VERSION 5.8 ;
BUSBITCHARS "[]" ;
DIVIDERCHAR "/" ;
UNITS
    DATABASE MICRONS 1000 ;
END UNITS

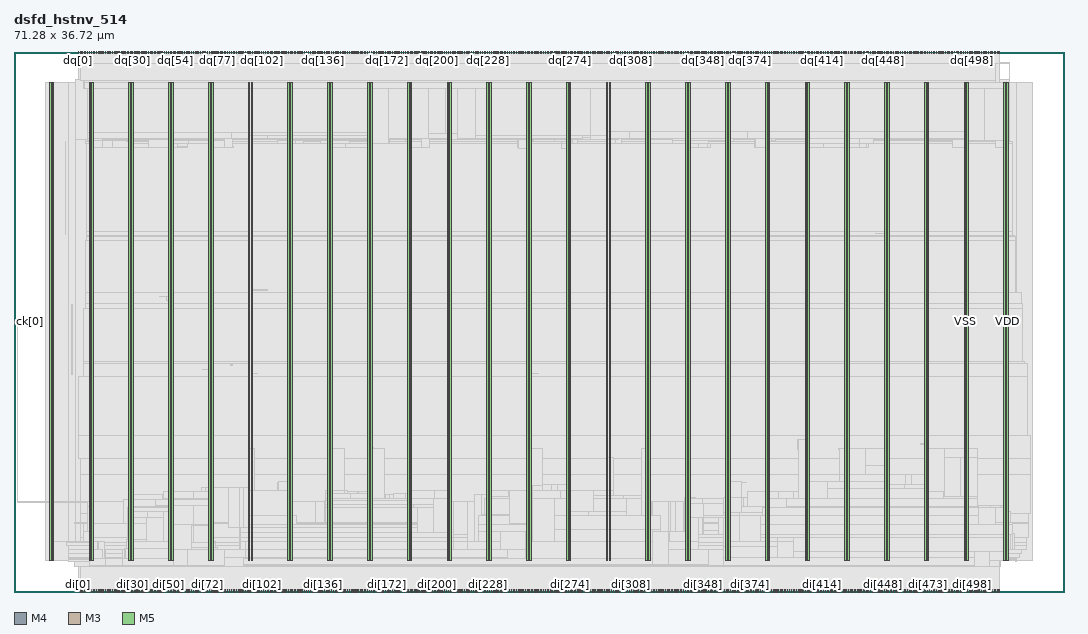
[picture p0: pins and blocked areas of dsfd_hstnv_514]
MACRO dsfd_hstnv_514
  FOREIGN dsfd_hstnv_514 0 0 ;
  CLASS BLOCK ;
  SIZE 71.28 BY 36.72 ;
  PIN ck[0]
    DIRECTION INPUT ;
    USE SIGNAL ;
    PORT
      LAYER M4 ;
        RECT  0 18.384 0.192 18.408 ;
    END
    PORT
      LAYER M4 ;
        RECT  0.156 18.384 0.275 18.408 ;
    END
  END ck[0]
  PIN di[0]
    DIRECTION INPUT ;
    USE SIGNAL ;
    PORT
      LAYER M3 ;
        RECT  4.356 0 4.374 0.144 ;
    END
  END di[0]
  PIN di[100]
    DIRECTION INPUT ;
    USE SIGNAL ;
    PORT
      LAYER M3 ;
        RECT  16.56 0 16.578 0.144 ;
    END
  END di[100]
  PIN di[101]
    DIRECTION INPUT ;
    USE SIGNAL ;
    PORT
      LAYER M5 ;
        RECT  16.656 0 16.68 0.192 ;
    END
  END di[101]
  PIN di[102]
    DIRECTION INPUT ;
    USE SIGNAL ;
    PORT
      LAYER M3 ;
        RECT  16.812 0 16.83 0.144 ;
    END
  END di[102]
  PIN di[103]
    DIRECTION INPUT ;
    USE SIGNAL ;
    PORT
      LAYER M5 ;
        RECT  16.944 0 16.968 0.192 ;
    END
  END di[103]
  PIN di[104]
    DIRECTION INPUT ;
    USE SIGNAL ;
    PORT
      LAYER M3 ;
        RECT  17.064 0 17.082 0.144 ;
    END
  END di[104]
  PIN di[105]
    DIRECTION INPUT ;
    USE SIGNAL ;
    PORT
      LAYER M5 ;
        RECT  17.184 0 17.208 0.192 ;
    END
  END di[105]
  PIN di[106]
    DIRECTION INPUT ;
    USE SIGNAL ;
    PORT
      LAYER M3 ;
        RECT  17.28 0 17.298 0.144 ;
    END
  END di[106]
  PIN di[107]
    DIRECTION INPUT ;
    USE SIGNAL ;
    PORT
      LAYER M5 ;
        RECT  17.424 0 17.448 0.192 ;
    END
  END di[107]
  PIN di[108]
    DIRECTION INPUT ;
    USE SIGNAL ;
    PORT
      LAYER M3 ;
        RECT  17.532 0 17.55 0.144 ;
    END
  END di[108]
  PIN di[109]
    DIRECTION INPUT ;
    USE SIGNAL ;
    PORT
      LAYER M5 ;
        RECT  17.664 0 17.688 0.192 ;
    END
  END di[109]
  PIN di[10]
    DIRECTION INPUT ;
    USE SIGNAL ;
    PORT
      LAYER M3 ;
        RECT  5.58 0 5.598 0.144 ;
    END
  END di[10]
  PIN di[110]
    DIRECTION INPUT ;
    USE SIGNAL ;
    PORT
      LAYER M3 ;
        RECT  17.784 0 17.802 0.144 ;
    END
  END di[110]
  PIN di[111]
    DIRECTION INPUT ;
    USE SIGNAL ;
    PORT
      LAYER M5 ;
        RECT  17.904 0 17.928 0.192 ;
    END
  END di[111]
  PIN di[112]
    DIRECTION INPUT ;
    USE SIGNAL ;
    PORT
      LAYER M3 ;
        RECT  18.036 0 18.054 0.144 ;
    END
  END di[112]
  PIN di[113]
    DIRECTION INPUT ;
    USE SIGNAL ;
    PORT
      LAYER M5 ;
        RECT  18.144 0 18.168 0.192 ;
    END
  END di[113]
  PIN di[114]
    DIRECTION INPUT ;
    USE SIGNAL ;
    PORT
      LAYER M3 ;
        RECT  18.252 0 18.27 0.144 ;
    END
  END di[114]
  PIN di[115]
    DIRECTION INPUT ;
    USE SIGNAL ;
    PORT
      LAYER M5 ;
        RECT  18.384 0 18.408 0.192 ;
    END
  END di[115]
  PIN di[116]
    DIRECTION INPUT ;
    USE SIGNAL ;
    PORT
      LAYER M3 ;
        RECT  18.504 0 18.522 0.144 ;
    END
  END di[116]
  PIN di[117]
    DIRECTION INPUT ;
    USE SIGNAL ;
    PORT
      LAYER M5 ;
        RECT  18.624 0 18.648 0.192 ;
    END
  END di[117]
  PIN di[118]
    DIRECTION INPUT ;
    USE SIGNAL ;
    PORT
      LAYER M3 ;
        RECT  18.756 0 18.774 0.144 ;
    END
  END di[118]
  PIN di[119]
    DIRECTION INPUT ;
    USE SIGNAL ;
    PORT
      LAYER M5 ;
        RECT  18.864 0 18.888 0.192 ;
    END
  END di[119]
  PIN di[11]
    DIRECTION INPUT ;
    USE SIGNAL ;
    PORT
      LAYER M5 ;
        RECT  5.712 0 5.736 0.192 ;
    END
  END di[11]
  PIN di[120]
    DIRECTION INPUT ;
    USE SIGNAL ;
    PORT
      LAYER M3 ;
        RECT  19.008 0 19.026 0.144 ;
    END
  END di[120]
  PIN di[121]
    DIRECTION INPUT ;
    USE SIGNAL ;
    PORT
      LAYER M5 ;
        RECT  19.104 0 19.128 0.192 ;
    END
  END di[121]
  PIN di[122]
    DIRECTION INPUT ;
    USE SIGNAL ;
    PORT
      LAYER M3 ;
        RECT  19.224 0 19.242 0.144 ;
    END
  END di[122]
  PIN di[123]
    DIRECTION INPUT ;
    USE SIGNAL ;
    PORT
      LAYER M5 ;
        RECT  19.344 0 19.368 0.192 ;
    END
  END di[123]
  PIN di[124]
    DIRECTION INPUT ;
    USE SIGNAL ;
    PORT
      LAYER M3 ;
        RECT  19.476 0 19.494 0.144 ;
    END
  END di[124]
  PIN di[125]
    DIRECTION INPUT ;
    USE SIGNAL ;
    PORT
      LAYER M5 ;
        RECT  19.584 0 19.608 0.192 ;
    END
  END di[125]
  PIN di[126]
    DIRECTION INPUT ;
    USE SIGNAL ;
    PORT
      LAYER M3 ;
        RECT  19.728 0 19.746 0.144 ;
    END
  END di[126]
  PIN di[127]
    DIRECTION INPUT ;
    USE SIGNAL ;
    PORT
      LAYER M5 ;
        RECT  19.824 0 19.848 0.192 ;
    END
  END di[127]
  PIN di[128]
    DIRECTION INPUT ;
    USE SIGNAL ;
    PORT
      LAYER M3 ;
        RECT  19.98 0 19.998 0.144 ;
    END
  END di[128]
  PIN di[129]
    DIRECTION INPUT ;
    USE SIGNAL ;
    PORT
      LAYER M5 ;
        RECT  20.112 0 20.136 0.192 ;
    END
  END di[129]
  PIN di[12]
    DIRECTION INPUT ;
    USE SIGNAL ;
    PORT
      LAYER M3 ;
        RECT  5.832 0 5.85 0.144 ;
    END
  END di[12]
  PIN di[130]
    DIRECTION INPUT ;
    USE SIGNAL ;
    PORT
      LAYER M3 ;
        RECT  20.232 0 20.25 0.144 ;
    END
  END di[130]
  PIN di[131]
    DIRECTION INPUT ;
    USE SIGNAL ;
    PORT
      LAYER M5 ;
        RECT  20.352 0 20.376 0.192 ;
    END
    PORT
      LAYER M5 ;
        RECT  20.256 0.133 20.472 0.144 ;
    END
  END di[131]
  PIN di[132]
    DIRECTION INPUT ;
    USE SIGNAL ;
    PORT
      LAYER M3 ;
        RECT  20.448 0 20.466 0.144 ;
    END
  END di[132]
  PIN di[133]
    DIRECTION INPUT ;
    USE SIGNAL ;
    PORT
      LAYER M5 ;
        RECT  20.592 0 20.616 0.192 ;
    END
  END di[133]
  PIN di[134]
    DIRECTION INPUT ;
    USE SIGNAL ;
    PORT
      LAYER M3 ;
        RECT  20.7 0 20.718 0.144 ;
    END
  END di[134]
  PIN di[135]
    DIRECTION INPUT ;
    USE SIGNAL ;
    PORT
      LAYER M5 ;
        RECT  20.832 0 20.856 0.192 ;
    END
  END di[135]
  PIN di[136]
    DIRECTION INPUT ;
    USE SIGNAL ;
    PORT
      LAYER M3 ;
        RECT  20.952 0 20.97 0.144 ;
    END
  END di[136]
  PIN di[137]
    DIRECTION INPUT ;
    USE SIGNAL ;
    PORT
      LAYER M5 ;
        RECT  21.072 0 21.096 0.192 ;
    END
  END di[137]
  PIN di[138]
    DIRECTION INPUT ;
    USE SIGNAL ;
    PORT
      LAYER M3 ;
        RECT  21.204 0 21.222 0.144 ;
    END
  END di[138]
  PIN di[139]
    DIRECTION INPUT ;
    USE SIGNAL ;
    PORT
      LAYER M5 ;
        RECT  21.312 0 21.336 0.192 ;
    END
  END di[139]
  PIN di[13]
    DIRECTION INPUT ;
    USE SIGNAL ;
    PORT
      LAYER M5 ;
        RECT  5.952 0 5.976 0.192 ;
    END
  END di[13]
  PIN di[140]
    DIRECTION INPUT ;
    USE SIGNAL ;
    PORT
      LAYER M3 ;
        RECT  21.42 0 21.438 0.144 ;
    END
  END di[140]
  PIN di[141]
    DIRECTION INPUT ;
    USE SIGNAL ;
    PORT
      LAYER M5 ;
        RECT  21.552 0 21.576 0.192 ;
    END
  END di[141]
  PIN di[142]
    DIRECTION INPUT ;
    USE SIGNAL ;
    PORT
      LAYER M3 ;
        RECT  21.672 0 21.69 0.144 ;
    END
  END di[142]
  PIN di[143]
    DIRECTION INPUT ;
    USE SIGNAL ;
    PORT
      LAYER M5 ;
        RECT  21.792 0 21.816 0.192 ;
    END
  END di[143]
  PIN di[144]
    DIRECTION INPUT ;
    USE SIGNAL ;
    PORT
      LAYER M3 ;
        RECT  21.924 0 21.942 0.144 ;
    END
  END di[144]
  PIN di[145]
    DIRECTION INPUT ;
    USE SIGNAL ;
    PORT
      LAYER M5 ;
        RECT  22.032 0 22.056 0.192 ;
    END
  END di[145]
  PIN di[146]
    DIRECTION INPUT ;
    USE SIGNAL ;
    PORT
      LAYER M3 ;
        RECT  22.176 0 22.194 0.144 ;
    END
  END di[146]
  PIN di[147]
    DIRECTION INPUT ;
    USE SIGNAL ;
    PORT
      LAYER M5 ;
        RECT  22.272 0 22.296 0.192 ;
    END
  END di[147]
  PIN di[148]
    DIRECTION INPUT ;
    USE SIGNAL ;
    PORT
      LAYER M3 ;
        RECT  22.392 0 22.41 0.144 ;
    END
  END di[148]
  PIN di[149]
    DIRECTION INPUT ;
    USE SIGNAL ;
    PORT
      LAYER M5 ;
        RECT  22.512 0 22.536 0.192 ;
    END
  END di[149]
  PIN di[14]
    DIRECTION INPUT ;
    USE SIGNAL ;
    PORT
      LAYER M3 ;
        RECT  6.084 0 6.102 0.144 ;
    END
  END di[14]
  PIN di[150]
    DIRECTION INPUT ;
    USE SIGNAL ;
    PORT
      LAYER M3 ;
        RECT  22.644 0 22.662 0.144 ;
    END
  END di[150]
  PIN di[151]
    DIRECTION INPUT ;
    USE SIGNAL ;
    PORT
      LAYER M5 ;
        RECT  22.752 0 22.776 0.192 ;
    END
  END di[151]
  PIN di[152]
    DIRECTION INPUT ;
    USE SIGNAL ;
    PORT
      LAYER M3 ;
        RECT  22.896 0 22.914 0.144 ;
    END
  END di[152]
  PIN di[153]
    DIRECTION INPUT ;
    USE SIGNAL ;
    PORT
      LAYER M5 ;
        RECT  22.992 0 23.016 0.192 ;
    END
  END di[153]
  PIN di[154]
    DIRECTION INPUT ;
    USE SIGNAL ;
    PORT
      LAYER M3 ;
        RECT  23.148 0 23.166 0.144 ;
    END
  END di[154]
  PIN di[155]
    DIRECTION INPUT ;
    USE SIGNAL ;
    PORT
      LAYER M5 ;
        RECT  23.28 0 23.304 0.192 ;
    END
  END di[155]
  PIN di[156]
    DIRECTION INPUT ;
    USE SIGNAL ;
    PORT
      LAYER M3 ;
        RECT  23.4 0 23.418 0.144 ;
    END
  END di[156]
  PIN di[157]
    DIRECTION INPUT ;
    USE SIGNAL ;
    PORT
      LAYER M5 ;
        RECT  23.52 0 23.544 0.192 ;
    END
  END di[157]
  PIN di[158]
    DIRECTION INPUT ;
    USE SIGNAL ;
    PORT
      LAYER M3 ;
        RECT  23.616 0 23.634 0.144 ;
    END
  END di[158]
  PIN di[159]
    DIRECTION INPUT ;
    USE SIGNAL ;
    PORT
      LAYER M5 ;
        RECT  23.76 0 23.784 0.192 ;
    END
  END di[159]
  PIN di[15]
    DIRECTION INPUT ;
    USE SIGNAL ;
    PORT
      LAYER M5 ;
        RECT  6.192 0 6.216 0.192 ;
    END
  END di[15]
  PIN di[160]
    DIRECTION INPUT ;
    USE SIGNAL ;
    PORT
      LAYER M3 ;
        RECT  23.868 0 23.886 0.144 ;
    END
  END di[160]
  PIN di[161]
    DIRECTION INPUT ;
    USE SIGNAL ;
    PORT
      LAYER M5 ;
        RECT  24 0 24.024 0.192 ;
    END
  END di[161]
  PIN di[162]
    DIRECTION INPUT ;
    USE SIGNAL ;
    PORT
      LAYER M3 ;
        RECT  24.12 0 24.138 0.144 ;
    END
  END di[162]
  PIN di[163]
    DIRECTION INPUT ;
    USE SIGNAL ;
    PORT
      LAYER M5 ;
        RECT  24.24 0 24.264 0.192 ;
    END
  END di[163]
  PIN di[164]
    DIRECTION INPUT ;
    USE SIGNAL ;
    PORT
      LAYER M3 ;
        RECT  24.372 0 24.39 0.144 ;
    END
  END di[164]
  PIN di[165]
    DIRECTION INPUT ;
    USE SIGNAL ;
    PORT
      LAYER M5 ;
        RECT  24.48 0 24.504 0.192 ;
    END
  END di[165]
  PIN di[166]
    DIRECTION INPUT ;
    USE SIGNAL ;
    PORT
      LAYER M3 ;
        RECT  24.588 0 24.606 0.144 ;
    END
  END di[166]
  PIN di[167]
    DIRECTION INPUT ;
    USE SIGNAL ;
    PORT
      LAYER M5 ;
        RECT  24.72 0 24.744 0.192 ;
    END
  END di[167]
  PIN di[168]
    DIRECTION INPUT ;
    USE SIGNAL ;
    PORT
      LAYER M3 ;
        RECT  24.84 0 24.858 0.144 ;
    END
  END di[168]
  PIN di[169]
    DIRECTION INPUT ;
    USE SIGNAL ;
    PORT
      LAYER M5 ;
        RECT  24.96 0 24.984 0.192 ;
    END
  END di[169]
  PIN di[16]
    DIRECTION INPUT ;
    USE SIGNAL ;
    PORT
      LAYER M3 ;
        RECT  6.336 0 6.354 0.144 ;
    END
  END di[16]
  PIN di[170]
    DIRECTION INPUT ;
    USE SIGNAL ;
    PORT
      LAYER M3 ;
        RECT  25.092 0 25.11 0.144 ;
    END
  END di[170]
  PIN di[171]
    DIRECTION INPUT ;
    USE SIGNAL ;
    PORT
      LAYER M5 ;
        RECT  25.2 0 25.224 0.192 ;
    END
  END di[171]
  PIN di[172]
    DIRECTION INPUT ;
    USE SIGNAL ;
    PORT
      LAYER M3 ;
        RECT  25.344 0 25.362 0.144 ;
    END
  END di[172]
  PIN di[173]
    DIRECTION INPUT ;
    USE SIGNAL ;
    PORT
      LAYER M5 ;
        RECT  25.44 0 25.464 0.192 ;
    END
  END di[173]
  PIN di[174]
    DIRECTION INPUT ;
    USE SIGNAL ;
    PORT
      LAYER M3 ;
        RECT  25.56 0 25.578 0.144 ;
    END
  END di[174]
  PIN di[175]
    DIRECTION INPUT ;
    USE SIGNAL ;
    PORT
      LAYER M5 ;
        RECT  25.68 0 25.704 0.192 ;
    END
  END di[175]
  PIN di[176]
    DIRECTION INPUT ;
    USE SIGNAL ;
    PORT
      LAYER M3 ;
        RECT  25.812 0 25.83 0.144 ;
    END
  END di[176]
  PIN di[177]
    DIRECTION INPUT ;
    USE SIGNAL ;
    PORT
      LAYER M5 ;
        RECT  25.92 0 25.944 0.192 ;
    END
  END di[177]
  PIN di[178]
    DIRECTION INPUT ;
    USE SIGNAL ;
    PORT
      LAYER M3 ;
        RECT  26.064 0 26.082 0.144 ;
    END
  END di[178]
  PIN di[179]
    DIRECTION INPUT ;
    USE SIGNAL ;
    PORT
      LAYER M5 ;
        RECT  26.16 0 26.184 0.192 ;
    END
  END di[179]
  PIN di[17]
    DIRECTION INPUT ;
    USE SIGNAL ;
    PORT
      LAYER M5 ;
        RECT  6.432 0 6.456 0.192 ;
    END
  END di[17]
  PIN di[180]
    DIRECTION INPUT ;
    USE SIGNAL ;
    PORT
      LAYER M3 ;
        RECT  26.316 0 26.334 0.144 ;
    END
  END di[180]
  PIN di[181]
    DIRECTION INPUT ;
    USE SIGNAL ;
    PORT
      LAYER M5 ;
        RECT  26.448 0 26.472 0.192 ;
    END
  END di[181]
  PIN di[182]
    DIRECTION INPUT ;
    USE SIGNAL ;
    PORT
      LAYER M3 ;
        RECT  26.568 0 26.586 0.144 ;
    END
  END di[182]
  PIN di[183]
    DIRECTION INPUT ;
    USE SIGNAL ;
    PORT
      LAYER M5 ;
        RECT  26.688 0 26.712 0.192 ;
    END
  END di[183]
  PIN di[184]
    DIRECTION INPUT ;
    USE SIGNAL ;
    PORT
      LAYER M3 ;
        RECT  26.784 0 26.802 0.144 ;
    END
  END di[184]
  PIN di[185]
    DIRECTION INPUT ;
    USE SIGNAL ;
    PORT
      LAYER M5 ;
        RECT  26.928 0 26.952 0.192 ;
    END
  END di[185]
  PIN di[186]
    DIRECTION INPUT ;
    USE SIGNAL ;
    PORT
      LAYER M3 ;
        RECT  27.036 0 27.054 0.144 ;
    END
  END di[186]
  PIN di[187]
    DIRECTION INPUT ;
    USE SIGNAL ;
    PORT
      LAYER M5 ;
        RECT  27.168 0 27.192 0.192 ;
    END
  END di[187]
  PIN di[188]
    DIRECTION INPUT ;
    USE SIGNAL ;
    PORT
      LAYER M3 ;
        RECT  27.288 0 27.306 0.144 ;
    END
  END di[188]
  PIN di[189]
    DIRECTION INPUT ;
    USE SIGNAL ;
    PORT
      LAYER M5 ;
        RECT  27.408 0 27.432 0.192 ;
    END
  END di[189]
  PIN di[18]
    DIRECTION INPUT ;
    USE SIGNAL ;
    PORT
      LAYER M3 ;
        RECT  6.552 0 6.57 0.144 ;
    END
  END di[18]
  PIN di[190]
    DIRECTION INPUT ;
    USE SIGNAL ;
    PORT
      LAYER M3 ;
        RECT  27.54 0 27.558 0.144 ;
    END
  END di[190]
  PIN di[191]
    DIRECTION INPUT ;
    USE SIGNAL ;
    PORT
      LAYER M5 ;
        RECT  27.648 0 27.672 0.192 ;
    END
  END di[191]
  PIN di[192]
    DIRECTION INPUT ;
    USE SIGNAL ;
    PORT
      LAYER M3 ;
        RECT  27.756 0 27.774 0.144 ;
    END
  END di[192]
  PIN di[193]
    DIRECTION INPUT ;
    USE SIGNAL ;
    PORT
      LAYER M5 ;
        RECT  27.888 0 27.912 0.192 ;
    END
  END di[193]
  PIN di[194]
    DIRECTION INPUT ;
    USE SIGNAL ;
    PORT
      LAYER M3 ;
        RECT  28.008 0 28.026 0.144 ;
    END
  END di[194]
  PIN di[195]
    DIRECTION INPUT ;
    USE SIGNAL ;
    PORT
      LAYER M5 ;
        RECT  28.128 0 28.152 0.192 ;
    END
  END di[195]
  PIN di[196]
    DIRECTION INPUT ;
    USE SIGNAL ;
    PORT
      LAYER M3 ;
        RECT  28.26 0 28.278 0.144 ;
    END
  END di[196]
  PIN di[197]
    DIRECTION INPUT ;
    USE SIGNAL ;
    PORT
      LAYER M5 ;
        RECT  28.368 0 28.392 0.192 ;
    END
  END di[197]
  PIN di[198]
    DIRECTION INPUT ;
    USE SIGNAL ;
    PORT
      LAYER M3 ;
        RECT  28.512 0 28.53 0.144 ;
    END
  END di[198]
  PIN di[199]
    DIRECTION INPUT ;
    USE SIGNAL ;
    PORT
      LAYER M5 ;
        RECT  28.608 0 28.632 0.192 ;
    END
  END di[199]
  PIN di[19]
    DIRECTION INPUT ;
    USE SIGNAL ;
    PORT
      LAYER M5 ;
        RECT  6.672 0 6.696 0.192 ;
    END
  END di[19]
  PIN di[1]
    DIRECTION INPUT ;
    USE SIGNAL ;
    PORT
      LAYER M5 ;
        RECT  4.512 0 4.536 0.192 ;
    END
  END di[1]
  PIN di[200]
    DIRECTION INPUT ;
    USE SIGNAL ;
    PORT
      LAYER M3 ;
        RECT  28.728 0 28.746 0.144 ;
    END
  END di[200]
  PIN di[201]
    DIRECTION INPUT ;
    USE SIGNAL ;
    PORT
      LAYER M5 ;
        RECT  28.848 0 28.872 0.192 ;
    END
  END di[201]
  PIN di[202]
    DIRECTION INPUT ;
    USE SIGNAL ;
    PORT
      LAYER M3 ;
        RECT  28.98 0 28.998 0.144 ;
    END
  END di[202]
  PIN di[203]
    DIRECTION INPUT ;
    USE SIGNAL ;
    PORT
      LAYER M5 ;
        RECT  29.088 0 29.112 0.192 ;
    END
  END di[203]
  PIN di[204]
    DIRECTION INPUT ;
    USE SIGNAL ;
    PORT
      LAYER M3 ;
        RECT  29.232 0 29.25 0.144 ;
    END
  END di[204]
  PIN di[205]
    DIRECTION INPUT ;
    USE SIGNAL ;
    PORT
      LAYER M5 ;
        RECT  29.328 0 29.352 0.192 ;
    END
  END di[205]
  PIN di[206]
    DIRECTION INPUT ;
    USE SIGNAL ;
    PORT
      LAYER M3 ;
        RECT  29.484 0 29.502 0.144 ;
    END
  END di[206]
  PIN di[207]
    DIRECTION INPUT ;
    USE SIGNAL ;
    PORT
      LAYER M5 ;
        RECT  29.616 0 29.64 0.192 ;
    END
  END di[207]
  PIN di[208]
    DIRECTION INPUT ;
    USE SIGNAL ;
    PORT
      LAYER M3 ;
        RECT  29.736 0 29.754 0.144 ;
    END
  END di[208]
  PIN di[209]
    DIRECTION INPUT ;
    USE SIGNAL ;
    PORT
      LAYER M5 ;
        RECT  29.856 0 29.88 0.192 ;
    END
  END di[209]
  PIN di[20]
    DIRECTION INPUT ;
    USE SIGNAL ;
    PORT
      LAYER M3 ;
        RECT  6.804 0 6.822 0.144 ;
    END
  END di[20]
  PIN di[210]
    DIRECTION INPUT ;
    USE SIGNAL ;
    PORT
      LAYER M3 ;
        RECT  29.952 0 29.97 0.144 ;
    END
  END di[210]
  PIN di[211]
    DIRECTION INPUT ;
    USE SIGNAL ;
    PORT
      LAYER M5 ;
        RECT  30.096 0 30.12 0.192 ;
    END
  END di[211]
  PIN di[212]
    DIRECTION INPUT ;
    USE SIGNAL ;
    PORT
      LAYER M3 ;
        RECT  30.204 0 30.222 0.144 ;
    END
  END di[212]
  PIN di[213]
    DIRECTION INPUT ;
    USE SIGNAL ;
    PORT
      LAYER M5 ;
        RECT  30.336 0 30.36 0.192 ;
    END
  END di[213]
  PIN di[214]
    DIRECTION INPUT ;
    USE SIGNAL ;
    PORT
      LAYER M3 ;
        RECT  30.456 0 30.474 0.144 ;
    END
  END di[214]
  PIN di[215]
    DIRECTION INPUT ;
    USE SIGNAL ;
    PORT
      LAYER M5 ;
        RECT  30.576 0 30.6 0.192 ;
    END
  END di[215]
  PIN di[216]
    DIRECTION INPUT ;
    USE SIGNAL ;
    PORT
      LAYER M3 ;
        RECT  30.708 0 30.726 0.144 ;
    END
  END di[216]
  PIN di[217]
    DIRECTION INPUT ;
    USE SIGNAL ;
    PORT
      LAYER M5 ;
        RECT  30.816 0 30.84 0.192 ;
    END
  END di[217]
  PIN di[218]
    DIRECTION INPUT ;
    USE SIGNAL ;
    PORT
      LAYER M3 ;
        RECT  30.924 0 30.942 0.144 ;
    END
  END di[218]
  PIN di[219]
    DIRECTION INPUT ;
    USE SIGNAL ;
    PORT
      LAYER M5 ;
        RECT  31.056 0 31.08 0.192 ;
    END
  END di[219]
  PIN di[21]
    DIRECTION INPUT ;
    USE SIGNAL ;
    PORT
      LAYER M5 ;
        RECT  6.912 0 6.936 0.192 ;
    END
  END di[21]
  PIN di[220]
    DIRECTION INPUT ;
    USE SIGNAL ;
    PORT
      LAYER M3 ;
        RECT  31.176 0 31.194 0.144 ;
    END
  END di[220]
  PIN di[221]
    DIRECTION INPUT ;
    USE SIGNAL ;
    PORT
      LAYER M5 ;
        RECT  31.296 0 31.32 0.192 ;
    END
  END di[221]
  PIN di[222]
    DIRECTION INPUT ;
    USE SIGNAL ;
    PORT
      LAYER M3 ;
        RECT  31.428 0 31.446 0.144 ;
    END
  END di[222]
  PIN di[223]
    DIRECTION INPUT ;
    USE SIGNAL ;
    PORT
      LAYER M5 ;
        RECT  31.536 0 31.56 0.192 ;
    END
  END di[223]
  PIN di[224]
    DIRECTION INPUT ;
    USE SIGNAL ;
    PORT
      LAYER M3 ;
        RECT  31.68 0 31.698 0.144 ;
    END
  END di[224]
  PIN di[225]
    DIRECTION INPUT ;
    USE SIGNAL ;
    PORT
      LAYER M5 ;
        RECT  31.776 0 31.8 0.192 ;
    END
  END di[225]
  PIN di[226]
    DIRECTION INPUT ;
    USE SIGNAL ;
    PORT
      LAYER M3 ;
        RECT  31.932 0 31.95 0.144 ;
    END
  END di[226]
  PIN di[227]
    DIRECTION INPUT ;
    USE SIGNAL ;
    PORT
      LAYER M5 ;
        RECT  32.016 0 32.04 0.192 ;
    END
  END di[227]
  PIN di[228]
    DIRECTION INPUT ;
    USE SIGNAL ;
    PORT
      LAYER M3 ;
        RECT  32.148 0 32.166 0.144 ;
    END
  END di[228]
  PIN di[229]
    DIRECTION INPUT ;
    USE SIGNAL ;
    PORT
      LAYER M5 ;
        RECT  32.256 0 32.28 0.192 ;
    END
  END di[229]
  PIN di[22]
    DIRECTION INPUT ;
    USE SIGNAL ;
    PORT
      LAYER M3 ;
        RECT  7.056 0 7.074 0.144 ;
    END
  END di[22]
  PIN di[230]
    DIRECTION INPUT ;
    USE SIGNAL ;
    PORT
      LAYER M3 ;
        RECT  32.4 0 32.418 0.144 ;
    END
  END di[230]
  PIN di[231]
    DIRECTION INPUT ;
    USE SIGNAL ;
    PORT
      LAYER M5 ;
        RECT  32.544 0 32.568 0.192 ;
    END
  END di[231]
  PIN di[232]
    DIRECTION INPUT ;
    USE SIGNAL ;
    PORT
      LAYER M3 ;
        RECT  32.652 0 32.67 0.144 ;
    END
  END di[232]
  PIN di[233]
    DIRECTION INPUT ;
    USE SIGNAL ;
    PORT
      LAYER M5 ;
        RECT  32.784 0 32.808 0.192 ;
    END
  END di[233]
  PIN di[234]
    DIRECTION INPUT ;
    USE SIGNAL ;
    PORT
      LAYER M3 ;
        RECT  32.904 0 32.922 0.144 ;
    END
  END di[234]
  PIN di[235]
    DIRECTION INPUT ;
    USE SIGNAL ;
    PORT
      LAYER M5 ;
        RECT  33.024 0 33.048 0.192 ;
    END
  END di[235]
  PIN di[236]
    DIRECTION INPUT ;
    USE SIGNAL ;
    PORT
      LAYER M3 ;
        RECT  33.12 0 33.138 0.144 ;
    END
  END di[236]
  PIN di[237]
    DIRECTION INPUT ;
    USE SIGNAL ;
    PORT
      LAYER M5 ;
        RECT  33.264 0 33.288 0.192 ;
    END
  END di[237]
  PIN di[238]
    DIRECTION INPUT ;
    USE SIGNAL ;
    PORT
      LAYER M3 ;
        RECT  33.372 0 33.39 0.144 ;
    END
  END di[238]
  PIN di[239]
    DIRECTION INPUT ;
    USE SIGNAL ;
    PORT
      LAYER M5 ;
        RECT  33.504 0 33.528 0.192 ;
    END
  END di[239]
  PIN di[23]
    DIRECTION INPUT ;
    USE SIGNAL ;
    PORT
      LAYER M5 ;
        RECT  7.152 0 7.176 0.192 ;
    END
  END di[23]
  PIN di[240]
    DIRECTION INPUT ;
    USE SIGNAL ;
    PORT
      LAYER M3 ;
        RECT  33.624 0 33.642 0.144 ;
    END
  END di[240]
  PIN di[241]
    DIRECTION INPUT ;
    USE SIGNAL ;
    PORT
      LAYER M5 ;
        RECT  33.744 0 33.768 0.192 ;
    END
  END di[241]
  PIN di[242]
    DIRECTION INPUT ;
    USE SIGNAL ;
    PORT
      LAYER M3 ;
        RECT  33.876 0 33.894 0.144 ;
    END
  END di[242]
  PIN di[243]
    DIRECTION INPUT ;
    USE SIGNAL ;
    PORT
      LAYER M5 ;
        RECT  33.984 0 34.008 0.192 ;
    END
  END di[243]
  PIN di[244]
    DIRECTION INPUT ;
    USE SIGNAL ;
    PORT
      LAYER M3 ;
        RECT  34.092 0 34.11 0.144 ;
    END
  END di[244]
  PIN di[245]
    DIRECTION INPUT ;
    USE SIGNAL ;
    PORT
      LAYER M5 ;
        RECT  34.224 0 34.248 0.192 ;
    END
  END di[245]
  PIN di[246]
    DIRECTION INPUT ;
    USE SIGNAL ;
    PORT
      LAYER M3 ;
        RECT  34.344 0 34.362 0.144 ;
    END
  END di[246]
  PIN di[247]
    DIRECTION INPUT ;
    USE SIGNAL ;
    PORT
      LAYER M5 ;
        RECT  34.464 0 34.488 0.192 ;
    END
  END di[247]
  PIN di[248]
    DIRECTION INPUT ;
    USE SIGNAL ;
    PORT
      LAYER M3 ;
        RECT  34.596 0 34.614 0.144 ;
    END
  END di[248]
  PIN di[249]
    DIRECTION INPUT ;
    USE SIGNAL ;
    PORT
      LAYER M5 ;
        RECT  34.704 0 34.728 0.192 ;
    END
  END di[249]
  PIN di[24]
    DIRECTION INPUT ;
    USE SIGNAL ;
    PORT
      LAYER M3 ;
        RECT  7.308 0 7.326 0.144 ;
    END
  END di[24]
  PIN di[250]
    DIRECTION INPUT ;
    USE SIGNAL ;
    PORT
      LAYER M3 ;
        RECT  34.848 0 34.866 0.144 ;
    END
  END di[250]
  PIN di[251]
    DIRECTION INPUT ;
    USE SIGNAL ;
    PORT
      LAYER M5 ;
        RECT  34.944 0 34.968 0.192 ;
    END
  END di[251]
  PIN di[252]
    DIRECTION INPUT ;
    USE SIGNAL ;
    PORT
      LAYER M3 ;
        RECT  35.1 0 35.118 0.144 ;
    END
  END di[252]
  PIN di[253]
    DIRECTION INPUT ;
    USE SIGNAL ;
    PORT
      LAYER M5 ;
        RECT  35.184 0 35.208 0.192 ;
    END
  END di[253]
  PIN di[254]
    DIRECTION INPUT ;
    USE SIGNAL ;
    PORT
      LAYER M3 ;
        RECT  35.316 0 35.334 0.144 ;
    END
  END di[254]
  PIN di[255]
    DIRECTION INPUT ;
    USE SIGNAL ;
    PORT
      LAYER M5 ;
        RECT  35.424 0 35.448 0.192 ;
    END
  END di[255]
  PIN di[256]
    DIRECTION INPUT ;
    USE SIGNAL ;
    PORT
      LAYER M3 ;
        RECT  35.568 0 35.586 0.144 ;
    END
  END di[256]
  PIN di[257]
    DIRECTION INPUT ;
    USE SIGNAL ;
    PORT
      LAYER M5 ;
        RECT  35.712 0 35.736 0.192 ;
    END
  END di[257]
  PIN di[258]
    DIRECTION INPUT ;
    USE SIGNAL ;
    PORT
      LAYER M3 ;
        RECT  35.82 0 35.838 0.144 ;
    END
  END di[258]
  PIN di[259]
    DIRECTION INPUT ;
    USE SIGNAL ;
    PORT
      LAYER M5 ;
        RECT  35.952 0 35.976 0.192 ;
    END
  END di[259]
  PIN di[25]
    DIRECTION INPUT ;
    USE SIGNAL ;
    PORT
      LAYER M5 ;
        RECT  7.392 0 7.416 0.192 ;
    END
  END di[25]
  PIN di[260]
    DIRECTION INPUT ;
    USE SIGNAL ;
    PORT
      LAYER M3 ;
        RECT  36.072 0 36.09 0.144 ;
    END
  END di[260]
  PIN di[261]
    DIRECTION INPUT ;
    USE SIGNAL ;
    PORT
      LAYER M5 ;
        RECT  36.192 0 36.216 0.192 ;
    END
  END di[261]
  PIN di[262]
    DIRECTION INPUT ;
    USE SIGNAL ;
    PORT
      LAYER M3 ;
        RECT  36.288 0 36.306 0.144 ;
    END
  END di[262]
  PIN di[263]
    DIRECTION INPUT ;
    USE SIGNAL ;
    PORT
      LAYER M5 ;
        RECT  36.432 0 36.456 0.192 ;
    END
  END di[263]
  PIN di[264]
    DIRECTION INPUT ;
    USE SIGNAL ;
    PORT
      LAYER M3 ;
        RECT  36.54 0 36.558 0.144 ;
    END
  END di[264]
  PIN di[265]
    DIRECTION INPUT ;
    USE SIGNAL ;
    PORT
      LAYER M5 ;
        RECT  36.672 0 36.696 0.192 ;
    END
  END di[265]
  PIN di[266]
    DIRECTION INPUT ;
    USE SIGNAL ;
    PORT
      LAYER M3 ;
        RECT  36.792 0 36.81 0.144 ;
    END
  END di[266]
  PIN di[267]
    DIRECTION INPUT ;
    USE SIGNAL ;
    PORT
      LAYER M5 ;
        RECT  36.912 0 36.936 0.192 ;
    END
  END di[267]
  PIN di[268]
    DIRECTION INPUT ;
    USE SIGNAL ;
    PORT
      LAYER M3 ;
        RECT  37.044 0 37.062 0.144 ;
    END
  END di[268]
  PIN di[269]
    DIRECTION INPUT ;
    USE SIGNAL ;
    PORT
      LAYER M5 ;
        RECT  37.152 0 37.176 0.192 ;
    END
  END di[269]
  PIN di[26]
    DIRECTION INPUT ;
    USE SIGNAL ;
    PORT
      LAYER M3 ;
        RECT  7.524 0 7.542 0.144 ;
    END
  END di[26]
  PIN di[270]
    DIRECTION INPUT ;
    USE SIGNAL ;
    PORT
      LAYER M3 ;
        RECT  37.26 0 37.278 0.144 ;
    END
  END di[270]
  PIN di[271]
    DIRECTION INPUT ;
    USE SIGNAL ;
    PORT
      LAYER M5 ;
        RECT  37.392 0 37.416 0.192 ;
    END
  END di[271]
  PIN di[272]
    DIRECTION INPUT ;
    USE SIGNAL ;
    PORT
      LAYER M3 ;
        RECT  37.512 0 37.53 0.144 ;
    END
  END di[272]
  PIN di[273]
    DIRECTION INPUT ;
    USE SIGNAL ;
    PORT
      LAYER M5 ;
        RECT  37.632 0 37.656 0.192 ;
    END
  END di[273]
  PIN di[274]
    DIRECTION INPUT ;
    USE SIGNAL ;
    PORT
      LAYER M3 ;
        RECT  37.764 0 37.782 0.144 ;
    END
  END di[274]
  PIN di[275]
    DIRECTION INPUT ;
    USE SIGNAL ;
    PORT
      LAYER M5 ;
        RECT  37.872 0 37.896 0.192 ;
    END
  END di[275]
  PIN di[276]
    DIRECTION INPUT ;
    USE SIGNAL ;
    PORT
      LAYER M3 ;
        RECT  38.016 0 38.034 0.144 ;
    END
  END di[276]
  PIN di[277]
    DIRECTION INPUT ;
    USE SIGNAL ;
    PORT
      LAYER M5 ;
        RECT  38.112 0 38.136 0.192 ;
    END
  END di[277]
  PIN di[278]
    DIRECTION INPUT ;
    USE SIGNAL ;
    PORT
      LAYER M3 ;
        RECT  38.268 0 38.286 0.144 ;
    END
  END di[278]
  PIN di[279]
    DIRECTION INPUT ;
    USE SIGNAL ;
    PORT
      LAYER M5 ;
        RECT  38.352 0 38.376 0.192 ;
    END
  END di[279]
  PIN di[27]
    DIRECTION INPUT ;
    USE SIGNAL ;
    PORT
      LAYER M5 ;
        RECT  7.68 0 7.704 0.192 ;
    END
  END di[27]
  PIN di[280]
    DIRECTION INPUT ;
    USE SIGNAL ;
    PORT
      LAYER M3 ;
        RECT  38.484 0 38.502 0.144 ;
    END
  END di[280]
  PIN di[281]
    DIRECTION INPUT ;
    USE SIGNAL ;
    PORT
      LAYER M5 ;
        RECT  38.592 0 38.616 0.192 ;
    END
  END di[281]
  PIN di[282]
    DIRECTION INPUT ;
    USE SIGNAL ;
    PORT
      LAYER M3 ;
        RECT  38.736 0 38.754 0.144 ;
    END
  END di[282]
  PIN di[283]
    DIRECTION INPUT ;
    USE SIGNAL ;
    PORT
      LAYER M5 ;
        RECT  38.88 0 38.904 0.192 ;
    END
  END di[283]
  PIN di[284]
    DIRECTION INPUT ;
    USE SIGNAL ;
    PORT
      LAYER M3 ;
        RECT  38.988 0 39.006 0.144 ;
    END
  END di[284]
  PIN di[285]
    DIRECTION INPUT ;
    USE SIGNAL ;
    PORT
      LAYER M5 ;
        RECT  39.12 0 39.144 0.192 ;
    END
  END di[285]
  PIN di[286]
    DIRECTION INPUT ;
    USE SIGNAL ;
    PORT
      LAYER M3 ;
        RECT  39.24 0 39.258 0.144 ;
    END
  END di[286]
  PIN di[287]
    DIRECTION INPUT ;
    USE SIGNAL ;
    PORT
      LAYER M5 ;
        RECT  39.36 0 39.384 0.192 ;
    END
  END di[287]
  PIN di[288]
    DIRECTION INPUT ;
    USE SIGNAL ;
    PORT
      LAYER M3 ;
        RECT  39.456 0 39.474 0.144 ;
    END
  END di[288]
  PIN di[289]
    DIRECTION INPUT ;
    USE SIGNAL ;
    PORT
      LAYER M5 ;
        RECT  39.6 0 39.624 0.192 ;
    END
  END di[289]
  PIN di[28]
    DIRECTION INPUT ;
    USE SIGNAL ;
    PORT
      LAYER M3 ;
        RECT  7.776 0 7.794 0.144 ;
    END
  END di[28]
  PIN di[290]
    DIRECTION INPUT ;
    USE SIGNAL ;
    PORT
      LAYER M3 ;
        RECT  39.708 0 39.726 0.144 ;
    END
  END di[290]
  PIN di[291]
    DIRECTION INPUT ;
    USE SIGNAL ;
    PORT
      LAYER M5 ;
        RECT  39.84 0 39.864 0.192 ;
    END
  END di[291]
  PIN di[292]
    DIRECTION INPUT ;
    USE SIGNAL ;
    PORT
      LAYER M3 ;
        RECT  39.96 0 39.978 0.144 ;
    END
  END di[292]
  PIN di[293]
    DIRECTION INPUT ;
    USE SIGNAL ;
    PORT
      LAYER M5 ;
        RECT  40.08 0 40.104 0.192 ;
    END
  END di[293]
  PIN di[294]
    DIRECTION INPUT ;
    USE SIGNAL ;
    PORT
      LAYER M3 ;
        RECT  40.212 0 40.23 0.144 ;
    END
  END di[294]
  PIN di[295]
    DIRECTION INPUT ;
    USE SIGNAL ;
    PORT
      LAYER M5 ;
        RECT  40.32 0 40.344 0.192 ;
    END
  END di[295]
  PIN di[296]
    DIRECTION INPUT ;
    USE SIGNAL ;
    PORT
      LAYER M3 ;
        RECT  40.428 0 40.446 0.144 ;
    END
  END di[296]
  PIN di[297]
    DIRECTION INPUT ;
    USE SIGNAL ;
    PORT
      LAYER M5 ;
        RECT  40.56 0 40.584 0.192 ;
    END
  END di[297]
  PIN di[298]
    DIRECTION INPUT ;
    USE SIGNAL ;
    PORT
      LAYER M3 ;
        RECT  40.68 0 40.698 0.144 ;
    END
  END di[298]
  PIN di[299]
    DIRECTION INPUT ;
    USE SIGNAL ;
    PORT
      LAYER M5 ;
        RECT  40.8 0 40.824 0.192 ;
    END
  END di[299]
  PIN di[29]
    DIRECTION INPUT ;
    USE SIGNAL ;
    PORT
      LAYER M5 ;
        RECT  7.92 0 7.944 0.192 ;
    END
  END di[29]
  PIN di[2]
    DIRECTION INPUT ;
    USE SIGNAL ;
    PORT
      LAYER M3 ;
        RECT  4.608 0 4.626 0.144 ;
    END
  END di[2]
  PIN di[300]
    DIRECTION INPUT ;
    USE SIGNAL ;
    PORT
      LAYER M3 ;
        RECT  40.932 0 40.95 0.144 ;
    END
  END di[300]
  PIN di[301]
    DIRECTION INPUT ;
    USE SIGNAL ;
    PORT
      LAYER M5 ;
        RECT  41.04 0 41.064 0.192 ;
    END
  END di[301]
  PIN di[302]
    DIRECTION INPUT ;
    USE SIGNAL ;
    PORT
      LAYER M3 ;
        RECT  41.184 0 41.202 0.144 ;
    END
  END di[302]
  PIN di[303]
    DIRECTION INPUT ;
    USE SIGNAL ;
    PORT
      LAYER M5 ;
        RECT  41.28 0 41.304 0.192 ;
    END
  END di[303]
  PIN di[304]
    DIRECTION INPUT ;
    USE SIGNAL ;
    PORT
      LAYER M3 ;
        RECT  41.436 0 41.454 0.144 ;
    END
  END di[304]
  PIN di[305]
    DIRECTION INPUT ;
    USE SIGNAL ;
    PORT
      LAYER M5 ;
        RECT  41.52 0 41.544 0.192 ;
    END
  END di[305]
  PIN di[306]
    DIRECTION INPUT ;
    USE SIGNAL ;
    PORT
      LAYER M3 ;
        RECT  41.652 0 41.67 0.144 ;
    END
  END di[306]
  PIN di[307]
    DIRECTION INPUT ;
    USE SIGNAL ;
    PORT
      LAYER M5 ;
        RECT  41.76 0 41.784 0.192 ;
    END
  END di[307]
  PIN di[308]
    DIRECTION INPUT ;
    USE SIGNAL ;
    PORT
      LAYER M3 ;
        RECT  41.904 0 41.922 0.144 ;
    END
  END di[308]
  PIN di[309]
    DIRECTION INPUT ;
    USE SIGNAL ;
    PORT
      LAYER M5 ;
        RECT  42.048 0 42.072 0.192 ;
    END
  END di[309]
  PIN di[30]
    DIRECTION INPUT ;
    USE SIGNAL ;
    PORT
      LAYER M3 ;
        RECT  8.028 0 8.046 0.144 ;
    END
  END di[30]
  PIN di[310]
    DIRECTION INPUT ;
    USE SIGNAL ;
    PORT
      LAYER M3 ;
        RECT  42.156 0 42.174 0.144 ;
    END
  END di[310]
  PIN di[311]
    DIRECTION INPUT ;
    USE SIGNAL ;
    PORT
      LAYER M5 ;
        RECT  42.288 0 42.312 0.192 ;
    END
  END di[311]
  PIN di[312]
    DIRECTION INPUT ;
    USE SIGNAL ;
    PORT
      LAYER M3 ;
        RECT  42.408 0 42.426 0.144 ;
    END
  END di[312]
  PIN di[313]
    DIRECTION INPUT ;
    USE SIGNAL ;
    PORT
      LAYER M5 ;
        RECT  42.528 0 42.552 0.192 ;
    END
  END di[313]
  PIN di[314]
    DIRECTION INPUT ;
    USE SIGNAL ;
    PORT
      LAYER M3 ;
        RECT  42.624 0 42.642 0.144 ;
    END
  END di[314]
  PIN di[315]
    DIRECTION INPUT ;
    USE SIGNAL ;
    PORT
      LAYER M5 ;
        RECT  42.768 0 42.792 0.192 ;
    END
  END di[315]
  PIN di[316]
    DIRECTION INPUT ;
    USE SIGNAL ;
    PORT
      LAYER M3 ;
        RECT  42.876 0 42.894 0.144 ;
    END
  END di[316]
  PIN di[317]
    DIRECTION INPUT ;
    USE SIGNAL ;
    PORT
      LAYER M5 ;
        RECT  43.008 0 43.032 0.192 ;
    END
  END di[317]
  PIN di[318]
    DIRECTION INPUT ;
    USE SIGNAL ;
    PORT
      LAYER M3 ;
        RECT  43.128 0 43.146 0.144 ;
    END
  END di[318]
  PIN di[319]
    DIRECTION INPUT ;
    USE SIGNAL ;
    PORT
      LAYER M5 ;
        RECT  43.248 0 43.272 0.192 ;
    END
  END di[319]
  PIN di[31]
    DIRECTION INPUT ;
    USE SIGNAL ;
    PORT
      LAYER M5 ;
        RECT  8.16 0 8.184 0.192 ;
    END
  END di[31]
  PIN di[320]
    DIRECTION INPUT ;
    USE SIGNAL ;
    PORT
      LAYER M3 ;
        RECT  43.38 0 43.398 0.144 ;
    END
  END di[320]
  PIN di[321]
    DIRECTION INPUT ;
    USE SIGNAL ;
    PORT
      LAYER M5 ;
        RECT  43.488 0 43.512 0.192 ;
    END
  END di[321]
  PIN di[322]
    DIRECTION INPUT ;
    USE SIGNAL ;
    PORT
      LAYER M3 ;
        RECT  43.596 0 43.614 0.144 ;
    END
  END di[322]
  PIN di[323]
    DIRECTION INPUT ;
    USE SIGNAL ;
    PORT
      LAYER M5 ;
        RECT  43.728 0 43.752 0.192 ;
    END
  END di[323]
  PIN di[324]
    DIRECTION INPUT ;
    USE SIGNAL ;
    PORT
      LAYER M3 ;
        RECT  43.848 0 43.866 0.144 ;
    END
  END di[324]
  PIN di[325]
    DIRECTION INPUT ;
    USE SIGNAL ;
    PORT
      LAYER M5 ;
        RECT  43.968 0 43.992 0.192 ;
    END
  END di[325]
  PIN di[326]
    DIRECTION INPUT ;
    USE SIGNAL ;
    PORT
      LAYER M3 ;
        RECT  44.1 0 44.118 0.144 ;
    END
  END di[326]
  PIN di[327]
    DIRECTION INPUT ;
    USE SIGNAL ;
    PORT
      LAYER M5 ;
        RECT  44.208 0 44.232 0.192 ;
    END
  END di[327]
  PIN di[328]
    DIRECTION INPUT ;
    USE SIGNAL ;
    PORT
      LAYER M3 ;
        RECT  44.352 0 44.37 0.144 ;
    END
  END di[328]
  PIN di[329]
    DIRECTION INPUT ;
    USE SIGNAL ;
    PORT
      LAYER M5 ;
        RECT  44.448 0 44.472 0.192 ;
    END
  END di[329]
  PIN di[32]
    DIRECTION INPUT ;
    USE SIGNAL ;
    PORT
      LAYER M3 ;
        RECT  8.28 0 8.298 0.144 ;
    END
  END di[32]
  PIN di[330]
    DIRECTION INPUT ;
    USE SIGNAL ;
    PORT
      LAYER M3 ;
        RECT  44.604 0 44.622 0.144 ;
    END
  END di[330]
  PIN di[331]
    DIRECTION INPUT ;
    USE SIGNAL ;
    PORT
      LAYER M5 ;
        RECT  44.688 0 44.712 0.192 ;
    END
  END di[331]
  PIN di[332]
    DIRECTION INPUT ;
    USE SIGNAL ;
    PORT
      LAYER M3 ;
        RECT  44.82 0 44.838 0.144 ;
    END
  END di[332]
  PIN di[333]
    DIRECTION INPUT ;
    USE SIGNAL ;
    PORT
      LAYER M5 ;
        RECT  44.928 0 44.952 0.192 ;
    END
  END di[333]
  PIN di[334]
    DIRECTION INPUT ;
    USE SIGNAL ;
    PORT
      LAYER M3 ;
        RECT  45.072 0 45.09 0.144 ;
    END
  END di[334]
  PIN di[335]
    DIRECTION INPUT ;
    USE SIGNAL ;
    PORT
      LAYER M5 ;
        RECT  45.216 0 45.24 0.192 ;
    END
  END di[335]
  PIN di[336]
    DIRECTION INPUT ;
    USE SIGNAL ;
    PORT
      LAYER M3 ;
        RECT  45.324 0 45.342 0.144 ;
    END
  END di[336]
  PIN di[337]
    DIRECTION INPUT ;
    USE SIGNAL ;
    PORT
      LAYER M5 ;
        RECT  45.456 0 45.48 0.192 ;
    END
  END di[337]
  PIN di[338]
    DIRECTION INPUT ;
    USE SIGNAL ;
    PORT
      LAYER M3 ;
        RECT  45.576 0 45.594 0.144 ;
    END
  END di[338]
  PIN di[339]
    DIRECTION INPUT ;
    USE SIGNAL ;
    PORT
      LAYER M5 ;
        RECT  45.696 0 45.72 0.192 ;
    END
  END di[339]
  PIN di[33]
    DIRECTION INPUT ;
    USE SIGNAL ;
    PORT
      LAYER M5 ;
        RECT  8.4 0 8.424 0.192 ;
    END
  END di[33]
  PIN di[340]
    DIRECTION INPUT ;
    USE SIGNAL ;
    PORT
      LAYER M3 ;
        RECT  45.792 0 45.81 0.144 ;
    END
  END di[340]
  PIN di[341]
    DIRECTION INPUT ;
    USE SIGNAL ;
    PORT
      LAYER M5 ;
        RECT  45.936 0 45.96 0.192 ;
    END
  END di[341]
  PIN di[342]
    DIRECTION INPUT ;
    USE SIGNAL ;
    PORT
      LAYER M3 ;
        RECT  46.044 0 46.062 0.144 ;
    END
  END di[342]
  PIN di[343]
    DIRECTION INPUT ;
    USE SIGNAL ;
    PORT
      LAYER M5 ;
        RECT  46.176 0 46.2 0.192 ;
    END
  END di[343]
  PIN di[344]
    DIRECTION INPUT ;
    USE SIGNAL ;
    PORT
      LAYER M3 ;
        RECT  46.296 0 46.314 0.144 ;
    END
  END di[344]
  PIN di[345]
    DIRECTION INPUT ;
    USE SIGNAL ;
    PORT
      LAYER M5 ;
        RECT  46.416 0 46.44 0.192 ;
    END
  END di[345]
  PIN di[346]
    DIRECTION INPUT ;
    USE SIGNAL ;
    PORT
      LAYER M3 ;
        RECT  46.548 0 46.566 0.144 ;
    END
  END di[346]
  PIN di[347]
    DIRECTION INPUT ;
    USE SIGNAL ;
    PORT
      LAYER M5 ;
        RECT  46.656 0 46.68 0.192 ;
    END
  END di[347]
  PIN di[348]
    DIRECTION INPUT ;
    USE SIGNAL ;
    PORT
      LAYER M3 ;
        RECT  46.764 0 46.782 0.144 ;
    END
  END di[348]
  PIN di[349]
    DIRECTION INPUT ;
    USE SIGNAL ;
    PORT
      LAYER M5 ;
        RECT  46.896 0 46.92 0.192 ;
    END
  END di[349]
  PIN di[34]
    DIRECTION INPUT ;
    USE SIGNAL ;
    PORT
      LAYER M3 ;
        RECT  8.532 0 8.55 0.144 ;
    END
  END di[34]
  PIN di[350]
    DIRECTION INPUT ;
    USE SIGNAL ;
    PORT
      LAYER M3 ;
        RECT  47.016 0 47.034 0.144 ;
    END
  END di[350]
  PIN di[351]
    DIRECTION INPUT ;
    USE SIGNAL ;
    PORT
      LAYER M5 ;
        RECT  47.136 0 47.16 0.192 ;
    END
  END di[351]
  PIN di[352]
    DIRECTION INPUT ;
    USE SIGNAL ;
    PORT
      LAYER M3 ;
        RECT  47.268 0 47.286 0.144 ;
    END
  END di[352]
  PIN di[353]
    DIRECTION INPUT ;
    USE SIGNAL ;
    PORT
      LAYER M5 ;
        RECT  47.376 0 47.4 0.192 ;
    END
  END di[353]
  PIN di[354]
    DIRECTION INPUT ;
    USE SIGNAL ;
    PORT
      LAYER M3 ;
        RECT  47.52 0 47.538 0.144 ;
    END
  END di[354]
  PIN di[355]
    DIRECTION INPUT ;
    USE SIGNAL ;
    PORT
      LAYER M5 ;
        RECT  47.616 0 47.64 0.192 ;
    END
  END di[355]
  PIN di[356]
    DIRECTION INPUT ;
    USE SIGNAL ;
    PORT
      LAYER M3 ;
        RECT  47.772 0 47.79 0.144 ;
    END
  END di[356]
  PIN di[357]
    DIRECTION INPUT ;
    USE SIGNAL ;
    PORT
      LAYER M5 ;
        RECT  47.856 0 47.88 0.192 ;
    END
  END di[357]
  PIN di[358]
    DIRECTION INPUT ;
    USE SIGNAL ;
    PORT
      LAYER M3 ;
        RECT  47.988 0 48.006 0.144 ;
    END
  END di[358]
  PIN di[359]
    DIRECTION INPUT ;
    USE SIGNAL ;
    PORT
      LAYER M5 ;
        RECT  48.096 0 48.12 0.192 ;
    END
  END di[359]
  PIN di[35]
    DIRECTION INPUT ;
    USE SIGNAL ;
    PORT
      LAYER M5 ;
        RECT  8.64 0 8.664 0.192 ;
    END
  END di[35]
  PIN di[360]
    DIRECTION INPUT ;
    USE SIGNAL ;
    PORT
      LAYER M3 ;
        RECT  48.24 0 48.258 0.144 ;
    END
  END di[360]
  PIN di[361]
    DIRECTION INPUT ;
    USE SIGNAL ;
    PORT
      LAYER M5 ;
        RECT  48.384 0 48.408 0.192 ;
    END
  END di[361]
  PIN di[362]
    DIRECTION INPUT ;
    USE SIGNAL ;
    PORT
      LAYER M3 ;
        RECT  48.492 0 48.51 0.144 ;
    END
  END di[362]
  PIN di[363]
    DIRECTION INPUT ;
    USE SIGNAL ;
    PORT
      LAYER M5 ;
        RECT  48.624 0 48.648 0.192 ;
    END
  END di[363]
  PIN di[364]
    DIRECTION INPUT ;
    USE SIGNAL ;
    PORT
      LAYER M3 ;
        RECT  48.744 0 48.762 0.144 ;
    END
  END di[364]
  PIN di[365]
    DIRECTION INPUT ;
    USE SIGNAL ;
    PORT
      LAYER M5 ;
        RECT  48.864 0 48.888 0.192 ;
    END
  END di[365]
  PIN di[366]
    DIRECTION INPUT ;
    USE SIGNAL ;
    PORT
      LAYER M3 ;
        RECT  48.96 0 48.978 0.144 ;
    END
  END di[366]
  PIN di[367]
    DIRECTION INPUT ;
    USE SIGNAL ;
    PORT
      LAYER M5 ;
        RECT  49.104 0 49.128 0.192 ;
    END
  END di[367]
  PIN di[368]
    DIRECTION INPUT ;
    USE SIGNAL ;
    PORT
      LAYER M3 ;
        RECT  49.212 0 49.23 0.144 ;
    END
  END di[368]
  PIN di[369]
    DIRECTION INPUT ;
    USE SIGNAL ;
    PORT
      LAYER M5 ;
        RECT  49.344 0 49.368 0.192 ;
    END
  END di[369]
  PIN di[36]
    DIRECTION INPUT ;
    USE SIGNAL ;
    PORT
      LAYER M3 ;
        RECT  8.748 0 8.766 0.144 ;
    END
  END di[36]
  PIN di[370]
    DIRECTION INPUT ;
    USE SIGNAL ;
    PORT
      LAYER M3 ;
        RECT  49.464 0 49.482 0.144 ;
    END
  END di[370]
  PIN di[371]
    DIRECTION INPUT ;
    USE SIGNAL ;
    PORT
      LAYER M5 ;
        RECT  49.584 0 49.608 0.192 ;
    END
  END di[371]
  PIN di[372]
    DIRECTION INPUT ;
    USE SIGNAL ;
    PORT
      LAYER M3 ;
        RECT  49.716 0 49.734 0.144 ;
    END
  END di[372]
  PIN di[373]
    DIRECTION INPUT ;
    USE SIGNAL ;
    PORT
      LAYER M5 ;
        RECT  49.824 0 49.848 0.192 ;
    END
  END di[373]
  PIN di[374]
    DIRECTION INPUT ;
    USE SIGNAL ;
    PORT
      LAYER M3 ;
        RECT  49.968 0 49.986 0.144 ;
    END
  END di[374]
  PIN di[375]
    DIRECTION INPUT ;
    USE SIGNAL ;
    PORT
      LAYER M5 ;
        RECT  50.064 0 50.088 0.192 ;
    END
  END di[375]
  PIN di[376]
    DIRECTION INPUT ;
    USE SIGNAL ;
    PORT
      LAYER M3 ;
        RECT  50.184 0 50.202 0.144 ;
    END
  END di[376]
  PIN di[377]
    DIRECTION INPUT ;
    USE SIGNAL ;
    PORT
      LAYER M5 ;
        RECT  50.304 0 50.328 0.192 ;
    END
  END di[377]
  PIN di[378]
    DIRECTION INPUT ;
    USE SIGNAL ;
    PORT
      LAYER M3 ;
        RECT  50.436 0 50.454 0.144 ;
    END
  END di[378]
  PIN di[379]
    DIRECTION INPUT ;
    USE SIGNAL ;
    PORT
      LAYER M5 ;
        RECT  50.544 0 50.568 0.192 ;
    END
  END di[379]
  PIN di[37]
    DIRECTION INPUT ;
    USE SIGNAL ;
    PORT
      LAYER M5 ;
        RECT  8.88 0 8.904 0.192 ;
    END
  END di[37]
  PIN di[380]
    DIRECTION INPUT ;
    USE SIGNAL ;
    PORT
      LAYER M3 ;
        RECT  50.688 0 50.706 0.144 ;
    END
  END di[380]
  PIN di[381]
    DIRECTION INPUT ;
    USE SIGNAL ;
    PORT
      LAYER M5 ;
        RECT  50.784 0 50.808 0.192 ;
    END
  END di[381]
  PIN di[382]
    DIRECTION INPUT ;
    USE SIGNAL ;
    PORT
      LAYER M3 ;
        RECT  50.94 0 50.958 0.144 ;
    END
  END di[382]
  PIN di[383]
    DIRECTION INPUT ;
    USE SIGNAL ;
    PORT
      LAYER M5 ;
        RECT  51.024 0 51.048 0.192 ;
    END
  END di[383]
  PIN di[384]
    DIRECTION INPUT ;
    USE SIGNAL ;
    PORT
      LAYER M3 ;
        RECT  51.156 0 51.174 0.144 ;
    END
  END di[384]
  PIN di[385]
    DIRECTION INPUT ;
    USE SIGNAL ;
    PORT
      LAYER M5 ;
        RECT  51.264 0 51.288 0.192 ;
    END
  END di[385]
  PIN di[386]
    DIRECTION INPUT ;
    USE SIGNAL ;
    PORT
      LAYER M3 ;
        RECT  51.408 0 51.426 0.144 ;
    END
  END di[386]
  PIN di[387]
    DIRECTION INPUT ;
    USE SIGNAL ;
    PORT
      LAYER M5 ;
        RECT  51.552 0 51.576 0.192 ;
    END
  END di[387]
  PIN di[388]
    DIRECTION INPUT ;
    USE SIGNAL ;
    PORT
      LAYER M3 ;
        RECT  51.66 0 51.678 0.144 ;
    END
  END di[388]
  PIN di[389]
    DIRECTION INPUT ;
    USE SIGNAL ;
    PORT
      LAYER M5 ;
        RECT  51.792 0 51.816 0.192 ;
    END
  END di[389]
  PIN di[38]
    DIRECTION INPUT ;
    USE SIGNAL ;
    PORT
      LAYER M3 ;
        RECT  9 0 9.018 0.144 ;
    END
  END di[38]
  PIN di[390]
    DIRECTION INPUT ;
    USE SIGNAL ;
    PORT
      LAYER M3 ;
        RECT  51.912 0 51.93 0.144 ;
    END
  END di[390]
  PIN di[391]
    DIRECTION INPUT ;
    USE SIGNAL ;
    PORT
      LAYER M5 ;
        RECT  52.032 0 52.056 0.192 ;
    END
  END di[391]
  PIN di[392]
    DIRECTION INPUT ;
    USE SIGNAL ;
    PORT
      LAYER M3 ;
        RECT  52.128 0 52.146 0.144 ;
    END
  END di[392]
  PIN di[393]
    DIRECTION INPUT ;
    USE SIGNAL ;
    PORT
      LAYER M5 ;
        RECT  52.272 0 52.296 0.192 ;
    END
  END di[393]
  PIN di[394]
    DIRECTION INPUT ;
    USE SIGNAL ;
    PORT
      LAYER M3 ;
        RECT  52.38 0 52.398 0.144 ;
    END
  END di[394]
  PIN di[395]
    DIRECTION INPUT ;
    USE SIGNAL ;
    PORT
      LAYER M5 ;
        RECT  52.512 0 52.536 0.192 ;
    END
  END di[395]
  PIN di[396]
    DIRECTION INPUT ;
    USE SIGNAL ;
    PORT
      LAYER M3 ;
        RECT  52.632 0 52.65 0.144 ;
    END
  END di[396]
  PIN di[397]
    DIRECTION INPUT ;
    USE SIGNAL ;
    PORT
      LAYER M5 ;
        RECT  52.752 0 52.776 0.192 ;
    END
  END di[397]
  PIN di[398]
    DIRECTION INPUT ;
    USE SIGNAL ;
    PORT
      LAYER M3 ;
        RECT  52.884 0 52.902 0.144 ;
    END
  END di[398]
  PIN di[399]
    DIRECTION INPUT ;
    USE SIGNAL ;
    PORT
      LAYER M5 ;
        RECT  52.992 0 53.016 0.192 ;
    END
  END di[399]
  PIN di[39]
    DIRECTION INPUT ;
    USE SIGNAL ;
    PORT
      LAYER M5 ;
        RECT  9.12 0 9.144 0.192 ;
    END
  END di[39]
  PIN di[3]
    DIRECTION INPUT ;
    USE SIGNAL ;
    PORT
      LAYER M5 ;
        RECT  4.752 0 4.776 0.192 ;
    END
  END di[3]
  PIN di[400]
    DIRECTION INPUT ;
    USE SIGNAL ;
    PORT
      LAYER M3 ;
        RECT  53.136 0 53.154 0.144 ;
    END
  END di[400]
  PIN di[401]
    DIRECTION INPUT ;
    USE SIGNAL ;
    PORT
      LAYER M5 ;
        RECT  53.232 0 53.256 0.192 ;
    END
  END di[401]
  PIN di[402]
    DIRECTION INPUT ;
    USE SIGNAL ;
    PORT
      LAYER M3 ;
        RECT  53.352 0 53.37 0.144 ;
    END
  END di[402]
  PIN di[403]
    DIRECTION INPUT ;
    USE SIGNAL ;
    PORT
      LAYER M5 ;
        RECT  53.472 0 53.496 0.192 ;
    END
  END di[403]
  PIN di[404]
    DIRECTION INPUT ;
    USE SIGNAL ;
    PORT
      LAYER M3 ;
        RECT  53.604 0 53.622 0.144 ;
    END
  END di[404]
  PIN di[405]
    DIRECTION INPUT ;
    USE SIGNAL ;
    PORT
      LAYER M5 ;
        RECT  53.712 0 53.736 0.192 ;
    END
  END di[405]
  PIN di[406]
    DIRECTION INPUT ;
    USE SIGNAL ;
    PORT
      LAYER M3 ;
        RECT  53.856 0 53.874 0.144 ;
    END
  END di[406]
  PIN di[407]
    DIRECTION INPUT ;
    USE SIGNAL ;
    PORT
      LAYER M5 ;
        RECT  53.952 0 53.976 0.192 ;
    END
  END di[407]
  PIN di[408]
    DIRECTION INPUT ;
    USE SIGNAL ;
    PORT
      LAYER M3 ;
        RECT  54.108 0 54.126 0.144 ;
    END
  END di[408]
  PIN di[409]
    DIRECTION INPUT ;
    USE SIGNAL ;
    PORT
      LAYER M5 ;
        RECT  54.192 0 54.216 0.192 ;
    END
  END di[409]
  PIN di[40]
    DIRECTION INPUT ;
    USE SIGNAL ;
    PORT
      LAYER M3 ;
        RECT  9.252 0 9.27 0.144 ;
    END
  END di[40]
  PIN di[410]
    DIRECTION INPUT ;
    USE SIGNAL ;
    PORT
      LAYER M3 ;
        RECT  54.324 0 54.342 0.144 ;
    END
  END di[410]
  PIN di[411]
    DIRECTION INPUT ;
    USE SIGNAL ;
    PORT
      LAYER M5 ;
        RECT  54.48 0 54.504 0.192 ;
    END
  END di[411]
  PIN di[412]
    DIRECTION INPUT ;
    USE SIGNAL ;
    PORT
      LAYER M3 ;
        RECT  54.576 0 54.594 0.144 ;
    END
  END di[412]
  PIN di[413]
    DIRECTION INPUT ;
    USE SIGNAL ;
    PORT
      LAYER M5 ;
        RECT  54.72 0 54.744 0.192 ;
    END
  END di[413]
  PIN di[414]
    DIRECTION INPUT ;
    USE SIGNAL ;
    PORT
      LAYER M3 ;
        RECT  54.828 0 54.846 0.144 ;
    END
  END di[414]
  PIN di[415]
    DIRECTION INPUT ;
    USE SIGNAL ;
    PORT
      LAYER M5 ;
        RECT  54.96 0 54.984 0.192 ;
    END
  END di[415]
  PIN di[416]
    DIRECTION INPUT ;
    USE SIGNAL ;
    PORT
      LAYER M3 ;
        RECT  55.08 0 55.098 0.144 ;
    END
  END di[416]
  PIN di[417]
    DIRECTION INPUT ;
    USE SIGNAL ;
    PORT
      LAYER M5 ;
        RECT  55.2 0 55.224 0.192 ;
    END
  END di[417]
  PIN di[418]
    DIRECTION INPUT ;
    USE SIGNAL ;
    PORT
      LAYER M3 ;
        RECT  55.296 0 55.314 0.144 ;
    END
  END di[418]
  PIN di[419]
    DIRECTION INPUT ;
    USE SIGNAL ;
    PORT
      LAYER M5 ;
        RECT  55.44 0 55.464 0.192 ;
    END
  END di[419]
  PIN di[41]
    DIRECTION INPUT ;
    USE SIGNAL ;
    PORT
      LAYER M5 ;
        RECT  9.36 0 9.384 0.192 ;
    END
  END di[41]
  PIN di[420]
    DIRECTION INPUT ;
    USE SIGNAL ;
    PORT
      LAYER M3 ;
        RECT  55.548 0 55.566 0.144 ;
    END
  END di[420]
  PIN di[421]
    DIRECTION INPUT ;
    USE SIGNAL ;
    PORT
      LAYER M5 ;
        RECT  55.68 0 55.704 0.192 ;
    END
  END di[421]
  PIN di[422]
    DIRECTION INPUT ;
    USE SIGNAL ;
    PORT
      LAYER M3 ;
        RECT  55.8 0 55.818 0.144 ;
    END
  END di[422]
  PIN di[423]
    DIRECTION INPUT ;
    USE SIGNAL ;
    PORT
      LAYER M5 ;
        RECT  55.92 0 55.944 0.192 ;
    END
  END di[423]
  PIN di[424]
    DIRECTION INPUT ;
    USE SIGNAL ;
    PORT
      LAYER M3 ;
        RECT  56.052 0 56.07 0.144 ;
    END
  END di[424]
  PIN di[425]
    DIRECTION INPUT ;
    USE SIGNAL ;
    PORT
      LAYER M5 ;
        RECT  56.16 0 56.184 0.192 ;
    END
  END di[425]
  PIN di[426]
    DIRECTION INPUT ;
    USE SIGNAL ;
    PORT
      LAYER M3 ;
        RECT  56.304 0 56.322 0.144 ;
    END
  END di[426]
  PIN di[427]
    DIRECTION INPUT ;
    USE SIGNAL ;
    PORT
      LAYER M5 ;
        RECT  56.4 0 56.424 0.192 ;
    END
  END di[427]
  PIN di[428]
    DIRECTION INPUT ;
    USE SIGNAL ;
    PORT
      LAYER M3 ;
        RECT  56.52 0 56.538 0.144 ;
    END
  END di[428]
  PIN di[429]
    DIRECTION INPUT ;
    USE SIGNAL ;
    PORT
      LAYER M5 ;
        RECT  56.64 0 56.664 0.192 ;
    END
  END di[429]
  PIN di[42]
    DIRECTION INPUT ;
    USE SIGNAL ;
    PORT
      LAYER M3 ;
        RECT  9.504 0 9.522 0.144 ;
    END
  END di[42]
  PIN di[430]
    DIRECTION INPUT ;
    USE SIGNAL ;
    PORT
      LAYER M3 ;
        RECT  56.772 0 56.79 0.144 ;
    END
  END di[430]
  PIN di[431]
    DIRECTION INPUT ;
    USE SIGNAL ;
    PORT
      LAYER M5 ;
        RECT  56.88 0 56.904 0.192 ;
    END
  END di[431]
  PIN di[432]
    DIRECTION INPUT ;
    USE SIGNAL ;
    PORT
      LAYER M3 ;
        RECT  57.024 0 57.042 0.144 ;
    END
  END di[432]
  PIN di[433]
    DIRECTION INPUT ;
    USE SIGNAL ;
    PORT
      LAYER M5 ;
        RECT  57.12 0 57.144 0.192 ;
    END
  END di[433]
  PIN di[434]
    DIRECTION INPUT ;
    USE SIGNAL ;
    PORT
      LAYER M3 ;
        RECT  57.276 0 57.294 0.144 ;
    END
  END di[434]
  PIN di[435]
    DIRECTION INPUT ;
    USE SIGNAL ;
    PORT
      LAYER M5 ;
        RECT  57.36 0 57.384 0.192 ;
    END
  END di[435]
  PIN di[436]
    DIRECTION INPUT ;
    USE SIGNAL ;
    PORT
      LAYER M3 ;
        RECT  57.492 0 57.51 0.144 ;
    END
  END di[436]
  PIN di[437]
    DIRECTION INPUT ;
    USE SIGNAL ;
    PORT
      LAYER M5 ;
        RECT  57.648 0 57.672 0.192 ;
    END
  END di[437]
  PIN di[438]
    DIRECTION INPUT ;
    USE SIGNAL ;
    PORT
      LAYER M3 ;
        RECT  57.744 0 57.762 0.144 ;
    END
  END di[438]
  PIN di[439]
    DIRECTION INPUT ;
    USE SIGNAL ;
    PORT
      LAYER M5 ;
        RECT  57.888 0 57.912 0.192 ;
    END
  END di[439]
  PIN di[43]
    DIRECTION INPUT ;
    USE SIGNAL ;
    PORT
      LAYER M5 ;
        RECT  9.6 0 9.624 0.192 ;
    END
  END di[43]
  PIN di[440]
    DIRECTION INPUT ;
    USE SIGNAL ;
    PORT
      LAYER M3 ;
        RECT  57.996 0 58.014 0.144 ;
    END
  END di[440]
  PIN di[441]
    DIRECTION INPUT ;
    USE SIGNAL ;
    PORT
      LAYER M5 ;
        RECT  58.128 0 58.152 0.192 ;
    END
  END di[441]
  PIN di[442]
    DIRECTION INPUT ;
    USE SIGNAL ;
    PORT
      LAYER M3 ;
        RECT  58.248 0 58.266 0.144 ;
    END
  END di[442]
  PIN di[443]
    DIRECTION INPUT ;
    USE SIGNAL ;
    PORT
      LAYER M5 ;
        RECT  58.368 0 58.392 0.192 ;
    END
  END di[443]
  PIN di[444]
    DIRECTION INPUT ;
    USE SIGNAL ;
    PORT
      LAYER M3 ;
        RECT  58.464 0 58.482 0.144 ;
    END
  END di[444]
  PIN di[445]
    DIRECTION INPUT ;
    USE SIGNAL ;
    PORT
      LAYER M5 ;
        RECT  58.608 0 58.632 0.192 ;
    END
  END di[445]
  PIN di[446]
    DIRECTION INPUT ;
    USE SIGNAL ;
    PORT
      LAYER M3 ;
        RECT  58.716 0 58.734 0.144 ;
    END
  END di[446]
  PIN di[447]
    DIRECTION INPUT ;
    USE SIGNAL ;
    PORT
      LAYER M5 ;
        RECT  58.848 0 58.872 0.192 ;
    END
  END di[447]
  PIN di[448]
    DIRECTION INPUT ;
    USE SIGNAL ;
    PORT
      LAYER M3 ;
        RECT  58.968 0 58.986 0.144 ;
    END
  END di[448]
  PIN di[449]
    DIRECTION INPUT ;
    USE SIGNAL ;
    PORT
      LAYER M5 ;
        RECT  59.088 0 59.112 0.192 ;
    END
  END di[449]
  PIN di[44]
    DIRECTION INPUT ;
    USE SIGNAL ;
    PORT
      LAYER M3 ;
        RECT  9.72 0 9.738 0.144 ;
    END
  END di[44]
  PIN di[450]
    DIRECTION INPUT ;
    USE SIGNAL ;
    PORT
      LAYER M3 ;
        RECT  59.22 0 59.238 0.144 ;
    END
  END di[450]
  PIN di[451]
    DIRECTION INPUT ;
    USE SIGNAL ;
    PORT
      LAYER M5 ;
        RECT  59.328 0 59.352 0.192 ;
    END
  END di[451]
  PIN di[452]
    DIRECTION INPUT ;
    USE SIGNAL ;
    PORT
      LAYER M3 ;
        RECT  59.472 0 59.49 0.144 ;
    END
  END di[452]
  PIN di[453]
    DIRECTION INPUT ;
    USE SIGNAL ;
    PORT
      LAYER M5 ;
        RECT  59.568 0 59.592 0.192 ;
    END
  END di[453]
  PIN di[454]
    DIRECTION INPUT ;
    USE SIGNAL ;
    PORT
      LAYER M3 ;
        RECT  59.688 0 59.706 0.144 ;
    END
  END di[454]
  PIN di[455]
    DIRECTION INPUT ;
    USE SIGNAL ;
    PORT
      LAYER M5 ;
        RECT  59.808 0 59.832 0.192 ;
    END
    PORT
      LAYER M5 ;
        RECT  59.712 0.133 59.976 0.144 ;
    END
  END di[455]
  PIN di[456]
    DIRECTION INPUT ;
    USE SIGNAL ;
    PORT
      LAYER M3 ;
        RECT  59.94 0 59.958 0.144 ;
    END
  END di[456]
  PIN di[457]
    DIRECTION INPUT ;
    USE SIGNAL ;
    PORT
      LAYER M5 ;
        RECT  60.048 0 60.072 0.192 ;
    END
  END di[457]
  PIN di[458]
    DIRECTION INPUT ;
    USE SIGNAL ;
    PORT
      LAYER M3 ;
        RECT  60.192 0 60.21 0.144 ;
    END
  END di[458]
  PIN di[459]
    DIRECTION INPUT ;
    USE SIGNAL ;
    PORT
      LAYER M5 ;
        RECT  60.288 0 60.312 0.192 ;
    END
  END di[459]
  PIN di[45]
    DIRECTION INPUT ;
    USE SIGNAL ;
    PORT
      LAYER M5 ;
        RECT  9.84 0 9.864 0.192 ;
    END
  END di[45]
  PIN di[460]
    DIRECTION INPUT ;
    USE SIGNAL ;
    PORT
      LAYER M3 ;
        RECT  60.444 0 60.462 0.144 ;
    END
  END di[460]
  PIN di[461]
    DIRECTION INPUT ;
    USE SIGNAL ;
    PORT
      LAYER M5 ;
        RECT  60.528 0 60.552 0.192 ;
    END
  END di[461]
  PIN di[462]
    DIRECTION INPUT ;
    USE SIGNAL ;
    PORT
      LAYER M3 ;
        RECT  60.66 0 60.678 0.144 ;
    END
  END di[462]
  PIN di[463]
    DIRECTION INPUT ;
    USE SIGNAL ;
    PORT
      LAYER M5 ;
        RECT  60.816 0 60.84 0.192 ;
    END
  END di[463]
  PIN di[464]
    DIRECTION INPUT ;
    USE SIGNAL ;
    PORT
      LAYER M3 ;
        RECT  60.912 0 60.93 0.144 ;
    END
  END di[464]
  PIN di[465]
    DIRECTION INPUT ;
    USE SIGNAL ;
    PORT
      LAYER M5 ;
        RECT  61.056 0 61.08 0.192 ;
    END
  END di[465]
  PIN di[466]
    DIRECTION INPUT ;
    USE SIGNAL ;
    PORT
      LAYER M3 ;
        RECT  61.164 0 61.182 0.144 ;
    END
  END di[466]
  PIN di[467]
    DIRECTION INPUT ;
    USE SIGNAL ;
    PORT
      LAYER M5 ;
        RECT  61.296 0 61.32 0.192 ;
    END
  END di[467]
  PIN di[468]
    DIRECTION INPUT ;
    USE SIGNAL ;
    PORT
      LAYER M3 ;
        RECT  61.416 0 61.434 0.144 ;
    END
  END di[468]
  PIN di[469]
    DIRECTION INPUT ;
    USE SIGNAL ;
    PORT
      LAYER M5 ;
        RECT  61.536 0 61.56 0.192 ;
    END
  END di[469]
  PIN di[46]
    DIRECTION INPUT ;
    USE SIGNAL ;
    PORT
      LAYER M3 ;
        RECT  9.972 0 9.99 0.144 ;
    END
  END di[46]
  PIN di[470]
    DIRECTION INPUT ;
    USE SIGNAL ;
    PORT
      LAYER M3 ;
        RECT  61.632 0 61.65 0.144 ;
    END
  END di[470]
  PIN di[471]
    DIRECTION INPUT ;
    USE SIGNAL ;
    PORT
      LAYER M5 ;
        RECT  61.776 0 61.8 0.192 ;
    END
  END di[471]
  PIN di[472]
    DIRECTION INPUT ;
    USE SIGNAL ;
    PORT
      LAYER M3 ;
        RECT  61.884 0 61.902 0.144 ;
    END
  END di[472]
  PIN di[473]
    DIRECTION INPUT ;
    USE SIGNAL ;
    PORT
      LAYER M5 ;
        RECT  62.016 0 62.04 0.192 ;
    END
  END di[473]
  PIN di[474]
    DIRECTION INPUT ;
    USE SIGNAL ;
    PORT
      LAYER M3 ;
        RECT  62.136 0 62.154 0.144 ;
    END
  END di[474]
  PIN di[475]
    DIRECTION INPUT ;
    USE SIGNAL ;
    PORT
      LAYER M5 ;
        RECT  62.256 0 62.28 0.192 ;
    END
  END di[475]
  PIN di[476]
    DIRECTION INPUT ;
    USE SIGNAL ;
    PORT
      LAYER M3 ;
        RECT  62.388 0 62.406 0.144 ;
    END
  END di[476]
  PIN di[477]
    DIRECTION INPUT ;
    USE SIGNAL ;
    PORT
      LAYER M5 ;
        RECT  62.496 0 62.52 0.192 ;
    END
  END di[477]
  PIN di[478]
    DIRECTION INPUT ;
    USE SIGNAL ;
    PORT
      LAYER M3 ;
        RECT  62.64 0 62.658 0.144 ;
    END
  END di[478]
  PIN di[479]
    DIRECTION INPUT ;
    USE SIGNAL ;
    PORT
      LAYER M5 ;
        RECT  62.736 0 62.76 0.192 ;
    END
  END di[479]
  PIN di[47]
    DIRECTION INPUT ;
    USE SIGNAL ;
    PORT
      LAYER M5 ;
        RECT  10.08 0 10.104 0.192 ;
    END
  END di[47]
  PIN di[480]
    DIRECTION INPUT ;
    USE SIGNAL ;
    PORT
      LAYER M3 ;
        RECT  62.856 0 62.874 0.144 ;
    END
  END di[480]
  PIN di[481]
    DIRECTION INPUT ;
    USE SIGNAL ;
    PORT
      LAYER M5 ;
        RECT  62.976 0 63 0.192 ;
    END
  END di[481]
  PIN di[482]
    DIRECTION INPUT ;
    USE SIGNAL ;
    PORT
      LAYER M3 ;
        RECT  63.108 0 63.126 0.144 ;
    END
  END di[482]
  PIN di[483]
    DIRECTION INPUT ;
    USE SIGNAL ;
    PORT
      LAYER M5 ;
        RECT  63.216 0 63.24 0.192 ;
    END
  END di[483]
  PIN di[484]
    DIRECTION INPUT ;
    USE SIGNAL ;
    PORT
      LAYER M3 ;
        RECT  63.36 0 63.378 0.144 ;
    END
  END di[484]
  PIN di[485]
    DIRECTION INPUT ;
    USE SIGNAL ;
    PORT
      LAYER M5 ;
        RECT  63.456 0 63.48 0.192 ;
    END
  END di[485]
  PIN di[486]
    DIRECTION INPUT ;
    USE SIGNAL ;
    PORT
      LAYER M3 ;
        RECT  63.612 0 63.63 0.144 ;
    END
  END di[486]
  PIN di[487]
    DIRECTION INPUT ;
    USE SIGNAL ;
    PORT
      LAYER M5 ;
        RECT  63.696 0 63.72 0.192 ;
    END
  END di[487]
  PIN di[488]
    DIRECTION INPUT ;
    USE SIGNAL ;
    PORT
      LAYER M3 ;
        RECT  63.828 0 63.846 0.144 ;
    END
  END di[488]
  PIN di[489]
    DIRECTION INPUT ;
    USE SIGNAL ;
    PORT
      LAYER M5 ;
        RECT  63.984 0 64.008 0.192 ;
    END
  END di[489]
  PIN di[48]
    DIRECTION INPUT ;
    USE SIGNAL ;
    PORT
      LAYER M3 ;
        RECT  10.224 0 10.242 0.144 ;
    END
  END di[48]
  PIN di[490]
    DIRECTION INPUT ;
    USE SIGNAL ;
    PORT
      LAYER M3 ;
        RECT  64.08 0 64.098 0.144 ;
    END
  END di[490]
  PIN di[491]
    DIRECTION INPUT ;
    USE SIGNAL ;
    PORT
      LAYER M5 ;
        RECT  64.224 0 64.248 0.192 ;
    END
  END di[491]
  PIN di[492]
    DIRECTION INPUT ;
    USE SIGNAL ;
    PORT
      LAYER M3 ;
        RECT  64.332 0 64.35 0.144 ;
    END
  END di[492]
  PIN di[493]
    DIRECTION INPUT ;
    USE SIGNAL ;
    PORT
      LAYER M5 ;
        RECT  64.464 0 64.488 0.192 ;
    END
  END di[493]
  PIN di[494]
    DIRECTION INPUT ;
    USE SIGNAL ;
    PORT
      LAYER M3 ;
        RECT  64.584 0 64.602 0.144 ;
    END
  END di[494]
  PIN di[495]
    DIRECTION INPUT ;
    USE SIGNAL ;
    PORT
      LAYER M5 ;
        RECT  64.704 0 64.728 0.192 ;
    END
  END di[495]
  PIN di[496]
    DIRECTION INPUT ;
    USE SIGNAL ;
    PORT
      LAYER M3 ;
        RECT  64.836 0 64.854 0.144 ;
    END
  END di[496]
  PIN di[497]
    DIRECTION INPUT ;
    USE SIGNAL ;
    PORT
      LAYER M5 ;
        RECT  64.944 0 64.968 0.192 ;
    END
  END di[497]
  PIN di[498]
    DIRECTION INPUT ;
    USE SIGNAL ;
    PORT
      LAYER M3 ;
        RECT  65.052 0 65.07 0.144 ;
    END
  END di[498]
  PIN di[499]
    DIRECTION INPUT ;
    USE SIGNAL ;
    PORT
      LAYER M5 ;
        RECT  65.184 0 65.208 0.192 ;
    END
  END di[499]
  PIN di[49]
    DIRECTION INPUT ;
    USE SIGNAL ;
    PORT
      LAYER M5 ;
        RECT  10.32 0 10.344 0.192 ;
    END
  END di[49]
  PIN di[4]
    DIRECTION INPUT ;
    USE SIGNAL ;
    PORT
      LAYER M3 ;
        RECT  4.86 0 4.878 0.144 ;
    END
  END di[4]
  PIN di[500]
    DIRECTION INPUT ;
    USE SIGNAL ;
    PORT
      LAYER M3 ;
        RECT  65.304 0 65.322 0.144 ;
    END
  END di[500]
  PIN di[501]
    DIRECTION INPUT ;
    USE SIGNAL ;
    PORT
      LAYER M5 ;
        RECT  65.424 0 65.448 0.192 ;
    END
  END di[501]
  PIN di[502]
    DIRECTION INPUT ;
    USE SIGNAL ;
    PORT
      LAYER M3 ;
        RECT  65.556 0 65.574 0.144 ;
    END
  END di[502]
  PIN di[503]
    DIRECTION INPUT ;
    USE SIGNAL ;
    PORT
      LAYER M5 ;
        RECT  65.664 0 65.688 0.192 ;
    END
  END di[503]
  PIN di[504]
    DIRECTION INPUT ;
    USE SIGNAL ;
    PORT
      LAYER M3 ;
        RECT  65.808 0 65.826 0.144 ;
    END
  END di[504]
  PIN di[505]
    DIRECTION INPUT ;
    USE SIGNAL ;
    PORT
      LAYER M5 ;
        RECT  65.904 0 65.928 0.192 ;
    END
  END di[505]
  PIN di[506]
    DIRECTION INPUT ;
    USE SIGNAL ;
    PORT
      LAYER M3 ;
        RECT  66.024 0 66.042 0.144 ;
    END
  END di[506]
  PIN di[507]
    DIRECTION INPUT ;
    USE SIGNAL ;
    PORT
      LAYER M5 ;
        RECT  66.144 0 66.168 0.192 ;
    END
  END di[507]
  PIN di[508]
    DIRECTION INPUT ;
    USE SIGNAL ;
    PORT
      LAYER M3 ;
        RECT  66.276 0 66.294 0.144 ;
    END
  END di[508]
  PIN di[509]
    DIRECTION INPUT ;
    USE SIGNAL ;
    PORT
      LAYER M5 ;
        RECT  66.384 0 66.408 0.192 ;
    END
  END di[509]
  PIN di[50]
    DIRECTION INPUT ;
    USE SIGNAL ;
    PORT
      LAYER M3 ;
        RECT  10.476 0 10.494 0.144 ;
    END
  END di[50]
  PIN di[510]
    DIRECTION INPUT ;
    USE SIGNAL ;
    PORT
      LAYER M3 ;
        RECT  66.528 0 66.546 0.144 ;
    END
  END di[510]
  PIN di[511]
    DIRECTION INPUT ;
    USE SIGNAL ;
    PORT
      LAYER M5 ;
        RECT  66.624 0 66.648 0.192 ;
    END
  END di[511]
  PIN di[512]
    DIRECTION INPUT ;
    USE SIGNAL ;
    PORT
      LAYER M3 ;
        RECT  66.78 0 66.798 0.144 ;
    END
  END di[512]
  PIN di[513]
    DIRECTION INPUT ;
    USE SIGNAL ;
    PORT
      LAYER M5 ;
        RECT  66.864 0 66.888 0.192 ;
    END
  END di[513]
  PIN di[51]
    DIRECTION INPUT ;
    USE SIGNAL ;
    PORT
      LAYER M5 ;
        RECT  10.608 0 10.632 0.192 ;
    END
  END di[51]
  PIN di[52]
    DIRECTION INPUT ;
    USE SIGNAL ;
    PORT
      LAYER M3 ;
        RECT  10.692 0 10.71 0.144 ;
    END
  END di[52]
  PIN di[53]
    DIRECTION INPUT ;
    USE SIGNAL ;
    PORT
      LAYER M5 ;
        RECT  10.848 0 10.872 0.192 ;
    END
  END di[53]
  PIN di[54]
    DIRECTION INPUT ;
    USE SIGNAL ;
    PORT
      LAYER M3 ;
        RECT  10.944 0 10.962 0.144 ;
    END
  END di[54]
  PIN di[55]
    DIRECTION INPUT ;
    USE SIGNAL ;
    PORT
      LAYER M5 ;
        RECT  11.088 0 11.112 0.192 ;
    END
  END di[55]
  PIN di[56]
    DIRECTION INPUT ;
    USE SIGNAL ;
    PORT
      LAYER M3 ;
        RECT  11.196 0 11.214 0.144 ;
    END
  END di[56]
  PIN di[57]
    DIRECTION INPUT ;
    USE SIGNAL ;
    PORT
      LAYER M5 ;
        RECT  11.328 0 11.352 0.192 ;
    END
  END di[57]
  PIN di[58]
    DIRECTION INPUT ;
    USE SIGNAL ;
    PORT
      LAYER M3 ;
        RECT  11.448 0 11.466 0.144 ;
    END
  END di[58]
  PIN di[59]
    DIRECTION INPUT ;
    USE SIGNAL ;
    PORT
      LAYER M5 ;
        RECT  11.568 0 11.592 0.192 ;
    END
  END di[59]
  PIN di[5]
    DIRECTION INPUT ;
    USE SIGNAL ;
    PORT
      LAYER M5 ;
        RECT  4.992 0 5.016 0.192 ;
    END
  END di[5]
  PIN di[60]
    DIRECTION INPUT ;
    USE SIGNAL ;
    PORT
      LAYER M3 ;
        RECT  11.7 0 11.718 0.144 ;
    END
  END di[60]
  PIN di[61]
    DIRECTION INPUT ;
    USE SIGNAL ;
    PORT
      LAYER M5 ;
        RECT  11.808 0 11.832 0.192 ;
    END
  END di[61]
  PIN di[62]
    DIRECTION INPUT ;
    USE SIGNAL ;
    PORT
      LAYER M3 ;
        RECT  11.916 0 11.934 0.144 ;
    END
  END di[62]
  PIN di[63]
    DIRECTION INPUT ;
    USE SIGNAL ;
    PORT
      LAYER M5 ;
        RECT  12.048 0 12.072 0.192 ;
    END
  END di[63]
  PIN di[64]
    DIRECTION INPUT ;
    USE SIGNAL ;
    PORT
      LAYER M3 ;
        RECT  12.168 0 12.186 0.144 ;
    END
  END di[64]
  PIN di[65]
    DIRECTION INPUT ;
    USE SIGNAL ;
    PORT
      LAYER M5 ;
        RECT  12.288 0 12.312 0.192 ;
    END
  END di[65]
  PIN di[66]
    DIRECTION INPUT ;
    USE SIGNAL ;
    PORT
      LAYER M3 ;
        RECT  12.42 0 12.438 0.144 ;
    END
  END di[66]
  PIN di[67]
    DIRECTION INPUT ;
    USE SIGNAL ;
    PORT
      LAYER M5 ;
        RECT  12.528 0 12.552 0.192 ;
    END
  END di[67]
  PIN di[68]
    DIRECTION INPUT ;
    USE SIGNAL ;
    PORT
      LAYER M3 ;
        RECT  12.672 0 12.69 0.144 ;
    END
  END di[68]
  PIN di[69]
    DIRECTION INPUT ;
    USE SIGNAL ;
    PORT
      LAYER M5 ;
        RECT  12.768 0 12.792 0.192 ;
    END
  END di[69]
  PIN di[6]
    DIRECTION INPUT ;
    USE SIGNAL ;
    PORT
      LAYER M3 ;
        RECT  5.112 0 5.13 0.144 ;
    END
  END di[6]
  PIN di[70]
    DIRECTION INPUT ;
    USE SIGNAL ;
    PORT
      LAYER M3 ;
        RECT  12.888 0 12.906 0.144 ;
    END
  END di[70]
  PIN di[71]
    DIRECTION INPUT ;
    USE SIGNAL ;
    PORT
      LAYER M5 ;
        RECT  13.008 0 13.032 0.192 ;
    END
  END di[71]
  PIN di[72]
    DIRECTION INPUT ;
    USE SIGNAL ;
    PORT
      LAYER M3 ;
        RECT  13.14 0 13.158 0.144 ;
    END
  END di[72]
  PIN di[73]
    DIRECTION INPUT ;
    USE SIGNAL ;
    PORT
      LAYER M5 ;
        RECT  13.248 0 13.272 0.192 ;
    END
  END di[73]
  PIN di[74]
    DIRECTION INPUT ;
    USE SIGNAL ;
    PORT
      LAYER M3 ;
        RECT  13.392 0 13.41 0.144 ;
    END
  END di[74]
  PIN di[75]
    DIRECTION INPUT ;
    USE SIGNAL ;
    PORT
      LAYER M5 ;
        RECT  13.488 0 13.512 0.192 ;
    END
  END di[75]
  PIN di[76]
    DIRECTION INPUT ;
    USE SIGNAL ;
    PORT
      LAYER M3 ;
        RECT  13.644 0 13.662 0.144 ;
    END
  END di[76]
  PIN di[77]
    DIRECTION INPUT ;
    USE SIGNAL ;
    PORT
      LAYER M5 ;
        RECT  13.776 0 13.8 0.192 ;
    END
  END di[77]
  PIN di[78]
    DIRECTION INPUT ;
    USE SIGNAL ;
    PORT
      LAYER M3 ;
        RECT  13.86 0 13.878 0.144 ;
    END
  END di[78]
  PIN di[79]
    DIRECTION INPUT ;
    USE SIGNAL ;
    PORT
      LAYER M5 ;
        RECT  14.016 0 14.04 0.192 ;
    END
  END di[79]
  PIN di[7]
    DIRECTION INPUT ;
    USE SIGNAL ;
    PORT
      LAYER M5 ;
        RECT  5.232 0 5.256 0.192 ;
    END
  END di[7]
  PIN di[80]
    DIRECTION INPUT ;
    USE SIGNAL ;
    PORT
      LAYER M3 ;
        RECT  14.112 0 14.13 0.144 ;
    END
  END di[80]
  PIN di[81]
    DIRECTION INPUT ;
    USE SIGNAL ;
    PORT
      LAYER M5 ;
        RECT  14.256 0 14.28 0.192 ;
    END
  END di[81]
  PIN di[82]
    DIRECTION INPUT ;
    USE SIGNAL ;
    PORT
      LAYER M3 ;
        RECT  14.364 0 14.382 0.144 ;
    END
  END di[82]
  PIN di[83]
    DIRECTION INPUT ;
    USE SIGNAL ;
    PORT
      LAYER M5 ;
        RECT  14.496 0 14.52 0.192 ;
    END
  END di[83]
  PIN di[84]
    DIRECTION INPUT ;
    USE SIGNAL ;
    PORT
      LAYER M3 ;
        RECT  14.616 0 14.634 0.144 ;
    END
  END di[84]
  PIN di[85]
    DIRECTION INPUT ;
    USE SIGNAL ;
    PORT
      LAYER M5 ;
        RECT  14.736 0 14.76 0.192 ;
    END
  END di[85]
  PIN di[86]
    DIRECTION INPUT ;
    USE SIGNAL ;
    PORT
      LAYER M3 ;
        RECT  14.868 0 14.886 0.144 ;
    END
  END di[86]
  PIN di[87]
    DIRECTION INPUT ;
    USE SIGNAL ;
    PORT
      LAYER M5 ;
        RECT  14.976 0 15 0.192 ;
    END
  END di[87]
  PIN di[88]
    DIRECTION INPUT ;
    USE SIGNAL ;
    PORT
      LAYER M3 ;
        RECT  15.084 0 15.102 0.144 ;
    END
  END di[88]
  PIN di[89]
    DIRECTION INPUT ;
    USE SIGNAL ;
    PORT
      LAYER M5 ;
        RECT  15.216 0 15.24 0.192 ;
    END
  END di[89]
  PIN di[8]
    DIRECTION INPUT ;
    USE SIGNAL ;
    PORT
      LAYER M3 ;
        RECT  5.364 0 5.382 0.144 ;
    END
  END di[8]
  PIN di[90]
    DIRECTION INPUT ;
    USE SIGNAL ;
    PORT
      LAYER M3 ;
        RECT  15.336 0 15.354 0.144 ;
    END
  END di[90]
  PIN di[91]
    DIRECTION INPUT ;
    USE SIGNAL ;
    PORT
      LAYER M5 ;
        RECT  15.456 0 15.48 0.192 ;
    END
  END di[91]
  PIN di[92]
    DIRECTION INPUT ;
    USE SIGNAL ;
    PORT
      LAYER M3 ;
        RECT  15.588 0 15.606 0.144 ;
    END
  END di[92]
  PIN di[93]
    DIRECTION INPUT ;
    USE SIGNAL ;
    PORT
      LAYER M5 ;
        RECT  15.696 0 15.72 0.192 ;
    END
  END di[93]
  PIN di[94]
    DIRECTION INPUT ;
    USE SIGNAL ;
    PORT
      LAYER M3 ;
        RECT  15.84 0 15.858 0.144 ;
    END
  END di[94]
  PIN di[95]
    DIRECTION INPUT ;
    USE SIGNAL ;
    PORT
      LAYER M5 ;
        RECT  15.936 0 15.96 0.192 ;
    END
  END di[95]
  PIN di[96]
    DIRECTION INPUT ;
    USE SIGNAL ;
    PORT
      LAYER M3 ;
        RECT  16.056 0 16.074 0.144 ;
    END
  END di[96]
  PIN di[97]
    DIRECTION INPUT ;
    USE SIGNAL ;
    PORT
      LAYER M5 ;
        RECT  16.176 0 16.2 0.192 ;
    END
  END di[97]
  PIN di[98]
    DIRECTION INPUT ;
    USE SIGNAL ;
    PORT
      LAYER M3 ;
        RECT  16.308 0 16.326 0.144 ;
    END
  END di[98]
  PIN di[99]
    DIRECTION INPUT ;
    USE SIGNAL ;
    PORT
      LAYER M5 ;
        RECT  16.416 0 16.44 0.192 ;
    END
  END di[99]
  PIN di[9]
    DIRECTION INPUT ;
    USE SIGNAL ;
    PORT
      LAYER M5 ;
        RECT  5.472 0 5.496 0.192 ;
    END
  END di[9]
  PIN dq[0]
    DIRECTION OUTPUT ;
    USE SIGNAL ;
    PORT
      LAYER M3 ;
        RECT  4.356 36.576 4.374 36.72 ;
    END
  END dq[0]
  PIN dq[100]
    DIRECTION OUTPUT ;
    USE SIGNAL ;
    PORT
      LAYER M3 ;
        RECT  16.56 36.576 16.578 36.72 ;
    END
  END dq[100]
  PIN dq[101]
    DIRECTION OUTPUT ;
    USE SIGNAL ;
    PORT
      LAYER M5 ;
        RECT  16.656 36.528 16.68 36.72 ;
    END
  END dq[101]
  PIN dq[102]
    DIRECTION OUTPUT ;
    USE SIGNAL ;
    PORT
      LAYER M3 ;
        RECT  16.812 36.576 16.83 36.72 ;
    END
  END dq[102]
  PIN dq[103]
    DIRECTION OUTPUT ;
    USE SIGNAL ;
    PORT
      LAYER M5 ;
        RECT  16.944 36.528 16.968 36.72 ;
    END
  END dq[103]
  PIN dq[104]
    DIRECTION OUTPUT ;
    USE SIGNAL ;
    PORT
      LAYER M3 ;
        RECT  17.064 36.576 17.082 36.72 ;
    END
  END dq[104]
  PIN dq[105]
    DIRECTION OUTPUT ;
    USE SIGNAL ;
    PORT
      LAYER M5 ;
        RECT  17.184 36.528 17.208 36.72 ;
    END
  END dq[105]
  PIN dq[106]
    DIRECTION OUTPUT ;
    USE SIGNAL ;
    PORT
      LAYER M3 ;
        RECT  17.28 36.576 17.298 36.72 ;
    END
  END dq[106]
  PIN dq[107]
    DIRECTION OUTPUT ;
    USE SIGNAL ;
    PORT
      LAYER M5 ;
        RECT  17.424 36.528 17.448 36.72 ;
    END
  END dq[107]
  PIN dq[108]
    DIRECTION OUTPUT ;
    USE SIGNAL ;
    PORT
      LAYER M3 ;
        RECT  17.532 36.576 17.55 36.72 ;
    END
  END dq[108]
  PIN dq[109]
    DIRECTION OUTPUT ;
    USE SIGNAL ;
    PORT
      LAYER M5 ;
        RECT  17.664 36.528 17.688 36.72 ;
    END
  END dq[109]
  PIN dq[10]
    DIRECTION OUTPUT ;
    USE SIGNAL ;
    PORT
      LAYER M3 ;
        RECT  5.58 36.576 5.598 36.72 ;
    END
  END dq[10]
  PIN dq[110]
    DIRECTION OUTPUT ;
    USE SIGNAL ;
    PORT
      LAYER M3 ;
        RECT  17.784 36.576 17.802 36.72 ;
    END
  END dq[110]
  PIN dq[111]
    DIRECTION OUTPUT ;
    USE SIGNAL ;
    PORT
      LAYER M5 ;
        RECT  17.904 36.528 17.928 36.72 ;
    END
  END dq[111]
  PIN dq[112]
    DIRECTION OUTPUT ;
    USE SIGNAL ;
    PORT
      LAYER M3 ;
        RECT  18.036 36.576 18.054 36.72 ;
    END
  END dq[112]
  PIN dq[113]
    DIRECTION OUTPUT ;
    USE SIGNAL ;
    PORT
      LAYER M5 ;
        RECT  18.144 36.528 18.168 36.72 ;
    END
  END dq[113]
  PIN dq[114]
    DIRECTION OUTPUT ;
    USE SIGNAL ;
    PORT
      LAYER M3 ;
        RECT  18.252 36.576 18.27 36.72 ;
    END
  END dq[114]
  PIN dq[115]
    DIRECTION OUTPUT ;
    USE SIGNAL ;
    PORT
      LAYER M5 ;
        RECT  18.384 36.528 18.408 36.72 ;
    END
  END dq[115]
  PIN dq[116]
    DIRECTION OUTPUT ;
    USE SIGNAL ;
    PORT
      LAYER M3 ;
        RECT  18.504 36.576 18.522 36.72 ;
    END
  END dq[116]
  PIN dq[117]
    DIRECTION OUTPUT ;
    USE SIGNAL ;
    PORT
      LAYER M5 ;
        RECT  18.624 36.528 18.648 36.72 ;
    END
  END dq[117]
  PIN dq[118]
    DIRECTION OUTPUT ;
    USE SIGNAL ;
    PORT
      LAYER M3 ;
        RECT  18.756 36.576 18.774 36.72 ;
    END
  END dq[118]
  PIN dq[119]
    DIRECTION OUTPUT ;
    USE SIGNAL ;
    PORT
      LAYER M5 ;
        RECT  18.864 36.528 18.888 36.72 ;
    END
  END dq[119]
  PIN dq[11]
    DIRECTION OUTPUT ;
    USE SIGNAL ;
    PORT
      LAYER M5 ;
        RECT  5.712 36.528 5.736 36.72 ;
    END
  END dq[11]
  PIN dq[120]
    DIRECTION OUTPUT ;
    USE SIGNAL ;
    PORT
      LAYER M3 ;
        RECT  19.008 36.576 19.026 36.72 ;
    END
  END dq[120]
  PIN dq[121]
    DIRECTION OUTPUT ;
    USE SIGNAL ;
    PORT
      LAYER M5 ;
        RECT  19.104 36.528 19.128 36.72 ;
    END
  END dq[121]
  PIN dq[122]
    DIRECTION OUTPUT ;
    USE SIGNAL ;
    PORT
      LAYER M3 ;
        RECT  19.224 36.576 19.242 36.72 ;
    END
  END dq[122]
  PIN dq[123]
    DIRECTION OUTPUT ;
    USE SIGNAL ;
    PORT
      LAYER M5 ;
        RECT  19.344 36.528 19.368 36.72 ;
    END
  END dq[123]
  PIN dq[124]
    DIRECTION OUTPUT ;
    USE SIGNAL ;
    PORT
      LAYER M3 ;
        RECT  19.476 36.576 19.494 36.72 ;
    END
  END dq[124]
  PIN dq[125]
    DIRECTION OUTPUT ;
    USE SIGNAL ;
    PORT
      LAYER M5 ;
        RECT  19.584 36.528 19.608 36.72 ;
    END
  END dq[125]
  PIN dq[126]
    DIRECTION OUTPUT ;
    USE SIGNAL ;
    PORT
      LAYER M3 ;
        RECT  19.728 36.576 19.746 36.72 ;
    END
  END dq[126]
  PIN dq[127]
    DIRECTION OUTPUT ;
    USE SIGNAL ;
    PORT
      LAYER M5 ;
        RECT  19.824 36.528 19.848 36.72 ;
    END
  END dq[127]
  PIN dq[128]
    DIRECTION OUTPUT ;
    USE SIGNAL ;
    PORT
      LAYER M3 ;
        RECT  19.98 36.576 19.998 36.72 ;
    END
  END dq[128]
  PIN dq[129]
    DIRECTION OUTPUT ;
    USE SIGNAL ;
    PORT
      LAYER M5 ;
        RECT  20.112 36.528 20.136 36.72 ;
    END
  END dq[129]
  PIN dq[12]
    DIRECTION OUTPUT ;
    USE SIGNAL ;
    PORT
      LAYER M3 ;
        RECT  5.832 36.576 5.85 36.72 ;
    END
  END dq[12]
  PIN dq[130]
    DIRECTION OUTPUT ;
    USE SIGNAL ;
    PORT
      LAYER M3 ;
        RECT  20.232 36.576 20.25 36.72 ;
    END
  END dq[130]
  PIN dq[131]
    DIRECTION OUTPUT ;
    USE SIGNAL ;
    PORT
      LAYER M5 ;
        RECT  20.352 36.528 20.376 36.72 ;
    END
  END dq[131]
  PIN dq[132]
    DIRECTION OUTPUT ;
    USE SIGNAL ;
    PORT
      LAYER M3 ;
        RECT  20.448 36.576 20.466 36.72 ;
    END
  END dq[132]
  PIN dq[133]
    DIRECTION OUTPUT ;
    USE SIGNAL ;
    PORT
      LAYER M5 ;
        RECT  20.592 36.528 20.616 36.72 ;
    END
  END dq[133]
  PIN dq[134]
    DIRECTION OUTPUT ;
    USE SIGNAL ;
    PORT
      LAYER M3 ;
        RECT  20.7 36.576 20.718 36.72 ;
    END
  END dq[134]
  PIN dq[135]
    DIRECTION OUTPUT ;
    USE SIGNAL ;
    PORT
      LAYER M5 ;
        RECT  20.832 36.528 20.856 36.72 ;
    END
  END dq[135]
  PIN dq[136]
    DIRECTION OUTPUT ;
    USE SIGNAL ;
    PORT
      LAYER M3 ;
        RECT  20.952 36.576 20.97 36.72 ;
    END
  END dq[136]
  PIN dq[137]
    DIRECTION OUTPUT ;
    USE SIGNAL ;
    PORT
      LAYER M5 ;
        RECT  21.072 36.528 21.096 36.72 ;
    END
  END dq[137]
  PIN dq[138]
    DIRECTION OUTPUT ;
    USE SIGNAL ;
    PORT
      LAYER M3 ;
        RECT  21.204 36.576 21.222 36.72 ;
    END
  END dq[138]
  PIN dq[139]
    DIRECTION OUTPUT ;
    USE SIGNAL ;
    PORT
      LAYER M5 ;
        RECT  21.312 36.528 21.336 36.72 ;
    END
  END dq[139]
  PIN dq[13]
    DIRECTION OUTPUT ;
    USE SIGNAL ;
    PORT
      LAYER M5 ;
        RECT  5.952 36.528 5.976 36.72 ;
    END
  END dq[13]
  PIN dq[140]
    DIRECTION OUTPUT ;
    USE SIGNAL ;
    PORT
      LAYER M3 ;
        RECT  21.42 36.576 21.438 36.72 ;
    END
  END dq[140]
  PIN dq[141]
    DIRECTION OUTPUT ;
    USE SIGNAL ;
    PORT
      LAYER M5 ;
        RECT  21.552 36.528 21.576 36.72 ;
    END
  END dq[141]
  PIN dq[142]
    DIRECTION OUTPUT ;
    USE SIGNAL ;
    PORT
      LAYER M3 ;
        RECT  21.672 36.576 21.69 36.72 ;
    END
  END dq[142]
  PIN dq[143]
    DIRECTION OUTPUT ;
    USE SIGNAL ;
    PORT
      LAYER M5 ;
        RECT  21.792 36.528 21.816 36.72 ;
    END
  END dq[143]
  PIN dq[144]
    DIRECTION OUTPUT ;
    USE SIGNAL ;
    PORT
      LAYER M3 ;
        RECT  21.924 36.576 21.942 36.72 ;
    END
  END dq[144]
  PIN dq[145]
    DIRECTION OUTPUT ;
    USE SIGNAL ;
    PORT
      LAYER M5 ;
        RECT  22.032 36.528 22.056 36.72 ;
    END
  END dq[145]
  PIN dq[146]
    DIRECTION OUTPUT ;
    USE SIGNAL ;
    PORT
      LAYER M3 ;
        RECT  22.176 36.576 22.194 36.72 ;
    END
  END dq[146]
  PIN dq[147]
    DIRECTION OUTPUT ;
    USE SIGNAL ;
    PORT
      LAYER M5 ;
        RECT  22.272 36.528 22.296 36.72 ;
    END
  END dq[147]
  PIN dq[148]
    DIRECTION OUTPUT ;
    USE SIGNAL ;
    PORT
      LAYER M3 ;
        RECT  22.392 36.576 22.41 36.72 ;
    END
  END dq[148]
  PIN dq[149]
    DIRECTION OUTPUT ;
    USE SIGNAL ;
    PORT
      LAYER M5 ;
        RECT  22.512 36.528 22.536 36.72 ;
    END
  END dq[149]
  PIN dq[14]
    DIRECTION OUTPUT ;
    USE SIGNAL ;
    PORT
      LAYER M3 ;
        RECT  6.084 36.576 6.102 36.72 ;
    END
  END dq[14]
  PIN dq[150]
    DIRECTION OUTPUT ;
    USE SIGNAL ;
    PORT
      LAYER M3 ;
        RECT  22.644 36.576 22.662 36.72 ;
    END
  END dq[150]
  PIN dq[151]
    DIRECTION OUTPUT ;
    USE SIGNAL ;
    PORT
      LAYER M5 ;
        RECT  22.752 36.528 22.776 36.72 ;
    END
  END dq[151]
  PIN dq[152]
    DIRECTION OUTPUT ;
    USE SIGNAL ;
    PORT
      LAYER M3 ;
        RECT  22.896 36.576 22.914 36.72 ;
    END
  END dq[152]
  PIN dq[153]
    DIRECTION OUTPUT ;
    USE SIGNAL ;
    PORT
      LAYER M5 ;
        RECT  22.992 36.528 23.016 36.72 ;
    END
  END dq[153]
  PIN dq[154]
    DIRECTION OUTPUT ;
    USE SIGNAL ;
    PORT
      LAYER M3 ;
        RECT  23.148 36.576 23.166 36.72 ;
    END
  END dq[154]
  PIN dq[155]
    DIRECTION OUTPUT ;
    USE SIGNAL ;
    PORT
      LAYER M5 ;
        RECT  23.28 36.528 23.304 36.72 ;
    END
  END dq[155]
  PIN dq[156]
    DIRECTION OUTPUT ;
    USE SIGNAL ;
    PORT
      LAYER M3 ;
        RECT  23.4 36.576 23.418 36.72 ;
    END
  END dq[156]
  PIN dq[157]
    DIRECTION OUTPUT ;
    USE SIGNAL ;
    PORT
      LAYER M5 ;
        RECT  23.52 36.528 23.544 36.72 ;
    END
  END dq[157]
  PIN dq[158]
    DIRECTION OUTPUT ;
    USE SIGNAL ;
    PORT
      LAYER M3 ;
        RECT  23.616 36.576 23.634 36.72 ;
    END
  END dq[158]
  PIN dq[159]
    DIRECTION OUTPUT ;
    USE SIGNAL ;
    PORT
      LAYER M5 ;
        RECT  23.76 36.528 23.784 36.72 ;
    END
  END dq[159]
  PIN dq[15]
    DIRECTION OUTPUT ;
    USE SIGNAL ;
    PORT
      LAYER M5 ;
        RECT  6.192 36.528 6.216 36.72 ;
    END
  END dq[15]
  PIN dq[160]
    DIRECTION OUTPUT ;
    USE SIGNAL ;
    PORT
      LAYER M3 ;
        RECT  23.868 36.576 23.886 36.72 ;
    END
  END dq[160]
  PIN dq[161]
    DIRECTION OUTPUT ;
    USE SIGNAL ;
    PORT
      LAYER M5 ;
        RECT  24 36.528 24.024 36.72 ;
    END
  END dq[161]
  PIN dq[162]
    DIRECTION OUTPUT ;
    USE SIGNAL ;
    PORT
      LAYER M3 ;
        RECT  24.12 36.576 24.138 36.72 ;
    END
  END dq[162]
  PIN dq[163]
    DIRECTION OUTPUT ;
    USE SIGNAL ;
    PORT
      LAYER M5 ;
        RECT  24.24 36.528 24.264 36.72 ;
    END
  END dq[163]
  PIN dq[164]
    DIRECTION OUTPUT ;
    USE SIGNAL ;
    PORT
      LAYER M3 ;
        RECT  24.372 36.576 24.39 36.72 ;
    END
  END dq[164]
  PIN dq[165]
    DIRECTION OUTPUT ;
    USE SIGNAL ;
    PORT
      LAYER M5 ;
        RECT  24.48 36.528 24.504 36.72 ;
    END
  END dq[165]
  PIN dq[166]
    DIRECTION OUTPUT ;
    USE SIGNAL ;
    PORT
      LAYER M3 ;
        RECT  24.588 36.576 24.606 36.72 ;
    END
  END dq[166]
  PIN dq[167]
    DIRECTION OUTPUT ;
    USE SIGNAL ;
    PORT
      LAYER M5 ;
        RECT  24.72 36.528 24.744 36.72 ;
    END
  END dq[167]
  PIN dq[168]
    DIRECTION OUTPUT ;
    USE SIGNAL ;
    PORT
      LAYER M3 ;
        RECT  24.84 36.576 24.858 36.72 ;
    END
  END dq[168]
  PIN dq[169]
    DIRECTION OUTPUT ;
    USE SIGNAL ;
    PORT
      LAYER M5 ;
        RECT  24.96 36.528 24.984 36.72 ;
    END
  END dq[169]
  PIN dq[16]
    DIRECTION OUTPUT ;
    USE SIGNAL ;
    PORT
      LAYER M3 ;
        RECT  6.336 36.576 6.354 36.72 ;
    END
  END dq[16]
  PIN dq[170]
    DIRECTION OUTPUT ;
    USE SIGNAL ;
    PORT
      LAYER M3 ;
        RECT  25.092 36.576 25.11 36.72 ;
    END
  END dq[170]
  PIN dq[171]
    DIRECTION OUTPUT ;
    USE SIGNAL ;
    PORT
      LAYER M5 ;
        RECT  25.2 36.528 25.224 36.72 ;
    END
  END dq[171]
  PIN dq[172]
    DIRECTION OUTPUT ;
    USE SIGNAL ;
    PORT
      LAYER M3 ;
        RECT  25.344 36.576 25.362 36.72 ;
    END
  END dq[172]
  PIN dq[173]
    DIRECTION OUTPUT ;
    USE SIGNAL ;
    PORT
      LAYER M5 ;
        RECT  25.44 36.528 25.464 36.72 ;
    END
  END dq[173]
  PIN dq[174]
    DIRECTION OUTPUT ;
    USE SIGNAL ;
    PORT
      LAYER M3 ;
        RECT  25.56 36.576 25.578 36.72 ;
    END
  END dq[174]
  PIN dq[175]
    DIRECTION OUTPUT ;
    USE SIGNAL ;
    PORT
      LAYER M5 ;
        RECT  25.68 36.528 25.704 36.72 ;
    END
  END dq[175]
  PIN dq[176]
    DIRECTION OUTPUT ;
    USE SIGNAL ;
    PORT
      LAYER M3 ;
        RECT  25.812 36.576 25.83 36.72 ;
    END
  END dq[176]
  PIN dq[177]
    DIRECTION OUTPUT ;
    USE SIGNAL ;
    PORT
      LAYER M5 ;
        RECT  25.92 36.528 25.944 36.72 ;
    END
  END dq[177]
  PIN dq[178]
    DIRECTION OUTPUT ;
    USE SIGNAL ;
    PORT
      LAYER M3 ;
        RECT  26.064 36.576 26.082 36.72 ;
    END
  END dq[178]
  PIN dq[179]
    DIRECTION OUTPUT ;
    USE SIGNAL ;
    PORT
      LAYER M5 ;
        RECT  26.16 36.528 26.184 36.72 ;
    END
  END dq[179]
  PIN dq[17]
    DIRECTION OUTPUT ;
    USE SIGNAL ;
    PORT
      LAYER M5 ;
        RECT  6.432 36.528 6.456 36.72 ;
    END
  END dq[17]
  PIN dq[180]
    DIRECTION OUTPUT ;
    USE SIGNAL ;
    PORT
      LAYER M3 ;
        RECT  26.316 36.576 26.334 36.72 ;
    END
  END dq[180]
  PIN dq[181]
    DIRECTION OUTPUT ;
    USE SIGNAL ;
    PORT
      LAYER M5 ;
        RECT  26.448 36.528 26.472 36.72 ;
    END
  END dq[181]
  PIN dq[182]
    DIRECTION OUTPUT ;
    USE SIGNAL ;
    PORT
      LAYER M3 ;
        RECT  26.568 36.576 26.586 36.72 ;
    END
  END dq[182]
  PIN dq[183]
    DIRECTION OUTPUT ;
    USE SIGNAL ;
    PORT
      LAYER M5 ;
        RECT  26.688 36.528 26.712 36.72 ;
    END
  END dq[183]
  PIN dq[184]
    DIRECTION OUTPUT ;
    USE SIGNAL ;
    PORT
      LAYER M3 ;
        RECT  26.784 36.576 26.802 36.72 ;
    END
  END dq[184]
  PIN dq[185]
    DIRECTION OUTPUT ;
    USE SIGNAL ;
    PORT
      LAYER M5 ;
        RECT  26.928 36.528 26.952 36.72 ;
    END
  END dq[185]
  PIN dq[186]
    DIRECTION OUTPUT ;
    USE SIGNAL ;
    PORT
      LAYER M3 ;
        RECT  27.036 36.576 27.054 36.72 ;
    END
  END dq[186]
  PIN dq[187]
    DIRECTION OUTPUT ;
    USE SIGNAL ;
    PORT
      LAYER M5 ;
        RECT  27.168 36.528 27.192 36.72 ;
    END
  END dq[187]
  PIN dq[188]
    DIRECTION OUTPUT ;
    USE SIGNAL ;
    PORT
      LAYER M3 ;
        RECT  27.288 36.576 27.306 36.72 ;
    END
  END dq[188]
  PIN dq[189]
    DIRECTION OUTPUT ;
    USE SIGNAL ;
    PORT
      LAYER M5 ;
        RECT  27.408 36.528 27.432 36.72 ;
    END
  END dq[189]
  PIN dq[18]
    DIRECTION OUTPUT ;
    USE SIGNAL ;
    PORT
      LAYER M3 ;
        RECT  6.552 36.576 6.57 36.72 ;
    END
  END dq[18]
  PIN dq[190]
    DIRECTION OUTPUT ;
    USE SIGNAL ;
    PORT
      LAYER M3 ;
        RECT  27.54 36.576 27.558 36.72 ;
    END
  END dq[190]
  PIN dq[191]
    DIRECTION OUTPUT ;
    USE SIGNAL ;
    PORT
      LAYER M5 ;
        RECT  27.648 36.528 27.672 36.72 ;
    END
  END dq[191]
  PIN dq[192]
    DIRECTION OUTPUT ;
    USE SIGNAL ;
    PORT
      LAYER M3 ;
        RECT  27.756 36.576 27.774 36.72 ;
    END
  END dq[192]
  PIN dq[193]
    DIRECTION OUTPUT ;
    USE SIGNAL ;
    PORT
      LAYER M5 ;
        RECT  27.888 36.528 27.912 36.72 ;
    END
  END dq[193]
  PIN dq[194]
    DIRECTION OUTPUT ;
    USE SIGNAL ;
    PORT
      LAYER M3 ;
        RECT  28.008 36.576 28.026 36.72 ;
    END
  END dq[194]
  PIN dq[195]
    DIRECTION OUTPUT ;
    USE SIGNAL ;
    PORT
      LAYER M5 ;
        RECT  28.128 36.528 28.152 36.72 ;
    END
  END dq[195]
  PIN dq[196]
    DIRECTION OUTPUT ;
    USE SIGNAL ;
    PORT
      LAYER M3 ;
        RECT  28.26 36.576 28.278 36.72 ;
    END
  END dq[196]
  PIN dq[197]
    DIRECTION OUTPUT ;
    USE SIGNAL ;
    PORT
      LAYER M5 ;
        RECT  28.368 36.528 28.392 36.72 ;
    END
  END dq[197]
  PIN dq[198]
    DIRECTION OUTPUT ;
    USE SIGNAL ;
    PORT
      LAYER M3 ;
        RECT  28.512 36.576 28.53 36.72 ;
    END
  END dq[198]
  PIN dq[199]
    DIRECTION OUTPUT ;
    USE SIGNAL ;
    PORT
      LAYER M5 ;
        RECT  28.608 36.528 28.632 36.72 ;
    END
  END dq[199]
  PIN dq[19]
    DIRECTION OUTPUT ;
    USE SIGNAL ;
    PORT
      LAYER M5 ;
        RECT  6.672 36.528 6.696 36.72 ;
    END
  END dq[19]
  PIN dq[1]
    DIRECTION OUTPUT ;
    USE SIGNAL ;
    PORT
      LAYER M5 ;
        RECT  4.512 36.528 4.536 36.72 ;
    END
  END dq[1]
  PIN dq[200]
    DIRECTION OUTPUT ;
    USE SIGNAL ;
    PORT
      LAYER M3 ;
        RECT  28.728 36.576 28.746 36.72 ;
    END
  END dq[200]
  PIN dq[201]
    DIRECTION OUTPUT ;
    USE SIGNAL ;
    PORT
      LAYER M5 ;
        RECT  28.848 36.528 28.872 36.72 ;
    END
  END dq[201]
  PIN dq[202]
    DIRECTION OUTPUT ;
    USE SIGNAL ;
    PORT
      LAYER M3 ;
        RECT  28.98 36.576 28.998 36.72 ;
    END
  END dq[202]
  PIN dq[203]
    DIRECTION OUTPUT ;
    USE SIGNAL ;
    PORT
      LAYER M5 ;
        RECT  29.088 36.528 29.112 36.72 ;
    END
  END dq[203]
  PIN dq[204]
    DIRECTION OUTPUT ;
    USE SIGNAL ;
    PORT
      LAYER M3 ;
        RECT  29.232 36.576 29.25 36.72 ;
    END
  END dq[204]
  PIN dq[205]
    DIRECTION OUTPUT ;
    USE SIGNAL ;
    PORT
      LAYER M5 ;
        RECT  29.328 36.528 29.352 36.72 ;
    END
  END dq[205]
  PIN dq[206]
    DIRECTION OUTPUT ;
    USE SIGNAL ;
    PORT
      LAYER M3 ;
        RECT  29.484 36.576 29.502 36.72 ;
    END
  END dq[206]
  PIN dq[207]
    DIRECTION OUTPUT ;
    USE SIGNAL ;
    PORT
      LAYER M5 ;
        RECT  29.616 36.528 29.64 36.72 ;
    END
  END dq[207]
  PIN dq[208]
    DIRECTION OUTPUT ;
    USE SIGNAL ;
    PORT
      LAYER M3 ;
        RECT  29.736 36.576 29.754 36.72 ;
    END
  END dq[208]
  PIN dq[209]
    DIRECTION OUTPUT ;
    USE SIGNAL ;
    PORT
      LAYER M5 ;
        RECT  29.856 36.528 29.88 36.72 ;
    END
  END dq[209]
  PIN dq[20]
    DIRECTION OUTPUT ;
    USE SIGNAL ;
    PORT
      LAYER M3 ;
        RECT  6.804 36.576 6.822 36.72 ;
    END
  END dq[20]
  PIN dq[210]
    DIRECTION OUTPUT ;
    USE SIGNAL ;
    PORT
      LAYER M3 ;
        RECT  29.952 36.576 29.97 36.72 ;
    END
  END dq[210]
  PIN dq[211]
    DIRECTION OUTPUT ;
    USE SIGNAL ;
    PORT
      LAYER M5 ;
        RECT  30.096 36.528 30.12 36.72 ;
    END
  END dq[211]
  PIN dq[212]
    DIRECTION OUTPUT ;
    USE SIGNAL ;
    PORT
      LAYER M3 ;
        RECT  30.204 36.576 30.222 36.72 ;
    END
  END dq[212]
  PIN dq[213]
    DIRECTION OUTPUT ;
    USE SIGNAL ;
    PORT
      LAYER M5 ;
        RECT  30.336 36.528 30.36 36.72 ;
    END
  END dq[213]
  PIN dq[214]
    DIRECTION OUTPUT ;
    USE SIGNAL ;
    PORT
      LAYER M3 ;
        RECT  30.456 36.576 30.474 36.72 ;
    END
  END dq[214]
  PIN dq[215]
    DIRECTION OUTPUT ;
    USE SIGNAL ;
    PORT
      LAYER M5 ;
        RECT  30.576 36.528 30.6 36.72 ;
    END
  END dq[215]
  PIN dq[216]
    DIRECTION OUTPUT ;
    USE SIGNAL ;
    PORT
      LAYER M3 ;
        RECT  30.708 36.576 30.726 36.72 ;
    END
  END dq[216]
  PIN dq[217]
    DIRECTION OUTPUT ;
    USE SIGNAL ;
    PORT
      LAYER M5 ;
        RECT  30.816 36.528 30.84 36.72 ;
    END
  END dq[217]
  PIN dq[218]
    DIRECTION OUTPUT ;
    USE SIGNAL ;
    PORT
      LAYER M3 ;
        RECT  30.924 36.576 30.942 36.72 ;
    END
  END dq[218]
  PIN dq[219]
    DIRECTION OUTPUT ;
    USE SIGNAL ;
    PORT
      LAYER M5 ;
        RECT  31.056 36.528 31.08 36.72 ;
    END
  END dq[219]
  PIN dq[21]
    DIRECTION OUTPUT ;
    USE SIGNAL ;
    PORT
      LAYER M5 ;
        RECT  6.912 36.528 6.936 36.72 ;
    END
  END dq[21]
  PIN dq[220]
    DIRECTION OUTPUT ;
    USE SIGNAL ;
    PORT
      LAYER M3 ;
        RECT  31.176 36.576 31.194 36.72 ;
    END
  END dq[220]
  PIN dq[221]
    DIRECTION OUTPUT ;
    USE SIGNAL ;
    PORT
      LAYER M5 ;
        RECT  31.296 36.528 31.32 36.72 ;
    END
  END dq[221]
  PIN dq[222]
    DIRECTION OUTPUT ;
    USE SIGNAL ;
    PORT
      LAYER M3 ;
        RECT  31.428 36.576 31.446 36.72 ;
    END
  END dq[222]
  PIN dq[223]
    DIRECTION OUTPUT ;
    USE SIGNAL ;
    PORT
      LAYER M5 ;
        RECT  31.536 36.528 31.56 36.72 ;
    END
  END dq[223]
  PIN dq[224]
    DIRECTION OUTPUT ;
    USE SIGNAL ;
    PORT
      LAYER M3 ;
        RECT  31.68 36.576 31.698 36.72 ;
    END
  END dq[224]
  PIN dq[225]
    DIRECTION OUTPUT ;
    USE SIGNAL ;
    PORT
      LAYER M5 ;
        RECT  31.776 36.528 31.8 36.72 ;
    END
  END dq[225]
  PIN dq[226]
    DIRECTION OUTPUT ;
    USE SIGNAL ;
    PORT
      LAYER M3 ;
        RECT  31.932 36.576 31.95 36.72 ;
    END
  END dq[226]
  PIN dq[227]
    DIRECTION OUTPUT ;
    USE SIGNAL ;
    PORT
      LAYER M5 ;
        RECT  32.016 36.528 32.04 36.72 ;
    END
  END dq[227]
  PIN dq[228]
    DIRECTION OUTPUT ;
    USE SIGNAL ;
    PORT
      LAYER M3 ;
        RECT  32.148 36.576 32.166 36.72 ;
    END
  END dq[228]
  PIN dq[229]
    DIRECTION OUTPUT ;
    USE SIGNAL ;
    PORT
      LAYER M5 ;
        RECT  32.256 36.528 32.28 36.72 ;
    END
  END dq[229]
  PIN dq[22]
    DIRECTION OUTPUT ;
    USE SIGNAL ;
    PORT
      LAYER M3 ;
        RECT  7.056 36.576 7.074 36.72 ;
    END
  END dq[22]
  PIN dq[230]
    DIRECTION OUTPUT ;
    USE SIGNAL ;
    PORT
      LAYER M3 ;
        RECT  32.4 36.576 32.418 36.72 ;
    END
  END dq[230]
  PIN dq[231]
    DIRECTION OUTPUT ;
    USE SIGNAL ;
    PORT
      LAYER M5 ;
        RECT  32.544 36.528 32.568 36.72 ;
    END
  END dq[231]
  PIN dq[232]
    DIRECTION OUTPUT ;
    USE SIGNAL ;
    PORT
      LAYER M3 ;
        RECT  32.652 36.576 32.67 36.72 ;
    END
  END dq[232]
  PIN dq[233]
    DIRECTION OUTPUT ;
    USE SIGNAL ;
    PORT
      LAYER M5 ;
        RECT  32.784 36.528 32.808 36.72 ;
    END
  END dq[233]
  PIN dq[234]
    DIRECTION OUTPUT ;
    USE SIGNAL ;
    PORT
      LAYER M3 ;
        RECT  32.904 36.576 32.922 36.72 ;
    END
  END dq[234]
  PIN dq[235]
    DIRECTION OUTPUT ;
    USE SIGNAL ;
    PORT
      LAYER M5 ;
        RECT  33.024 36.528 33.048 36.72 ;
    END
  END dq[235]
  PIN dq[236]
    DIRECTION OUTPUT ;
    USE SIGNAL ;
    PORT
      LAYER M3 ;
        RECT  33.12 36.576 33.138 36.72 ;
    END
  END dq[236]
  PIN dq[237]
    DIRECTION OUTPUT ;
    USE SIGNAL ;
    PORT
      LAYER M5 ;
        RECT  33.264 36.528 33.288 36.72 ;
    END
  END dq[237]
  PIN dq[238]
    DIRECTION OUTPUT ;
    USE SIGNAL ;
    PORT
      LAYER M3 ;
        RECT  33.372 36.576 33.39 36.72 ;
    END
  END dq[238]
  PIN dq[239]
    DIRECTION OUTPUT ;
    USE SIGNAL ;
    PORT
      LAYER M5 ;
        RECT  33.504 36.528 33.528 36.72 ;
    END
  END dq[239]
  PIN dq[23]
    DIRECTION OUTPUT ;
    USE SIGNAL ;
    PORT
      LAYER M5 ;
        RECT  7.152 36.528 7.176 36.72 ;
    END
  END dq[23]
  PIN dq[240]
    DIRECTION OUTPUT ;
    USE SIGNAL ;
    PORT
      LAYER M3 ;
        RECT  33.624 36.576 33.642 36.72 ;
    END
  END dq[240]
  PIN dq[241]
    DIRECTION OUTPUT ;
    USE SIGNAL ;
    PORT
      LAYER M5 ;
        RECT  33.744 36.528 33.768 36.72 ;
    END
  END dq[241]
  PIN dq[242]
    DIRECTION OUTPUT ;
    USE SIGNAL ;
    PORT
      LAYER M3 ;
        RECT  33.876 36.576 33.894 36.72 ;
    END
  END dq[242]
  PIN dq[243]
    DIRECTION OUTPUT ;
    USE SIGNAL ;
    PORT
      LAYER M5 ;
        RECT  33.984 36.528 34.008 36.72 ;
    END
  END dq[243]
  PIN dq[244]
    DIRECTION OUTPUT ;
    USE SIGNAL ;
    PORT
      LAYER M3 ;
        RECT  34.092 36.576 34.11 36.72 ;
    END
  END dq[244]
  PIN dq[245]
    DIRECTION OUTPUT ;
    USE SIGNAL ;
    PORT
      LAYER M5 ;
        RECT  34.224 36.528 34.248 36.72 ;
    END
  END dq[245]
  PIN dq[246]
    DIRECTION OUTPUT ;
    USE SIGNAL ;
    PORT
      LAYER M3 ;
        RECT  34.344 36.576 34.362 36.72 ;
    END
  END dq[246]
  PIN dq[247]
    DIRECTION OUTPUT ;
    USE SIGNAL ;
    PORT
      LAYER M5 ;
        RECT  34.464 36.528 34.488 36.72 ;
    END
  END dq[247]
  PIN dq[248]
    DIRECTION OUTPUT ;
    USE SIGNAL ;
    PORT
      LAYER M3 ;
        RECT  34.596 36.576 34.614 36.72 ;
    END
  END dq[248]
  PIN dq[249]
    DIRECTION OUTPUT ;
    USE SIGNAL ;
    PORT
      LAYER M5 ;
        RECT  34.704 36.528 34.728 36.72 ;
    END
  END dq[249]
  PIN dq[24]
    DIRECTION OUTPUT ;
    USE SIGNAL ;
    PORT
      LAYER M3 ;
        RECT  7.308 36.576 7.326 36.72 ;
    END
  END dq[24]
  PIN dq[250]
    DIRECTION OUTPUT ;
    USE SIGNAL ;
    PORT
      LAYER M3 ;
        RECT  34.848 36.576 34.866 36.72 ;
    END
  END dq[250]
  PIN dq[251]
    DIRECTION OUTPUT ;
    USE SIGNAL ;
    PORT
      LAYER M5 ;
        RECT  34.944 36.528 34.968 36.72 ;
    END
  END dq[251]
  PIN dq[252]
    DIRECTION OUTPUT ;
    USE SIGNAL ;
    PORT
      LAYER M3 ;
        RECT  35.1 36.576 35.118 36.72 ;
    END
  END dq[252]
  PIN dq[253]
    DIRECTION OUTPUT ;
    USE SIGNAL ;
    PORT
      LAYER M5 ;
        RECT  35.184 36.528 35.208 36.72 ;
    END
  END dq[253]
  PIN dq[254]
    DIRECTION OUTPUT ;
    USE SIGNAL ;
    PORT
      LAYER M3 ;
        RECT  35.316 36.576 35.334 36.72 ;
    END
  END dq[254]
  PIN dq[255]
    DIRECTION OUTPUT ;
    USE SIGNAL ;
    PORT
      LAYER M5 ;
        RECT  35.424 36.528 35.448 36.72 ;
    END
  END dq[255]
  PIN dq[256]
    DIRECTION OUTPUT ;
    USE SIGNAL ;
    PORT
      LAYER M3 ;
        RECT  35.568 36.576 35.586 36.72 ;
    END
  END dq[256]
  PIN dq[257]
    DIRECTION OUTPUT ;
    USE SIGNAL ;
    PORT
      LAYER M5 ;
        RECT  35.712 36.528 35.736 36.72 ;
    END
  END dq[257]
  PIN dq[258]
    DIRECTION OUTPUT ;
    USE SIGNAL ;
    PORT
      LAYER M3 ;
        RECT  35.82 36.576 35.838 36.72 ;
    END
  END dq[258]
  PIN dq[259]
    DIRECTION OUTPUT ;
    USE SIGNAL ;
    PORT
      LAYER M5 ;
        RECT  35.952 36.528 35.976 36.72 ;
    END
  END dq[259]
  PIN dq[25]
    DIRECTION OUTPUT ;
    USE SIGNAL ;
    PORT
      LAYER M5 ;
        RECT  7.392 36.528 7.416 36.72 ;
    END
  END dq[25]
  PIN dq[260]
    DIRECTION OUTPUT ;
    USE SIGNAL ;
    PORT
      LAYER M3 ;
        RECT  36.072 36.576 36.09 36.72 ;
    END
  END dq[260]
  PIN dq[261]
    DIRECTION OUTPUT ;
    USE SIGNAL ;
    PORT
      LAYER M5 ;
        RECT  36.192 36.528 36.216 36.72 ;
    END
  END dq[261]
  PIN dq[262]
    DIRECTION OUTPUT ;
    USE SIGNAL ;
    PORT
      LAYER M3 ;
        RECT  36.288 36.576 36.306 36.72 ;
    END
  END dq[262]
  PIN dq[263]
    DIRECTION OUTPUT ;
    USE SIGNAL ;
    PORT
      LAYER M5 ;
        RECT  36.432 36.528 36.456 36.72 ;
    END
  END dq[263]
  PIN dq[264]
    DIRECTION OUTPUT ;
    USE SIGNAL ;
    PORT
      LAYER M3 ;
        RECT  36.54 36.576 36.558 36.72 ;
    END
  END dq[264]
  PIN dq[265]
    DIRECTION OUTPUT ;
    USE SIGNAL ;
    PORT
      LAYER M5 ;
        RECT  36.672 36.528 36.696 36.72 ;
    END
  END dq[265]
  PIN dq[266]
    DIRECTION OUTPUT ;
    USE SIGNAL ;
    PORT
      LAYER M3 ;
        RECT  36.792 36.576 36.81 36.72 ;
    END
  END dq[266]
  PIN dq[267]
    DIRECTION OUTPUT ;
    USE SIGNAL ;
    PORT
      LAYER M5 ;
        RECT  36.912 36.528 36.936 36.72 ;
    END
  END dq[267]
  PIN dq[268]
    DIRECTION OUTPUT ;
    USE SIGNAL ;
    PORT
      LAYER M3 ;
        RECT  37.044 36.576 37.062 36.72 ;
    END
  END dq[268]
  PIN dq[269]
    DIRECTION OUTPUT ;
    USE SIGNAL ;
    PORT
      LAYER M5 ;
        RECT  37.152 36.528 37.176 36.72 ;
    END
  END dq[269]
  PIN dq[26]
    DIRECTION OUTPUT ;
    USE SIGNAL ;
    PORT
      LAYER M3 ;
        RECT  7.524 36.576 7.542 36.72 ;
    END
  END dq[26]
  PIN dq[270]
    DIRECTION OUTPUT ;
    USE SIGNAL ;
    PORT
      LAYER M3 ;
        RECT  37.26 36.576 37.278 36.72 ;
    END
  END dq[270]
  PIN dq[271]
    DIRECTION OUTPUT ;
    USE SIGNAL ;
    PORT
      LAYER M5 ;
        RECT  37.392 36.528 37.416 36.72 ;
    END
  END dq[271]
  PIN dq[272]
    DIRECTION OUTPUT ;
    USE SIGNAL ;
    PORT
      LAYER M3 ;
        RECT  37.512 36.576 37.53 36.72 ;
    END
  END dq[272]
  PIN dq[273]
    DIRECTION OUTPUT ;
    USE SIGNAL ;
    PORT
      LAYER M5 ;
        RECT  37.632 36.528 37.656 36.72 ;
    END
  END dq[273]
  PIN dq[274]
    DIRECTION OUTPUT ;
    USE SIGNAL ;
    PORT
      LAYER M3 ;
        RECT  37.764 36.576 37.782 36.72 ;
    END
  END dq[274]
  PIN dq[275]
    DIRECTION OUTPUT ;
    USE SIGNAL ;
    PORT
      LAYER M5 ;
        RECT  37.872 36.528 37.896 36.72 ;
    END
  END dq[275]
  PIN dq[276]
    DIRECTION OUTPUT ;
    USE SIGNAL ;
    PORT
      LAYER M3 ;
        RECT  38.016 36.576 38.034 36.72 ;
    END
  END dq[276]
  PIN dq[277]
    DIRECTION OUTPUT ;
    USE SIGNAL ;
    PORT
      LAYER M5 ;
        RECT  38.112 36.528 38.136 36.72 ;
    END
  END dq[277]
  PIN dq[278]
    DIRECTION OUTPUT ;
    USE SIGNAL ;
    PORT
      LAYER M3 ;
        RECT  38.268 36.576 38.286 36.72 ;
    END
  END dq[278]
  PIN dq[279]
    DIRECTION OUTPUT ;
    USE SIGNAL ;
    PORT
      LAYER M5 ;
        RECT  38.352 36.528 38.376 36.72 ;
    END
  END dq[279]
  PIN dq[27]
    DIRECTION OUTPUT ;
    USE SIGNAL ;
    PORT
      LAYER M5 ;
        RECT  7.68 36.528 7.704 36.72 ;
    END
  END dq[27]
  PIN dq[280]
    DIRECTION OUTPUT ;
    USE SIGNAL ;
    PORT
      LAYER M3 ;
        RECT  38.484 36.576 38.502 36.72 ;
    END
  END dq[280]
  PIN dq[281]
    DIRECTION OUTPUT ;
    USE SIGNAL ;
    PORT
      LAYER M5 ;
        RECT  38.592 36.528 38.616 36.72 ;
    END
  END dq[281]
  PIN dq[282]
    DIRECTION OUTPUT ;
    USE SIGNAL ;
    PORT
      LAYER M3 ;
        RECT  38.736 36.576 38.754 36.72 ;
    END
  END dq[282]
  PIN dq[283]
    DIRECTION OUTPUT ;
    USE SIGNAL ;
    PORT
      LAYER M5 ;
        RECT  38.88 36.528 38.904 36.72 ;
    END
  END dq[283]
  PIN dq[284]
    DIRECTION OUTPUT ;
    USE SIGNAL ;
    PORT
      LAYER M3 ;
        RECT  38.988 36.576 39.006 36.72 ;
    END
  END dq[284]
  PIN dq[285]
    DIRECTION OUTPUT ;
    USE SIGNAL ;
    PORT
      LAYER M5 ;
        RECT  39.12 36.528 39.144 36.72 ;
    END
  END dq[285]
  PIN dq[286]
    DIRECTION OUTPUT ;
    USE SIGNAL ;
    PORT
      LAYER M3 ;
        RECT  39.24 36.576 39.258 36.72 ;
    END
  END dq[286]
  PIN dq[287]
    DIRECTION OUTPUT ;
    USE SIGNAL ;
    PORT
      LAYER M5 ;
        RECT  39.36 36.528 39.384 36.72 ;
    END
  END dq[287]
  PIN dq[288]
    DIRECTION OUTPUT ;
    USE SIGNAL ;
    PORT
      LAYER M3 ;
        RECT  39.456 36.576 39.474 36.72 ;
    END
  END dq[288]
  PIN dq[289]
    DIRECTION OUTPUT ;
    USE SIGNAL ;
    PORT
      LAYER M5 ;
        RECT  39.6 36.528 39.624 36.72 ;
    END
  END dq[289]
  PIN dq[28]
    DIRECTION OUTPUT ;
    USE SIGNAL ;
    PORT
      LAYER M3 ;
        RECT  7.776 36.576 7.794 36.72 ;
    END
  END dq[28]
  PIN dq[290]
    DIRECTION OUTPUT ;
    USE SIGNAL ;
    PORT
      LAYER M3 ;
        RECT  39.708 36.576 39.726 36.72 ;
    END
  END dq[290]
  PIN dq[291]
    DIRECTION OUTPUT ;
    USE SIGNAL ;
    PORT
      LAYER M5 ;
        RECT  39.84 36.528 39.864 36.72 ;
    END
  END dq[291]
  PIN dq[292]
    DIRECTION OUTPUT ;
    USE SIGNAL ;
    PORT
      LAYER M3 ;
        RECT  39.96 36.576 39.978 36.72 ;
    END
  END dq[292]
  PIN dq[293]
    DIRECTION OUTPUT ;
    USE SIGNAL ;
    PORT
      LAYER M5 ;
        RECT  40.08 36.528 40.104 36.72 ;
    END
  END dq[293]
  PIN dq[294]
    DIRECTION OUTPUT ;
    USE SIGNAL ;
    PORT
      LAYER M3 ;
        RECT  40.212 36.576 40.23 36.72 ;
    END
  END dq[294]
  PIN dq[295]
    DIRECTION OUTPUT ;
    USE SIGNAL ;
    PORT
      LAYER M5 ;
        RECT  40.32 36.528 40.344 36.72 ;
    END
  END dq[295]
  PIN dq[296]
    DIRECTION OUTPUT ;
    USE SIGNAL ;
    PORT
      LAYER M3 ;
        RECT  40.428 36.576 40.446 36.72 ;
    END
  END dq[296]
  PIN dq[297]
    DIRECTION OUTPUT ;
    USE SIGNAL ;
    PORT
      LAYER M5 ;
        RECT  40.56 36.528 40.584 36.72 ;
    END
  END dq[297]
  PIN dq[298]
    DIRECTION OUTPUT ;
    USE SIGNAL ;
    PORT
      LAYER M3 ;
        RECT  40.68 36.576 40.698 36.72 ;
    END
  END dq[298]
  PIN dq[299]
    DIRECTION OUTPUT ;
    USE SIGNAL ;
    PORT
      LAYER M5 ;
        RECT  40.8 36.528 40.824 36.72 ;
    END
  END dq[299]
  PIN dq[29]
    DIRECTION OUTPUT ;
    USE SIGNAL ;
    PORT
      LAYER M5 ;
        RECT  7.92 36.528 7.944 36.72 ;
    END
  END dq[29]
  PIN dq[2]
    DIRECTION OUTPUT ;
    USE SIGNAL ;
    PORT
      LAYER M3 ;
        RECT  4.608 36.576 4.626 36.72 ;
    END
  END dq[2]
  PIN dq[300]
    DIRECTION OUTPUT ;
    USE SIGNAL ;
    PORT
      LAYER M3 ;
        RECT  40.932 36.576 40.95 36.72 ;
    END
  END dq[300]
  PIN dq[301]
    DIRECTION OUTPUT ;
    USE SIGNAL ;
    PORT
      LAYER M5 ;
        RECT  41.04 36.528 41.064 36.72 ;
    END
  END dq[301]
  PIN dq[302]
    DIRECTION OUTPUT ;
    USE SIGNAL ;
    PORT
      LAYER M3 ;
        RECT  41.184 36.576 41.202 36.72 ;
    END
  END dq[302]
  PIN dq[303]
    DIRECTION OUTPUT ;
    USE SIGNAL ;
    PORT
      LAYER M5 ;
        RECT  41.28 36.528 41.304 36.72 ;
    END
  END dq[303]
  PIN dq[304]
    DIRECTION OUTPUT ;
    USE SIGNAL ;
    PORT
      LAYER M3 ;
        RECT  41.436 36.576 41.454 36.72 ;
    END
  END dq[304]
  PIN dq[305]
    DIRECTION OUTPUT ;
    USE SIGNAL ;
    PORT
      LAYER M5 ;
        RECT  41.52 36.528 41.544 36.72 ;
    END
  END dq[305]
  PIN dq[306]
    DIRECTION OUTPUT ;
    USE SIGNAL ;
    PORT
      LAYER M3 ;
        RECT  41.652 36.576 41.67 36.72 ;
    END
  END dq[306]
  PIN dq[307]
    DIRECTION OUTPUT ;
    USE SIGNAL ;
    PORT
      LAYER M5 ;
        RECT  41.76 36.528 41.784 36.72 ;
    END
  END dq[307]
  PIN dq[308]
    DIRECTION OUTPUT ;
    USE SIGNAL ;
    PORT
      LAYER M3 ;
        RECT  41.904 36.576 41.922 36.72 ;
    END
  END dq[308]
  PIN dq[309]
    DIRECTION OUTPUT ;
    USE SIGNAL ;
    PORT
      LAYER M5 ;
        RECT  42.048 36.528 42.072 36.72 ;
    END
  END dq[309]
  PIN dq[30]
    DIRECTION OUTPUT ;
    USE SIGNAL ;
    PORT
      LAYER M3 ;
        RECT  8.028 36.576 8.046 36.72 ;
    END
  END dq[30]
  PIN dq[310]
    DIRECTION OUTPUT ;
    USE SIGNAL ;
    PORT
      LAYER M3 ;
        RECT  42.156 36.576 42.174 36.72 ;
    END
  END dq[310]
  PIN dq[311]
    DIRECTION OUTPUT ;
    USE SIGNAL ;
    PORT
      LAYER M5 ;
        RECT  42.288 36.528 42.312 36.72 ;
    END
  END dq[311]
  PIN dq[312]
    DIRECTION OUTPUT ;
    USE SIGNAL ;
    PORT
      LAYER M3 ;
        RECT  42.408 36.576 42.426 36.72 ;
    END
  END dq[312]
  PIN dq[313]
    DIRECTION OUTPUT ;
    USE SIGNAL ;
    PORT
      LAYER M5 ;
        RECT  42.528 36.528 42.552 36.72 ;
    END
  END dq[313]
  PIN dq[314]
    DIRECTION OUTPUT ;
    USE SIGNAL ;
    PORT
      LAYER M3 ;
        RECT  42.624 36.576 42.642 36.72 ;
    END
  END dq[314]
  PIN dq[315]
    DIRECTION OUTPUT ;
    USE SIGNAL ;
    PORT
      LAYER M5 ;
        RECT  42.768 36.528 42.792 36.72 ;
    END
  END dq[315]
  PIN dq[316]
    DIRECTION OUTPUT ;
    USE SIGNAL ;
    PORT
      LAYER M3 ;
        RECT  42.876 36.576 42.894 36.72 ;
    END
  END dq[316]
  PIN dq[317]
    DIRECTION OUTPUT ;
    USE SIGNAL ;
    PORT
      LAYER M5 ;
        RECT  43.008 36.528 43.032 36.72 ;
    END
  END dq[317]
  PIN dq[318]
    DIRECTION OUTPUT ;
    USE SIGNAL ;
    PORT
      LAYER M3 ;
        RECT  43.128 36.576 43.146 36.72 ;
    END
  END dq[318]
  PIN dq[319]
    DIRECTION OUTPUT ;
    USE SIGNAL ;
    PORT
      LAYER M5 ;
        RECT  43.248 36.528 43.272 36.72 ;
    END
  END dq[319]
  PIN dq[31]
    DIRECTION OUTPUT ;
    USE SIGNAL ;
    PORT
      LAYER M5 ;
        RECT  8.16 36.528 8.184 36.72 ;
    END
  END dq[31]
  PIN dq[320]
    DIRECTION OUTPUT ;
    USE SIGNAL ;
    PORT
      LAYER M3 ;
        RECT  43.38 36.576 43.398 36.72 ;
    END
  END dq[320]
  PIN dq[321]
    DIRECTION OUTPUT ;
    USE SIGNAL ;
    PORT
      LAYER M5 ;
        RECT  43.488 36.528 43.512 36.72 ;
    END
  END dq[321]
  PIN dq[322]
    DIRECTION OUTPUT ;
    USE SIGNAL ;
    PORT
      LAYER M3 ;
        RECT  43.596 36.576 43.614 36.72 ;
    END
  END dq[322]
  PIN dq[323]
    DIRECTION OUTPUT ;
    USE SIGNAL ;
    PORT
      LAYER M5 ;
        RECT  43.728 36.528 43.752 36.72 ;
    END
  END dq[323]
  PIN dq[324]
    DIRECTION OUTPUT ;
    USE SIGNAL ;
    PORT
      LAYER M3 ;
        RECT  43.848 36.576 43.866 36.72 ;
    END
  END dq[324]
  PIN dq[325]
    DIRECTION OUTPUT ;
    USE SIGNAL ;
    PORT
      LAYER M5 ;
        RECT  43.968 36.528 43.992 36.72 ;
    END
  END dq[325]
  PIN dq[326]
    DIRECTION OUTPUT ;
    USE SIGNAL ;
    PORT
      LAYER M3 ;
        RECT  44.1 36.576 44.118 36.72 ;
    END
  END dq[326]
  PIN dq[327]
    DIRECTION OUTPUT ;
    USE SIGNAL ;
    PORT
      LAYER M5 ;
        RECT  44.208 36.528 44.232 36.72 ;
    END
  END dq[327]
  PIN dq[328]
    DIRECTION OUTPUT ;
    USE SIGNAL ;
    PORT
      LAYER M3 ;
        RECT  44.352 36.576 44.37 36.72 ;
    END
  END dq[328]
  PIN dq[329]
    DIRECTION OUTPUT ;
    USE SIGNAL ;
    PORT
      LAYER M5 ;
        RECT  44.448 36.528 44.472 36.72 ;
    END
  END dq[329]
  PIN dq[32]
    DIRECTION OUTPUT ;
    USE SIGNAL ;
    PORT
      LAYER M3 ;
        RECT  8.28 36.576 8.298 36.72 ;
    END
  END dq[32]
  PIN dq[330]
    DIRECTION OUTPUT ;
    USE SIGNAL ;
    PORT
      LAYER M3 ;
        RECT  44.604 36.576 44.622 36.72 ;
    END
  END dq[330]
  PIN dq[331]
    DIRECTION OUTPUT ;
    USE SIGNAL ;
    PORT
      LAYER M5 ;
        RECT  44.688 36.528 44.712 36.72 ;
    END
  END dq[331]
  PIN dq[332]
    DIRECTION OUTPUT ;
    USE SIGNAL ;
    PORT
      LAYER M3 ;
        RECT  44.82 36.576 44.838 36.72 ;
    END
  END dq[332]
  PIN dq[333]
    DIRECTION OUTPUT ;
    USE SIGNAL ;
    PORT
      LAYER M5 ;
        RECT  44.928 36.528 44.952 36.72 ;
    END
  END dq[333]
  PIN dq[334]
    DIRECTION OUTPUT ;
    USE SIGNAL ;
    PORT
      LAYER M3 ;
        RECT  45.072 36.576 45.09 36.72 ;
    END
  END dq[334]
  PIN dq[335]
    DIRECTION OUTPUT ;
    USE SIGNAL ;
    PORT
      LAYER M5 ;
        RECT  45.216 36.528 45.24 36.72 ;
    END
  END dq[335]
  PIN dq[336]
    DIRECTION OUTPUT ;
    USE SIGNAL ;
    PORT
      LAYER M3 ;
        RECT  45.324 36.576 45.342 36.72 ;
    END
  END dq[336]
  PIN dq[337]
    DIRECTION OUTPUT ;
    USE SIGNAL ;
    PORT
      LAYER M5 ;
        RECT  45.456 36.528 45.48 36.72 ;
    END
  END dq[337]
  PIN dq[338]
    DIRECTION OUTPUT ;
    USE SIGNAL ;
    PORT
      LAYER M3 ;
        RECT  45.576 36.576 45.594 36.72 ;
    END
  END dq[338]
  PIN dq[339]
    DIRECTION OUTPUT ;
    USE SIGNAL ;
    PORT
      LAYER M5 ;
        RECT  45.696 36.528 45.72 36.72 ;
    END
  END dq[339]
  PIN dq[33]
    DIRECTION OUTPUT ;
    USE SIGNAL ;
    PORT
      LAYER M5 ;
        RECT  8.4 36.528 8.424 36.72 ;
    END
  END dq[33]
  PIN dq[340]
    DIRECTION OUTPUT ;
    USE SIGNAL ;
    PORT
      LAYER M3 ;
        RECT  45.792 36.576 45.81 36.72 ;
    END
  END dq[340]
  PIN dq[341]
    DIRECTION OUTPUT ;
    USE SIGNAL ;
    PORT
      LAYER M5 ;
        RECT  45.936 36.528 45.96 36.72 ;
    END
  END dq[341]
  PIN dq[342]
    DIRECTION OUTPUT ;
    USE SIGNAL ;
    PORT
      LAYER M3 ;
        RECT  46.044 36.576 46.062 36.72 ;
    END
  END dq[342]
  PIN dq[343]
    DIRECTION OUTPUT ;
    USE SIGNAL ;
    PORT
      LAYER M5 ;
        RECT  46.176 36.528 46.2 36.72 ;
    END
  END dq[343]
  PIN dq[344]
    DIRECTION OUTPUT ;
    USE SIGNAL ;
    PORT
      LAYER M3 ;
        RECT  46.296 36.576 46.314 36.72 ;
    END
  END dq[344]
  PIN dq[345]
    DIRECTION OUTPUT ;
    USE SIGNAL ;
    PORT
      LAYER M5 ;
        RECT  46.416 36.528 46.44 36.72 ;
    END
  END dq[345]
  PIN dq[346]
    DIRECTION OUTPUT ;
    USE SIGNAL ;
    PORT
      LAYER M3 ;
        RECT  46.548 36.576 46.566 36.72 ;
    END
  END dq[346]
  PIN dq[347]
    DIRECTION OUTPUT ;
    USE SIGNAL ;
    PORT
      LAYER M5 ;
        RECT  46.656 36.528 46.68 36.72 ;
    END
  END dq[347]
  PIN dq[348]
    DIRECTION OUTPUT ;
    USE SIGNAL ;
    PORT
      LAYER M3 ;
        RECT  46.764 36.576 46.782 36.72 ;
    END
  END dq[348]
  PIN dq[349]
    DIRECTION OUTPUT ;
    USE SIGNAL ;
    PORT
      LAYER M5 ;
        RECT  46.896 36.528 46.92 36.72 ;
    END
  END dq[349]
  PIN dq[34]
    DIRECTION OUTPUT ;
    USE SIGNAL ;
    PORT
      LAYER M3 ;
        RECT  8.532 36.576 8.55 36.72 ;
    END
  END dq[34]
  PIN dq[350]
    DIRECTION OUTPUT ;
    USE SIGNAL ;
    PORT
      LAYER M3 ;
        RECT  47.016 36.576 47.034 36.72 ;
    END
  END dq[350]
  PIN dq[351]
    DIRECTION OUTPUT ;
    USE SIGNAL ;
    PORT
      LAYER M5 ;
        RECT  47.136 36.528 47.16 36.72 ;
    END
  END dq[351]
  PIN dq[352]
    DIRECTION OUTPUT ;
    USE SIGNAL ;
    PORT
      LAYER M3 ;
        RECT  47.268 36.576 47.286 36.72 ;
    END
  END dq[352]
  PIN dq[353]
    DIRECTION OUTPUT ;
    USE SIGNAL ;
    PORT
      LAYER M5 ;
        RECT  47.376 36.528 47.4 36.72 ;
    END
  END dq[353]
  PIN dq[354]
    DIRECTION OUTPUT ;
    USE SIGNAL ;
    PORT
      LAYER M3 ;
        RECT  47.52 36.576 47.538 36.72 ;
    END
  END dq[354]
  PIN dq[355]
    DIRECTION OUTPUT ;
    USE SIGNAL ;
    PORT
      LAYER M5 ;
        RECT  47.616 36.528 47.64 36.72 ;
    END
  END dq[355]
  PIN dq[356]
    DIRECTION OUTPUT ;
    USE SIGNAL ;
    PORT
      LAYER M3 ;
        RECT  47.772 36.576 47.79 36.72 ;
    END
  END dq[356]
  PIN dq[357]
    DIRECTION OUTPUT ;
    USE SIGNAL ;
    PORT
      LAYER M5 ;
        RECT  47.856 36.528 47.88 36.72 ;
    END
  END dq[357]
  PIN dq[358]
    DIRECTION OUTPUT ;
    USE SIGNAL ;
    PORT
      LAYER M3 ;
        RECT  47.988 36.576 48.006 36.72 ;
    END
  END dq[358]
  PIN dq[359]
    DIRECTION OUTPUT ;
    USE SIGNAL ;
    PORT
      LAYER M5 ;
        RECT  48.096 36.528 48.12 36.72 ;
    END
  END dq[359]
  PIN dq[35]
    DIRECTION OUTPUT ;
    USE SIGNAL ;
    PORT
      LAYER M5 ;
        RECT  8.64 36.528 8.664 36.72 ;
    END
  END dq[35]
  PIN dq[360]
    DIRECTION OUTPUT ;
    USE SIGNAL ;
    PORT
      LAYER M3 ;
        RECT  48.24 36.576 48.258 36.72 ;
    END
  END dq[360]
  PIN dq[361]
    DIRECTION OUTPUT ;
    USE SIGNAL ;
    PORT
      LAYER M5 ;
        RECT  48.384 36.528 48.408 36.72 ;
    END
  END dq[361]
  PIN dq[362]
    DIRECTION OUTPUT ;
    USE SIGNAL ;
    PORT
      LAYER M3 ;
        RECT  48.492 36.576 48.51 36.72 ;
    END
  END dq[362]
  PIN dq[363]
    DIRECTION OUTPUT ;
    USE SIGNAL ;
    PORT
      LAYER M5 ;
        RECT  48.624 36.528 48.648 36.72 ;
    END
  END dq[363]
  PIN dq[364]
    DIRECTION OUTPUT ;
    USE SIGNAL ;
    PORT
      LAYER M3 ;
        RECT  48.744 36.576 48.762 36.72 ;
    END
  END dq[364]
  PIN dq[365]
    DIRECTION OUTPUT ;
    USE SIGNAL ;
    PORT
      LAYER M5 ;
        RECT  48.864 36.528 48.888 36.72 ;
    END
  END dq[365]
  PIN dq[366]
    DIRECTION OUTPUT ;
    USE SIGNAL ;
    PORT
      LAYER M3 ;
        RECT  48.96 36.576 48.978 36.72 ;
    END
  END dq[366]
  PIN dq[367]
    DIRECTION OUTPUT ;
    USE SIGNAL ;
    PORT
      LAYER M5 ;
        RECT  49.104 36.528 49.128 36.72 ;
    END
  END dq[367]
  PIN dq[368]
    DIRECTION OUTPUT ;
    USE SIGNAL ;
    PORT
      LAYER M3 ;
        RECT  49.212 36.576 49.23 36.72 ;
    END
  END dq[368]
  PIN dq[369]
    DIRECTION OUTPUT ;
    USE SIGNAL ;
    PORT
      LAYER M5 ;
        RECT  49.344 36.528 49.368 36.72 ;
    END
  END dq[369]
  PIN dq[36]
    DIRECTION OUTPUT ;
    USE SIGNAL ;
    PORT
      LAYER M3 ;
        RECT  8.748 36.576 8.766 36.72 ;
    END
  END dq[36]
  PIN dq[370]
    DIRECTION OUTPUT ;
    USE SIGNAL ;
    PORT
      LAYER M3 ;
        RECT  49.464 36.576 49.482 36.72 ;
    END
  END dq[370]
  PIN dq[371]
    DIRECTION OUTPUT ;
    USE SIGNAL ;
    PORT
      LAYER M5 ;
        RECT  49.584 36.528 49.608 36.72 ;
    END
  END dq[371]
  PIN dq[372]
    DIRECTION OUTPUT ;
    USE SIGNAL ;
    PORT
      LAYER M3 ;
        RECT  49.716 36.576 49.734 36.72 ;
    END
  END dq[372]
  PIN dq[373]
    DIRECTION OUTPUT ;
    USE SIGNAL ;
    PORT
      LAYER M5 ;
        RECT  49.824 36.528 49.848 36.72 ;
    END
  END dq[373]
  PIN dq[374]
    DIRECTION OUTPUT ;
    USE SIGNAL ;
    PORT
      LAYER M3 ;
        RECT  49.968 36.576 49.986 36.72 ;
    END
  END dq[374]
  PIN dq[375]
    DIRECTION OUTPUT ;
    USE SIGNAL ;
    PORT
      LAYER M5 ;
        RECT  50.064 36.528 50.088 36.72 ;
    END
  END dq[375]
  PIN dq[376]
    DIRECTION OUTPUT ;
    USE SIGNAL ;
    PORT
      LAYER M3 ;
        RECT  50.184 36.576 50.202 36.72 ;
    END
  END dq[376]
  PIN dq[377]
    DIRECTION OUTPUT ;
    USE SIGNAL ;
    PORT
      LAYER M5 ;
        RECT  50.304 36.528 50.328 36.72 ;
    END
  END dq[377]
  PIN dq[378]
    DIRECTION OUTPUT ;
    USE SIGNAL ;
    PORT
      LAYER M3 ;
        RECT  50.436 36.576 50.454 36.72 ;
    END
  END dq[378]
  PIN dq[379]
    DIRECTION OUTPUT ;
    USE SIGNAL ;
    PORT
      LAYER M5 ;
        RECT  50.544 36.528 50.568 36.72 ;
    END
  END dq[379]
  PIN dq[37]
    DIRECTION OUTPUT ;
    USE SIGNAL ;
    PORT
      LAYER M5 ;
        RECT  8.88 36.528 8.904 36.72 ;
    END
  END dq[37]
  PIN dq[380]
    DIRECTION OUTPUT ;
    USE SIGNAL ;
    PORT
      LAYER M3 ;
        RECT  50.688 36.576 50.706 36.72 ;
    END
  END dq[380]
  PIN dq[381]
    DIRECTION OUTPUT ;
    USE SIGNAL ;
    PORT
      LAYER M5 ;
        RECT  50.784 36.528 50.808 36.72 ;
    END
  END dq[381]
  PIN dq[382]
    DIRECTION OUTPUT ;
    USE SIGNAL ;
    PORT
      LAYER M3 ;
        RECT  50.94 36.576 50.958 36.72 ;
    END
  END dq[382]
  PIN dq[383]
    DIRECTION OUTPUT ;
    USE SIGNAL ;
    PORT
      LAYER M5 ;
        RECT  51.024 36.528 51.048 36.72 ;
    END
  END dq[383]
  PIN dq[384]
    DIRECTION OUTPUT ;
    USE SIGNAL ;
    PORT
      LAYER M3 ;
        RECT  51.156 36.576 51.174 36.72 ;
    END
  END dq[384]
  PIN dq[385]
    DIRECTION OUTPUT ;
    USE SIGNAL ;
    PORT
      LAYER M5 ;
        RECT  51.264 36.528 51.288 36.72 ;
    END
  END dq[385]
  PIN dq[386]
    DIRECTION OUTPUT ;
    USE SIGNAL ;
    PORT
      LAYER M3 ;
        RECT  51.408 36.576 51.426 36.72 ;
    END
  END dq[386]
  PIN dq[387]
    DIRECTION OUTPUT ;
    USE SIGNAL ;
    PORT
      LAYER M5 ;
        RECT  51.552 36.528 51.576 36.72 ;
    END
  END dq[387]
  PIN dq[388]
    DIRECTION OUTPUT ;
    USE SIGNAL ;
    PORT
      LAYER M3 ;
        RECT  51.66 36.576 51.678 36.72 ;
    END
  END dq[388]
  PIN dq[389]
    DIRECTION OUTPUT ;
    USE SIGNAL ;
    PORT
      LAYER M5 ;
        RECT  51.792 36.528 51.816 36.72 ;
    END
  END dq[389]
  PIN dq[38]
    DIRECTION OUTPUT ;
    USE SIGNAL ;
    PORT
      LAYER M3 ;
        RECT  9 36.576 9.018 36.72 ;
    END
  END dq[38]
  PIN dq[390]
    DIRECTION OUTPUT ;
    USE SIGNAL ;
    PORT
      LAYER M3 ;
        RECT  51.912 36.576 51.93 36.72 ;
    END
  END dq[390]
  PIN dq[391]
    DIRECTION OUTPUT ;
    USE SIGNAL ;
    PORT
      LAYER M5 ;
        RECT  52.032 36.528 52.056 36.72 ;
    END
  END dq[391]
  PIN dq[392]
    DIRECTION OUTPUT ;
    USE SIGNAL ;
    PORT
      LAYER M3 ;
        RECT  52.128 36.576 52.146 36.72 ;
    END
  END dq[392]
  PIN dq[393]
    DIRECTION OUTPUT ;
    USE SIGNAL ;
    PORT
      LAYER M5 ;
        RECT  52.272 36.528 52.296 36.72 ;
    END
  END dq[393]
  PIN dq[394]
    DIRECTION OUTPUT ;
    USE SIGNAL ;
    PORT
      LAYER M3 ;
        RECT  52.38 36.576 52.398 36.72 ;
    END
  END dq[394]
  PIN dq[395]
    DIRECTION OUTPUT ;
    USE SIGNAL ;
    PORT
      LAYER M5 ;
        RECT  52.512 36.528 52.536 36.72 ;
    END
  END dq[395]
  PIN dq[396]
    DIRECTION OUTPUT ;
    USE SIGNAL ;
    PORT
      LAYER M3 ;
        RECT  52.632 36.576 52.65 36.72 ;
    END
  END dq[396]
  PIN dq[397]
    DIRECTION OUTPUT ;
    USE SIGNAL ;
    PORT
      LAYER M5 ;
        RECT  52.752 36.528 52.776 36.72 ;
    END
  END dq[397]
  PIN dq[398]
    DIRECTION OUTPUT ;
    USE SIGNAL ;
    PORT
      LAYER M3 ;
        RECT  52.884 36.576 52.902 36.72 ;
    END
  END dq[398]
  PIN dq[399]
    DIRECTION OUTPUT ;
    USE SIGNAL ;
    PORT
      LAYER M5 ;
        RECT  52.992 36.528 53.016 36.72 ;
    END
  END dq[399]
  PIN dq[39]
    DIRECTION OUTPUT ;
    USE SIGNAL ;
    PORT
      LAYER M5 ;
        RECT  9.12 36.528 9.144 36.72 ;
    END
  END dq[39]
  PIN dq[3]
    DIRECTION OUTPUT ;
    USE SIGNAL ;
    PORT
      LAYER M5 ;
        RECT  4.752 36.528 4.776 36.72 ;
    END
  END dq[3]
  PIN dq[400]
    DIRECTION OUTPUT ;
    USE SIGNAL ;
    PORT
      LAYER M3 ;
        RECT  53.136 36.576 53.154 36.72 ;
    END
  END dq[400]
  PIN dq[401]
    DIRECTION OUTPUT ;
    USE SIGNAL ;
    PORT
      LAYER M5 ;
        RECT  53.232 36.528 53.256 36.72 ;
    END
  END dq[401]
  PIN dq[402]
    DIRECTION OUTPUT ;
    USE SIGNAL ;
    PORT
      LAYER M3 ;
        RECT  53.352 36.576 53.37 36.72 ;
    END
  END dq[402]
  PIN dq[403]
    DIRECTION OUTPUT ;
    USE SIGNAL ;
    PORT
      LAYER M5 ;
        RECT  53.472 36.528 53.496 36.72 ;
    END
  END dq[403]
  PIN dq[404]
    DIRECTION OUTPUT ;
    USE SIGNAL ;
    PORT
      LAYER M3 ;
        RECT  53.604 36.576 53.622 36.72 ;
    END
  END dq[404]
  PIN dq[405]
    DIRECTION OUTPUT ;
    USE SIGNAL ;
    PORT
      LAYER M5 ;
        RECT  53.712 36.528 53.736 36.72 ;
    END
  END dq[405]
  PIN dq[406]
    DIRECTION OUTPUT ;
    USE SIGNAL ;
    PORT
      LAYER M3 ;
        RECT  53.856 36.576 53.874 36.72 ;
    END
  END dq[406]
  PIN dq[407]
    DIRECTION OUTPUT ;
    USE SIGNAL ;
    PORT
      LAYER M5 ;
        RECT  53.952 36.528 53.976 36.72 ;
    END
  END dq[407]
  PIN dq[408]
    DIRECTION OUTPUT ;
    USE SIGNAL ;
    PORT
      LAYER M3 ;
        RECT  54.108 36.576 54.126 36.72 ;
    END
  END dq[408]
  PIN dq[409]
    DIRECTION OUTPUT ;
    USE SIGNAL ;
    PORT
      LAYER M5 ;
        RECT  54.192 36.528 54.216 36.72 ;
    END
  END dq[409]
  PIN dq[40]
    DIRECTION OUTPUT ;
    USE SIGNAL ;
    PORT
      LAYER M3 ;
        RECT  9.252 36.576 9.27 36.72 ;
    END
  END dq[40]
  PIN dq[410]
    DIRECTION OUTPUT ;
    USE SIGNAL ;
    PORT
      LAYER M3 ;
        RECT  54.324 36.576 54.342 36.72 ;
    END
  END dq[410]
  PIN dq[411]
    DIRECTION OUTPUT ;
    USE SIGNAL ;
    PORT
      LAYER M5 ;
        RECT  54.48 36.528 54.504 36.72 ;
    END
  END dq[411]
  PIN dq[412]
    DIRECTION OUTPUT ;
    USE SIGNAL ;
    PORT
      LAYER M3 ;
        RECT  54.576 36.576 54.594 36.72 ;
    END
  END dq[412]
  PIN dq[413]
    DIRECTION OUTPUT ;
    USE SIGNAL ;
    PORT
      LAYER M5 ;
        RECT  54.72 36.528 54.744 36.72 ;
    END
  END dq[413]
  PIN dq[414]
    DIRECTION OUTPUT ;
    USE SIGNAL ;
    PORT
      LAYER M3 ;
        RECT  54.828 36.576 54.846 36.72 ;
    END
  END dq[414]
  PIN dq[415]
    DIRECTION OUTPUT ;
    USE SIGNAL ;
    PORT
      LAYER M5 ;
        RECT  54.96 36.528 54.984 36.72 ;
    END
  END dq[415]
  PIN dq[416]
    DIRECTION OUTPUT ;
    USE SIGNAL ;
    PORT
      LAYER M3 ;
        RECT  55.08 36.576 55.098 36.72 ;
    END
  END dq[416]
  PIN dq[417]
    DIRECTION OUTPUT ;
    USE SIGNAL ;
    PORT
      LAYER M5 ;
        RECT  55.2 36.528 55.224 36.72 ;
    END
  END dq[417]
  PIN dq[418]
    DIRECTION OUTPUT ;
    USE SIGNAL ;
    PORT
      LAYER M3 ;
        RECT  55.296 36.576 55.314 36.72 ;
    END
  END dq[418]
  PIN dq[419]
    DIRECTION OUTPUT ;
    USE SIGNAL ;
    PORT
      LAYER M5 ;
        RECT  55.44 36.528 55.464 36.72 ;
    END
  END dq[419]
  PIN dq[41]
    DIRECTION OUTPUT ;
    USE SIGNAL ;
    PORT
      LAYER M5 ;
        RECT  9.36 36.528 9.384 36.72 ;
    END
  END dq[41]
  PIN dq[420]
    DIRECTION OUTPUT ;
    USE SIGNAL ;
    PORT
      LAYER M3 ;
        RECT  55.548 36.576 55.566 36.72 ;
    END
  END dq[420]
  PIN dq[421]
    DIRECTION OUTPUT ;
    USE SIGNAL ;
    PORT
      LAYER M5 ;
        RECT  55.68 36.528 55.704 36.72 ;
    END
  END dq[421]
  PIN dq[422]
    DIRECTION OUTPUT ;
    USE SIGNAL ;
    PORT
      LAYER M3 ;
        RECT  55.8 36.576 55.818 36.72 ;
    END
  END dq[422]
  PIN dq[423]
    DIRECTION OUTPUT ;
    USE SIGNAL ;
    PORT
      LAYER M5 ;
        RECT  55.92 36.528 55.944 36.72 ;
    END
  END dq[423]
  PIN dq[424]
    DIRECTION OUTPUT ;
    USE SIGNAL ;
    PORT
      LAYER M3 ;
        RECT  56.052 36.576 56.07 36.72 ;
    END
  END dq[424]
  PIN dq[425]
    DIRECTION OUTPUT ;
    USE SIGNAL ;
    PORT
      LAYER M5 ;
        RECT  56.16 36.528 56.184 36.72 ;
    END
  END dq[425]
  PIN dq[426]
    DIRECTION OUTPUT ;
    USE SIGNAL ;
    PORT
      LAYER M3 ;
        RECT  56.304 36.576 56.322 36.72 ;
    END
  END dq[426]
  PIN dq[427]
    DIRECTION OUTPUT ;
    USE SIGNAL ;
    PORT
      LAYER M5 ;
        RECT  56.4 36.528 56.424 36.72 ;
    END
  END dq[427]
  PIN dq[428]
    DIRECTION OUTPUT ;
    USE SIGNAL ;
    PORT
      LAYER M3 ;
        RECT  56.52 36.576 56.538 36.72 ;
    END
  END dq[428]
  PIN dq[429]
    DIRECTION OUTPUT ;
    USE SIGNAL ;
    PORT
      LAYER M5 ;
        RECT  56.64 36.528 56.664 36.72 ;
    END
  END dq[429]
  PIN dq[42]
    DIRECTION OUTPUT ;
    USE SIGNAL ;
    PORT
      LAYER M3 ;
        RECT  9.504 36.576 9.522 36.72 ;
    END
  END dq[42]
  PIN dq[430]
    DIRECTION OUTPUT ;
    USE SIGNAL ;
    PORT
      LAYER M3 ;
        RECT  56.772 36.576 56.79 36.72 ;
    END
  END dq[430]
  PIN dq[431]
    DIRECTION OUTPUT ;
    USE SIGNAL ;
    PORT
      LAYER M5 ;
        RECT  56.88 36.528 56.904 36.72 ;
    END
  END dq[431]
  PIN dq[432]
    DIRECTION OUTPUT ;
    USE SIGNAL ;
    PORT
      LAYER M3 ;
        RECT  57.024 36.576 57.042 36.72 ;
    END
  END dq[432]
  PIN dq[433]
    DIRECTION OUTPUT ;
    USE SIGNAL ;
    PORT
      LAYER M5 ;
        RECT  57.12 36.528 57.144 36.72 ;
    END
  END dq[433]
  PIN dq[434]
    DIRECTION OUTPUT ;
    USE SIGNAL ;
    PORT
      LAYER M3 ;
        RECT  57.276 36.576 57.294 36.72 ;
    END
  END dq[434]
  PIN dq[435]
    DIRECTION OUTPUT ;
    USE SIGNAL ;
    PORT
      LAYER M5 ;
        RECT  57.36 36.528 57.384 36.72 ;
    END
  END dq[435]
  PIN dq[436]
    DIRECTION OUTPUT ;
    USE SIGNAL ;
    PORT
      LAYER M3 ;
        RECT  57.492 36.576 57.51 36.72 ;
    END
  END dq[436]
  PIN dq[437]
    DIRECTION OUTPUT ;
    USE SIGNAL ;
    PORT
      LAYER M5 ;
        RECT  57.648 36.528 57.672 36.72 ;
    END
  END dq[437]
  PIN dq[438]
    DIRECTION OUTPUT ;
    USE SIGNAL ;
    PORT
      LAYER M3 ;
        RECT  57.744 36.576 57.762 36.72 ;
    END
  END dq[438]
  PIN dq[439]
    DIRECTION OUTPUT ;
    USE SIGNAL ;
    PORT
      LAYER M5 ;
        RECT  57.888 36.528 57.912 36.72 ;
    END
  END dq[439]
  PIN dq[43]
    DIRECTION OUTPUT ;
    USE SIGNAL ;
    PORT
      LAYER M5 ;
        RECT  9.6 36.528 9.624 36.72 ;
    END
  END dq[43]
  PIN dq[440]
    DIRECTION OUTPUT ;
    USE SIGNAL ;
    PORT
      LAYER M3 ;
        RECT  57.996 36.576 58.014 36.72 ;
    END
  END dq[440]
  PIN dq[441]
    DIRECTION OUTPUT ;
    USE SIGNAL ;
    PORT
      LAYER M5 ;
        RECT  58.128 36.528 58.152 36.72 ;
    END
  END dq[441]
  PIN dq[442]
    DIRECTION OUTPUT ;
    USE SIGNAL ;
    PORT
      LAYER M3 ;
        RECT  58.248 36.576 58.266 36.72 ;
    END
  END dq[442]
  PIN dq[443]
    DIRECTION OUTPUT ;
    USE SIGNAL ;
    PORT
      LAYER M5 ;
        RECT  58.368 36.528 58.392 36.72 ;
    END
  END dq[443]
  PIN dq[444]
    DIRECTION OUTPUT ;
    USE SIGNAL ;
    PORT
      LAYER M3 ;
        RECT  58.464 36.576 58.482 36.72 ;
    END
  END dq[444]
  PIN dq[445]
    DIRECTION OUTPUT ;
    USE SIGNAL ;
    PORT
      LAYER M5 ;
        RECT  58.608 36.528 58.632 36.72 ;
    END
  END dq[445]
  PIN dq[446]
    DIRECTION OUTPUT ;
    USE SIGNAL ;
    PORT
      LAYER M3 ;
        RECT  58.716 36.576 58.734 36.72 ;
    END
  END dq[446]
  PIN dq[447]
    DIRECTION OUTPUT ;
    USE SIGNAL ;
    PORT
      LAYER M5 ;
        RECT  58.848 36.528 58.872 36.72 ;
    END
  END dq[447]
  PIN dq[448]
    DIRECTION OUTPUT ;
    USE SIGNAL ;
    PORT
      LAYER M3 ;
        RECT  58.968 36.576 58.986 36.72 ;
    END
  END dq[448]
  PIN dq[449]
    DIRECTION OUTPUT ;
    USE SIGNAL ;
    PORT
      LAYER M5 ;
        RECT  59.088 36.528 59.112 36.72 ;
    END
  END dq[449]
  PIN dq[44]
    DIRECTION OUTPUT ;
    USE SIGNAL ;
    PORT
      LAYER M3 ;
        RECT  9.72 36.576 9.738 36.72 ;
    END
  END dq[44]
  PIN dq[450]
    DIRECTION OUTPUT ;
    USE SIGNAL ;
    PORT
      LAYER M3 ;
        RECT  59.22 36.576 59.238 36.72 ;
    END
  END dq[450]
  PIN dq[451]
    DIRECTION OUTPUT ;
    USE SIGNAL ;
    PORT
      LAYER M5 ;
        RECT  59.328 36.528 59.352 36.72 ;
    END
  END dq[451]
  PIN dq[452]
    DIRECTION OUTPUT ;
    USE SIGNAL ;
    PORT
      LAYER M3 ;
        RECT  59.472 36.576 59.49 36.72 ;
    END
  END dq[452]
  PIN dq[453]
    DIRECTION OUTPUT ;
    USE SIGNAL ;
    PORT
      LAYER M5 ;
        RECT  59.568 36.528 59.592 36.72 ;
    END
  END dq[453]
  PIN dq[454]
    DIRECTION OUTPUT ;
    USE SIGNAL ;
    PORT
      LAYER M3 ;
        RECT  59.688 36.576 59.706 36.72 ;
    END
  END dq[454]
  PIN dq[455]
    DIRECTION OUTPUT ;
    USE SIGNAL ;
    PORT
      LAYER M5 ;
        RECT  59.808 36.528 59.832 36.72 ;
    END
  END dq[455]
  PIN dq[456]
    DIRECTION OUTPUT ;
    USE SIGNAL ;
    PORT
      LAYER M3 ;
        RECT  59.94 36.576 59.958 36.72 ;
    END
  END dq[456]
  PIN dq[457]
    DIRECTION OUTPUT ;
    USE SIGNAL ;
    PORT
      LAYER M5 ;
        RECT  60.048 36.528 60.072 36.72 ;
    END
  END dq[457]
  PIN dq[458]
    DIRECTION OUTPUT ;
    USE SIGNAL ;
    PORT
      LAYER M3 ;
        RECT  60.192 36.576 60.21 36.72 ;
    END
  END dq[458]
  PIN dq[459]
    DIRECTION OUTPUT ;
    USE SIGNAL ;
    PORT
      LAYER M5 ;
        RECT  60.288 36.528 60.312 36.72 ;
    END
  END dq[459]
  PIN dq[45]
    DIRECTION OUTPUT ;
    USE SIGNAL ;
    PORT
      LAYER M5 ;
        RECT  9.84 36.528 9.864 36.72 ;
    END
  END dq[45]
  PIN dq[460]
    DIRECTION OUTPUT ;
    USE SIGNAL ;
    PORT
      LAYER M3 ;
        RECT  60.444 36.576 60.462 36.72 ;
    END
  END dq[460]
  PIN dq[461]
    DIRECTION OUTPUT ;
    USE SIGNAL ;
    PORT
      LAYER M5 ;
        RECT  60.528 36.528 60.552 36.72 ;
    END
  END dq[461]
  PIN dq[462]
    DIRECTION OUTPUT ;
    USE SIGNAL ;
    PORT
      LAYER M3 ;
        RECT  60.66 36.576 60.678 36.72 ;
    END
  END dq[462]
  PIN dq[463]
    DIRECTION OUTPUT ;
    USE SIGNAL ;
    PORT
      LAYER M5 ;
        RECT  60.816 36.528 60.84 36.72 ;
    END
  END dq[463]
  PIN dq[464]
    DIRECTION OUTPUT ;
    USE SIGNAL ;
    PORT
      LAYER M3 ;
        RECT  60.912 36.576 60.93 36.72 ;
    END
  END dq[464]
  PIN dq[465]
    DIRECTION OUTPUT ;
    USE SIGNAL ;
    PORT
      LAYER M5 ;
        RECT  61.056 36.528 61.08 36.72 ;
    END
  END dq[465]
  PIN dq[466]
    DIRECTION OUTPUT ;
    USE SIGNAL ;
    PORT
      LAYER M3 ;
        RECT  61.164 36.576 61.182 36.72 ;
    END
  END dq[466]
  PIN dq[467]
    DIRECTION OUTPUT ;
    USE SIGNAL ;
    PORT
      LAYER M5 ;
        RECT  61.296 36.528 61.32 36.72 ;
    END
  END dq[467]
  PIN dq[468]
    DIRECTION OUTPUT ;
    USE SIGNAL ;
    PORT
      LAYER M3 ;
        RECT  61.416 36.576 61.434 36.72 ;
    END
  END dq[468]
  PIN dq[469]
    DIRECTION OUTPUT ;
    USE SIGNAL ;
    PORT
      LAYER M5 ;
        RECT  61.536 36.528 61.56 36.72 ;
    END
  END dq[469]
  PIN dq[46]
    DIRECTION OUTPUT ;
    USE SIGNAL ;
    PORT
      LAYER M3 ;
        RECT  9.972 36.576 9.99 36.72 ;
    END
  END dq[46]
  PIN dq[470]
    DIRECTION OUTPUT ;
    USE SIGNAL ;
    PORT
      LAYER M3 ;
        RECT  61.632 36.576 61.65 36.72 ;
    END
  END dq[470]
  PIN dq[471]
    DIRECTION OUTPUT ;
    USE SIGNAL ;
    PORT
      LAYER M5 ;
        RECT  61.776 36.528 61.8 36.72 ;
    END
  END dq[471]
  PIN dq[472]
    DIRECTION OUTPUT ;
    USE SIGNAL ;
    PORT
      LAYER M3 ;
        RECT  61.884 36.576 61.902 36.72 ;
    END
  END dq[472]
  PIN dq[473]
    DIRECTION OUTPUT ;
    USE SIGNAL ;
    PORT
      LAYER M5 ;
        RECT  62.016 36.528 62.04 36.72 ;
    END
  END dq[473]
  PIN dq[474]
    DIRECTION OUTPUT ;
    USE SIGNAL ;
    PORT
      LAYER M3 ;
        RECT  62.136 36.576 62.154 36.72 ;
    END
  END dq[474]
  PIN dq[475]
    DIRECTION OUTPUT ;
    USE SIGNAL ;
    PORT
      LAYER M5 ;
        RECT  62.256 36.528 62.28 36.72 ;
    END
  END dq[475]
  PIN dq[476]
    DIRECTION OUTPUT ;
    USE SIGNAL ;
    PORT
      LAYER M3 ;
        RECT  62.388 36.576 62.406 36.72 ;
    END
  END dq[476]
  PIN dq[477]
    DIRECTION OUTPUT ;
    USE SIGNAL ;
    PORT
      LAYER M5 ;
        RECT  62.496 36.528 62.52 36.72 ;
    END
  END dq[477]
  PIN dq[478]
    DIRECTION OUTPUT ;
    USE SIGNAL ;
    PORT
      LAYER M3 ;
        RECT  62.64 36.576 62.658 36.72 ;
    END
  END dq[478]
  PIN dq[479]
    DIRECTION OUTPUT ;
    USE SIGNAL ;
    PORT
      LAYER M5 ;
        RECT  62.736 36.528 62.76 36.72 ;
    END
  END dq[479]
  PIN dq[47]
    DIRECTION OUTPUT ;
    USE SIGNAL ;
    PORT
      LAYER M5 ;
        RECT  10.08 36.528 10.104 36.72 ;
    END
  END dq[47]
  PIN dq[480]
    DIRECTION OUTPUT ;
    USE SIGNAL ;
    PORT
      LAYER M3 ;
        RECT  62.856 36.576 62.874 36.72 ;
    END
  END dq[480]
  PIN dq[481]
    DIRECTION OUTPUT ;
    USE SIGNAL ;
    PORT
      LAYER M5 ;
        RECT  62.976 36.528 63 36.72 ;
    END
  END dq[481]
  PIN dq[482]
    DIRECTION OUTPUT ;
    USE SIGNAL ;
    PORT
      LAYER M3 ;
        RECT  63.108 36.576 63.126 36.72 ;
    END
  END dq[482]
  PIN dq[483]
    DIRECTION OUTPUT ;
    USE SIGNAL ;
    PORT
      LAYER M5 ;
        RECT  63.216 36.528 63.24 36.72 ;
    END
  END dq[483]
  PIN dq[484]
    DIRECTION OUTPUT ;
    USE SIGNAL ;
    PORT
      LAYER M3 ;
        RECT  63.36 36.576 63.378 36.72 ;
    END
  END dq[484]
  PIN dq[485]
    DIRECTION OUTPUT ;
    USE SIGNAL ;
    PORT
      LAYER M5 ;
        RECT  63.456 36.528 63.48 36.72 ;
    END
  END dq[485]
  PIN dq[486]
    DIRECTION OUTPUT ;
    USE SIGNAL ;
    PORT
      LAYER M3 ;
        RECT  63.612 36.576 63.63 36.72 ;
    END
  END dq[486]
  PIN dq[487]
    DIRECTION OUTPUT ;
    USE SIGNAL ;
    PORT
      LAYER M5 ;
        RECT  63.696 36.528 63.72 36.72 ;
    END
  END dq[487]
  PIN dq[488]
    DIRECTION OUTPUT ;
    USE SIGNAL ;
    PORT
      LAYER M3 ;
        RECT  63.828 36.576 63.846 36.72 ;
    END
  END dq[488]
  PIN dq[489]
    DIRECTION OUTPUT ;
    USE SIGNAL ;
    PORT
      LAYER M5 ;
        RECT  63.984 36.528 64.008 36.72 ;
    END
  END dq[489]
  PIN dq[48]
    DIRECTION OUTPUT ;
    USE SIGNAL ;
    PORT
      LAYER M3 ;
        RECT  10.224 36.576 10.242 36.72 ;
    END
  END dq[48]
  PIN dq[490]
    DIRECTION OUTPUT ;
    USE SIGNAL ;
    PORT
      LAYER M3 ;
        RECT  64.08 36.576 64.098 36.72 ;
    END
  END dq[490]
  PIN dq[491]
    DIRECTION OUTPUT ;
    USE SIGNAL ;
    PORT
      LAYER M5 ;
        RECT  64.224 36.528 64.248 36.72 ;
    END
  END dq[491]
  PIN dq[492]
    DIRECTION OUTPUT ;
    USE SIGNAL ;
    PORT
      LAYER M3 ;
        RECT  64.332 36.576 64.35 36.72 ;
    END
  END dq[492]
  PIN dq[493]
    DIRECTION OUTPUT ;
    USE SIGNAL ;
    PORT
      LAYER M5 ;
        RECT  64.464 36.528 64.488 36.72 ;
    END
  END dq[493]
  PIN dq[494]
    DIRECTION OUTPUT ;
    USE SIGNAL ;
    PORT
      LAYER M3 ;
        RECT  64.584 36.576 64.602 36.72 ;
    END
  END dq[494]
  PIN dq[495]
    DIRECTION OUTPUT ;
    USE SIGNAL ;
    PORT
      LAYER M5 ;
        RECT  64.704 36.528 64.728 36.72 ;
    END
  END dq[495]
  PIN dq[496]
    DIRECTION OUTPUT ;
    USE SIGNAL ;
    PORT
      LAYER M3 ;
        RECT  64.836 36.576 64.854 36.72 ;
    END
  END dq[496]
  PIN dq[497]
    DIRECTION OUTPUT ;
    USE SIGNAL ;
    PORT
      LAYER M5 ;
        RECT  64.944 36.528 64.968 36.72 ;
    END
  END dq[497]
  PIN dq[498]
    DIRECTION OUTPUT ;
    USE SIGNAL ;
    PORT
      LAYER M3 ;
        RECT  65.052 36.576 65.07 36.72 ;
    END
  END dq[498]
  PIN dq[499]
    DIRECTION OUTPUT ;
    USE SIGNAL ;
    PORT
      LAYER M5 ;
        RECT  65.184 36.528 65.208 36.72 ;
    END
  END dq[499]
  PIN dq[49]
    DIRECTION OUTPUT ;
    USE SIGNAL ;
    PORT
      LAYER M5 ;
        RECT  10.32 36.528 10.344 36.72 ;
    END
  END dq[49]
  PIN dq[4]
    DIRECTION OUTPUT ;
    USE SIGNAL ;
    PORT
      LAYER M3 ;
        RECT  4.86 36.576 4.878 36.72 ;
    END
  END dq[4]
  PIN dq[500]
    DIRECTION OUTPUT ;
    USE SIGNAL ;
    PORT
      LAYER M3 ;
        RECT  65.304 36.576 65.322 36.72 ;
    END
  END dq[500]
  PIN dq[501]
    DIRECTION OUTPUT ;
    USE SIGNAL ;
    PORT
      LAYER M5 ;
        RECT  65.424 36.528 65.448 36.72 ;
    END
  END dq[501]
  PIN dq[502]
    DIRECTION OUTPUT ;
    USE SIGNAL ;
    PORT
      LAYER M3 ;
        RECT  65.556 36.576 65.574 36.72 ;
    END
  END dq[502]
  PIN dq[503]
    DIRECTION OUTPUT ;
    USE SIGNAL ;
    PORT
      LAYER M5 ;
        RECT  65.664 36.528 65.688 36.72 ;
    END
  END dq[503]
  PIN dq[504]
    DIRECTION OUTPUT ;
    USE SIGNAL ;
    PORT
      LAYER M3 ;
        RECT  65.808 36.576 65.826 36.72 ;
    END
  END dq[504]
  PIN dq[505]
    DIRECTION OUTPUT ;
    USE SIGNAL ;
    PORT
      LAYER M5 ;
        RECT  65.904 36.528 65.928 36.72 ;
    END
  END dq[505]
  PIN dq[506]
    DIRECTION OUTPUT ;
    USE SIGNAL ;
    PORT
      LAYER M3 ;
        RECT  66.024 36.576 66.042 36.72 ;
    END
  END dq[506]
  PIN dq[507]
    DIRECTION OUTPUT ;
    USE SIGNAL ;
    PORT
      LAYER M5 ;
        RECT  66.144 36.528 66.168 36.72 ;
    END
  END dq[507]
  PIN dq[508]
    DIRECTION OUTPUT ;
    USE SIGNAL ;
    PORT
      LAYER M3 ;
        RECT  66.276 36.576 66.294 36.72 ;
    END
  END dq[508]
  PIN dq[509]
    DIRECTION OUTPUT ;
    USE SIGNAL ;
    PORT
      LAYER M5 ;
        RECT  66.384 36.528 66.408 36.72 ;
    END
  END dq[509]
  PIN dq[50]
    DIRECTION OUTPUT ;
    USE SIGNAL ;
    PORT
      LAYER M3 ;
        RECT  10.476 36.576 10.494 36.72 ;
    END
  END dq[50]
  PIN dq[510]
    DIRECTION OUTPUT ;
    USE SIGNAL ;
    PORT
      LAYER M3 ;
        RECT  66.528 36.576 66.546 36.72 ;
    END
  END dq[510]
  PIN dq[511]
    DIRECTION OUTPUT ;
    USE SIGNAL ;
    PORT
      LAYER M5 ;
        RECT  66.624 36.528 66.648 36.72 ;
    END
  END dq[511]
  PIN dq[512]
    DIRECTION OUTPUT ;
    USE SIGNAL ;
    PORT
      LAYER M3 ;
        RECT  66.78 36.576 66.798 36.72 ;
    END
  END dq[512]
  PIN dq[513]
    DIRECTION OUTPUT ;
    USE SIGNAL ;
    PORT
      LAYER M5 ;
        RECT  66.864 36.528 66.888 36.72 ;
    END
  END dq[513]
  PIN dq[51]
    DIRECTION OUTPUT ;
    USE SIGNAL ;
    PORT
      LAYER M5 ;
        RECT  10.608 36.528 10.632 36.72 ;
    END
  END dq[51]
  PIN dq[52]
    DIRECTION OUTPUT ;
    USE SIGNAL ;
    PORT
      LAYER M3 ;
        RECT  10.692 36.576 10.71 36.72 ;
    END
  END dq[52]
  PIN dq[53]
    DIRECTION OUTPUT ;
    USE SIGNAL ;
    PORT
      LAYER M5 ;
        RECT  10.848 36.528 10.872 36.72 ;
    END
  END dq[53]
  PIN dq[54]
    DIRECTION OUTPUT ;
    USE SIGNAL ;
    PORT
      LAYER M3 ;
        RECT  10.944 36.576 10.962 36.72 ;
    END
  END dq[54]
  PIN dq[55]
    DIRECTION OUTPUT ;
    USE SIGNAL ;
    PORT
      LAYER M5 ;
        RECT  11.088 36.528 11.112 36.72 ;
    END
  END dq[55]
  PIN dq[56]
    DIRECTION OUTPUT ;
    USE SIGNAL ;
    PORT
      LAYER M3 ;
        RECT  11.196 36.576 11.214 36.72 ;
    END
  END dq[56]
  PIN dq[57]
    DIRECTION OUTPUT ;
    USE SIGNAL ;
    PORT
      LAYER M5 ;
        RECT  11.328 36.528 11.352 36.72 ;
    END
  END dq[57]
  PIN dq[58]
    DIRECTION OUTPUT ;
    USE SIGNAL ;
    PORT
      LAYER M3 ;
        RECT  11.448 36.576 11.466 36.72 ;
    END
  END dq[58]
  PIN dq[59]
    DIRECTION OUTPUT ;
    USE SIGNAL ;
    PORT
      LAYER M5 ;
        RECT  11.568 36.528 11.592 36.72 ;
    END
  END dq[59]
  PIN dq[5]
    DIRECTION OUTPUT ;
    USE SIGNAL ;
    PORT
      LAYER M5 ;
        RECT  4.992 36.528 5.016 36.72 ;
    END
  END dq[5]
  PIN dq[60]
    DIRECTION OUTPUT ;
    USE SIGNAL ;
    PORT
      LAYER M3 ;
        RECT  11.7 36.576 11.718 36.72 ;
    END
  END dq[60]
  PIN dq[61]
    DIRECTION OUTPUT ;
    USE SIGNAL ;
    PORT
      LAYER M5 ;
        RECT  11.808 36.528 11.832 36.72 ;
    END
  END dq[61]
  PIN dq[62]
    DIRECTION OUTPUT ;
    USE SIGNAL ;
    PORT
      LAYER M3 ;
        RECT  11.916 36.576 11.934 36.72 ;
    END
  END dq[62]
  PIN dq[63]
    DIRECTION OUTPUT ;
    USE SIGNAL ;
    PORT
      LAYER M5 ;
        RECT  12.048 36.528 12.072 36.72 ;
    END
  END dq[63]
  PIN dq[64]
    DIRECTION OUTPUT ;
    USE SIGNAL ;
    PORT
      LAYER M3 ;
        RECT  12.168 36.576 12.186 36.72 ;
    END
  END dq[64]
  PIN dq[65]
    DIRECTION OUTPUT ;
    USE SIGNAL ;
    PORT
      LAYER M5 ;
        RECT  12.288 36.528 12.312 36.72 ;
    END
  END dq[65]
  PIN dq[66]
    DIRECTION OUTPUT ;
    USE SIGNAL ;
    PORT
      LAYER M3 ;
        RECT  12.42 36.576 12.438 36.72 ;
    END
  END dq[66]
  PIN dq[67]
    DIRECTION OUTPUT ;
    USE SIGNAL ;
    PORT
      LAYER M5 ;
        RECT  12.528 36.528 12.552 36.72 ;
    END
  END dq[67]
  PIN dq[68]
    DIRECTION OUTPUT ;
    USE SIGNAL ;
    PORT
      LAYER M3 ;
        RECT  12.672 36.576 12.69 36.72 ;
    END
  END dq[68]
  PIN dq[69]
    DIRECTION OUTPUT ;
    USE SIGNAL ;
    PORT
      LAYER M5 ;
        RECT  12.768 36.528 12.792 36.72 ;
    END
  END dq[69]
  PIN dq[6]
    DIRECTION OUTPUT ;
    USE SIGNAL ;
    PORT
      LAYER M3 ;
        RECT  5.112 36.576 5.13 36.72 ;
    END
  END dq[6]
  PIN dq[70]
    DIRECTION OUTPUT ;
    USE SIGNAL ;
    PORT
      LAYER M3 ;
        RECT  12.888 36.576 12.906 36.72 ;
    END
  END dq[70]
  PIN dq[71]
    DIRECTION OUTPUT ;
    USE SIGNAL ;
    PORT
      LAYER M5 ;
        RECT  13.008 36.528 13.032 36.72 ;
    END
  END dq[71]
  PIN dq[72]
    DIRECTION OUTPUT ;
    USE SIGNAL ;
    PORT
      LAYER M3 ;
        RECT  13.14 36.576 13.158 36.72 ;
    END
  END dq[72]
  PIN dq[73]
    DIRECTION OUTPUT ;
    USE SIGNAL ;
    PORT
      LAYER M5 ;
        RECT  13.248 36.528 13.272 36.72 ;
    END
  END dq[73]
  PIN dq[74]
    DIRECTION OUTPUT ;
    USE SIGNAL ;
    PORT
      LAYER M3 ;
        RECT  13.392 36.576 13.41 36.72 ;
    END
  END dq[74]
  PIN dq[75]
    DIRECTION OUTPUT ;
    USE SIGNAL ;
    PORT
      LAYER M5 ;
        RECT  13.488 36.528 13.512 36.72 ;
    END
  END dq[75]
  PIN dq[76]
    DIRECTION OUTPUT ;
    USE SIGNAL ;
    PORT
      LAYER M3 ;
        RECT  13.644 36.576 13.662 36.72 ;
    END
  END dq[76]
  PIN dq[77]
    DIRECTION OUTPUT ;
    USE SIGNAL ;
    PORT
      LAYER M5 ;
        RECT  13.776 36.528 13.8 36.72 ;
    END
  END dq[77]
  PIN dq[78]
    DIRECTION OUTPUT ;
    USE SIGNAL ;
    PORT
      LAYER M3 ;
        RECT  13.86 36.576 13.878 36.72 ;
    END
  END dq[78]
  PIN dq[79]
    DIRECTION OUTPUT ;
    USE SIGNAL ;
    PORT
      LAYER M5 ;
        RECT  14.016 36.528 14.04 36.72 ;
    END
  END dq[79]
  PIN dq[7]
    DIRECTION OUTPUT ;
    USE SIGNAL ;
    PORT
      LAYER M5 ;
        RECT  5.232 36.528 5.256 36.72 ;
    END
  END dq[7]
  PIN dq[80]
    DIRECTION OUTPUT ;
    USE SIGNAL ;
    PORT
      LAYER M3 ;
        RECT  14.112 36.576 14.13 36.72 ;
    END
  END dq[80]
  PIN dq[81]
    DIRECTION OUTPUT ;
    USE SIGNAL ;
    PORT
      LAYER M5 ;
        RECT  14.256 36.528 14.28 36.72 ;
    END
  END dq[81]
  PIN dq[82]
    DIRECTION OUTPUT ;
    USE SIGNAL ;
    PORT
      LAYER M3 ;
        RECT  14.364 36.576 14.382 36.72 ;
    END
  END dq[82]
  PIN dq[83]
    DIRECTION OUTPUT ;
    USE SIGNAL ;
    PORT
      LAYER M5 ;
        RECT  14.496 36.528 14.52 36.72 ;
    END
  END dq[83]
  PIN dq[84]
    DIRECTION OUTPUT ;
    USE SIGNAL ;
    PORT
      LAYER M3 ;
        RECT  14.616 36.576 14.634 36.72 ;
    END
  END dq[84]
  PIN dq[85]
    DIRECTION OUTPUT ;
    USE SIGNAL ;
    PORT
      LAYER M5 ;
        RECT  14.736 36.528 14.76 36.72 ;
    END
  END dq[85]
  PIN dq[86]
    DIRECTION OUTPUT ;
    USE SIGNAL ;
    PORT
      LAYER M3 ;
        RECT  14.868 36.576 14.886 36.72 ;
    END
  END dq[86]
  PIN dq[87]
    DIRECTION OUTPUT ;
    USE SIGNAL ;
    PORT
      LAYER M5 ;
        RECT  14.976 36.528 15 36.72 ;
    END
  END dq[87]
  PIN dq[88]
    DIRECTION OUTPUT ;
    USE SIGNAL ;
    PORT
      LAYER M3 ;
        RECT  15.084 36.576 15.102 36.72 ;
    END
  END dq[88]
  PIN dq[89]
    DIRECTION OUTPUT ;
    USE SIGNAL ;
    PORT
      LAYER M5 ;
        RECT  15.216 36.528 15.24 36.72 ;
    END
  END dq[89]
  PIN dq[8]
    DIRECTION OUTPUT ;
    USE SIGNAL ;
    PORT
      LAYER M3 ;
        RECT  5.364 36.576 5.382 36.72 ;
    END
  END dq[8]
  PIN dq[90]
    DIRECTION OUTPUT ;
    USE SIGNAL ;
    PORT
      LAYER M3 ;
        RECT  15.336 36.576 15.354 36.72 ;
    END
  END dq[90]
  PIN dq[91]
    DIRECTION OUTPUT ;
    USE SIGNAL ;
    PORT
      LAYER M5 ;
        RECT  15.456 36.528 15.48 36.72 ;
    END
  END dq[91]
  PIN dq[92]
    DIRECTION OUTPUT ;
    USE SIGNAL ;
    PORT
      LAYER M3 ;
        RECT  15.588 36.576 15.606 36.72 ;
    END
  END dq[92]
  PIN dq[93]
    DIRECTION OUTPUT ;
    USE SIGNAL ;
    PORT
      LAYER M5 ;
        RECT  15.696 36.528 15.72 36.72 ;
    END
  END dq[93]
  PIN dq[94]
    DIRECTION OUTPUT ;
    USE SIGNAL ;
    PORT
      LAYER M3 ;
        RECT  15.84 36.576 15.858 36.72 ;
    END
  END dq[94]
  PIN dq[95]
    DIRECTION OUTPUT ;
    USE SIGNAL ;
    PORT
      LAYER M5 ;
        RECT  15.936 36.528 15.96 36.72 ;
    END
  END dq[95]
  PIN dq[96]
    DIRECTION OUTPUT ;
    USE SIGNAL ;
    PORT
      LAYER M3 ;
        RECT  16.056 36.576 16.074 36.72 ;
    END
  END dq[96]
  PIN dq[97]
    DIRECTION OUTPUT ;
    USE SIGNAL ;
    PORT
      LAYER M5 ;
        RECT  16.176 36.528 16.2 36.72 ;
    END
  END dq[97]
  PIN dq[98]
    DIRECTION OUTPUT ;
    USE SIGNAL ;
    PORT
      LAYER M3 ;
        RECT  16.308 36.576 16.326 36.72 ;
    END
  END dq[98]
  PIN dq[99]
    DIRECTION OUTPUT ;
    USE SIGNAL ;
    PORT
      LAYER M5 ;
        RECT  16.416 36.528 16.44 36.72 ;
    END
  END dq[99]
  PIN dq[9]
    DIRECTION OUTPUT ;
    USE SIGNAL ;
    PORT
      LAYER M5 ;
        RECT  5.472 36.528 5.496 36.72 ;
    END
  END dq[9]
  PIN VDD
    DIRECTION INOUT ;
    USE POWER ;
    PORT
      LAYER M5 ;
        RECT  67.392 2.151 67.512 34.569 ;
        RECT  64.692 2.151 64.812 34.569 ;
        RECT  61.992 2.151 62.112 34.569 ;
        RECT  59.292 2.151 59.412 34.569 ;
        RECT  56.592 2.151 56.712 34.569 ;
        RECT  53.892 2.151 54.012 34.569 ;
        RECT  51.192 2.151 51.312 34.569 ;
        RECT  48.492 2.151 48.612 34.569 ;
        RECT  45.792 2.151 45.912 34.569 ;
        RECT  43.092 2.151 43.212 34.569 ;
        RECT  40.392 2.151 40.512 34.569 ;
        RECT  37.692 2.151 37.812 34.569 ;
        RECT  34.992 2.151 35.112 34.569 ;
        RECT  32.292 2.151 32.412 34.569 ;
        RECT  29.592 2.151 29.712 34.569 ;
        RECT  26.892 2.151 27.012 34.569 ;
        RECT  24.192 2.151 24.312 34.569 ;
        RECT  21.492 2.151 21.612 34.569 ;
        RECT  18.792 2.151 18.912 34.569 ;
        RECT  16.092 2.151 16.212 34.569 ;
        RECT  13.392 2.151 13.512 34.569 ;
        RECT  10.692 2.151 10.812 34.569 ;
        RECT  7.992 2.151 8.112 34.569 ;
        RECT  5.292 2.151 5.412 34.569 ;
        RECT  2.592 2.151 2.712 34.569 ;
    END
  END VDD
  PIN VSS
    DIRECTION INOUT ;
    USE GROUND ;
    PORT
      LAYER M5 ;
        RECT  67.2 2.137 67.32 34.583 ;
        RECT  64.5 2.137 64.62 34.583 ;
        RECT  61.8 2.137 61.92 34.583 ;
        RECT  59.1 2.137 59.22 34.583 ;
        RECT  56.4 2.137 56.52 34.583 ;
        RECT  53.7 2.137 53.82 34.583 ;
        RECT  51 2.137 51.12 34.583 ;
        RECT  48.3 2.137 48.42 34.583 ;
        RECT  45.6 2.137 45.72 34.583 ;
        RECT  42.9 2.137 43.02 34.583 ;
        RECT  40.2 2.137 40.32 34.583 ;
        RECT  37.5 2.137 37.62 34.583 ;
        RECT  34.8 2.137 34.92 34.583 ;
        RECT  32.1 2.137 32.22 34.583 ;
        RECT  29.4 2.137 29.52 34.583 ;
        RECT  26.7 2.137 26.82 34.583 ;
        RECT  24 2.137 24.12 34.583 ;
        RECT  21.3 2.137 21.42 34.583 ;
        RECT  18.6 2.137 18.72 34.583 ;
        RECT  15.9 2.137 16.02 34.583 ;
        RECT  13.2 2.137 13.32 34.583 ;
        RECT  10.5 2.137 10.62 34.583 ;
        RECT  7.8 2.137 7.92 34.583 ;
        RECT  5.1 2.137 5.22 34.583 ;
        RECT  2.4 2.137 2.52 34.583 ;
    END
  END VSS
  # OT_OBS_CLOSED layer=M5 d_um=1.536 added=91
  OBS
    LAYER RVTN ;
     RECT  2.16 2.16 69.12 2.295 ;
     RECT  2.16 2.565 69.12 2.835 ;
     RECT  2.16 3.105 69.12 3.375 ;
     RECT  2.16 3.645 69.12 3.915 ;
     RECT  2.16 4.185 69.12 4.455 ;
     RECT  2.16 4.725 69.12 4.995 ;
     RECT  2.16 5.265 69.12 5.535 ;
     RECT  2.16 5.805 69.12 6.075 ;
     RECT  2.16 6.345 69.12 6.615 ;
     RECT  2.16 6.885 69.12 7.155 ;
     RECT  2.16 7.425 69.12 7.695 ;
     RECT  2.16 7.965 69.12 8.235 ;
     RECT  2.16 8.505 69.12 8.775 ;
     RECT  2.16 9.045 69.12 9.315 ;
     RECT  2.16 9.585 69.12 9.855 ;
     RECT  2.16 10.125 69.12 10.395 ;
     RECT  2.16 10.665 69.12 10.935 ;
     RECT  2.16 11.205 69.12 11.475 ;
     RECT  2.16 11.745 69.12 12.015 ;
     RECT  2.16 12.285 69.12 12.555 ;
     RECT  2.16 12.825 69.12 13.095 ;
     RECT  2.16 13.365 69.12 13.635 ;
     RECT  2.16 13.905 69.12 14.175 ;
     RECT  2.16 14.445 69.12 14.715 ;
     RECT  2.16 14.985 69.12 15.255 ;
     RECT  2.16 15.525 69.12 15.795 ;
     RECT  2.16 16.065 69.12 16.335 ;
     RECT  2.16 16.605 69.12 16.875 ;
     RECT  2.16 17.145 69.12 17.415 ;
     RECT  2.16 17.685 69.12 17.955 ;
     RECT  2.16 18.225 69.12 18.495 ;
     RECT  2.16 18.765 69.12 19.035 ;
     RECT  2.16 19.305 69.12 19.575 ;
     RECT  2.16 19.845 69.12 20.115 ;
     RECT  2.16 20.385 69.12 20.655 ;
     RECT  2.16 20.925 69.12 21.195 ;
     RECT  2.16 21.465 69.12 21.735 ;
     RECT  2.16 22.005 69.12 22.275 ;
     RECT  2.16 22.545 69.12 22.815 ;
     RECT  2.16 23.085 69.12 23.355 ;
     RECT  2.16 23.625 69.12 23.895 ;
     RECT  2.16 24.165 69.12 24.435 ;
     RECT  2.16 24.705 69.12 24.975 ;
     RECT  2.16 25.245 69.12 25.515 ;
     RECT  2.16 25.785 69.12 26.055 ;
     RECT  2.16 26.325 69.12 26.595 ;
     RECT  2.16 26.865 69.12 27.135 ;
     RECT  2.16 27.405 69.12 27.675 ;
     RECT  2.16 27.945 69.12 28.215 ;
     RECT  2.16 28.485 69.12 28.755 ;
     RECT  2.16 29.025 69.12 29.295 ;
     RECT  2.16 29.565 69.12 29.835 ;
     RECT  2.16 30.105 69.12 30.375 ;
     RECT  2.16 30.645 69.12 30.915 ;
     RECT  2.16 31.185 69.12 31.455 ;
     RECT  2.16 31.725 69.12 31.995 ;
     RECT  2.16 32.265 69.12 32.535 ;
     RECT  2.16 32.805 69.12 33.075 ;
     RECT  2.16 33.345 69.12 33.615 ;
     RECT  2.16 33.885 69.12 34.155 ;
     RECT  2.16 34.425 69.12 34.56 ;
    LAYER RVTP ;
     RECT  2.16 2.295 69.12 2.565 ;
     RECT  2.16 2.835 69.12 3.105 ;
     RECT  2.16 3.375 69.12 3.645 ;
     RECT  2.16 3.915 69.12 4.185 ;
     RECT  2.16 4.455 69.12 4.725 ;
     RECT  2.16 4.995 69.12 5.265 ;
     RECT  2.16 5.535 69.12 5.805 ;
     RECT  2.16 6.075 69.12 6.345 ;
     RECT  2.16 6.615 69.12 6.885 ;
     RECT  2.16 7.155 69.12 7.425 ;
     RECT  2.16 7.695 69.12 7.965 ;
     RECT  2.16 8.235 69.12 8.505 ;
     RECT  2.16 8.775 69.12 9.045 ;
     RECT  2.16 9.315 69.12 9.585 ;
     RECT  2.16 9.855 69.12 10.125 ;
     RECT  2.16 10.395 69.12 10.665 ;
     RECT  2.16 10.935 69.12 11.205 ;
     RECT  2.16 11.475 69.12 11.745 ;
     RECT  2.16 12.015 69.12 12.285 ;
     RECT  2.16 12.555 69.12 12.825 ;
     RECT  2.16 13.095 69.12 13.365 ;
     RECT  2.16 13.635 69.12 13.905 ;
     RECT  2.16 14.175 69.12 14.445 ;
     RECT  2.16 14.715 69.12 14.985 ;
     RECT  2.16 15.255 69.12 15.525 ;
     RECT  2.16 15.795 69.12 16.065 ;
     RECT  2.16 16.335 69.12 16.605 ;
     RECT  2.16 16.875 69.12 17.145 ;
     RECT  2.16 17.415 69.12 17.685 ;
     RECT  2.16 17.955 69.12 18.225 ;
     RECT  2.16 18.495 69.12 18.765 ;
     RECT  2.16 19.035 69.12 19.305 ;
     RECT  2.16 19.575 69.12 19.845 ;
     RECT  2.16 20.115 69.12 20.385 ;
     RECT  2.16 20.655 69.12 20.925 ;
     RECT  2.16 21.195 69.12 21.465 ;
     RECT  2.16 21.735 69.12 22.005 ;
     RECT  2.16 22.275 69.12 22.545 ;
     RECT  2.16 22.815 69.12 23.085 ;
     RECT  2.16 23.355 69.12 23.625 ;
     RECT  2.16 23.895 69.12 24.165 ;
     RECT  2.16 24.435 69.12 24.705 ;
     RECT  2.16 24.975 69.12 25.245 ;
     RECT  2.16 25.515 69.12 25.785 ;
     RECT  2.16 26.055 69.12 26.325 ;
     RECT  2.16 26.595 69.12 26.865 ;
     RECT  2.16 27.135 69.12 27.405 ;
     RECT  2.16 27.675 69.12 27.945 ;
     RECT  2.16 28.215 69.12 28.485 ;
     RECT  2.16 28.755 69.12 29.025 ;
     RECT  2.16 29.295 69.12 29.565 ;
     RECT  2.16 29.835 69.12 30.105 ;
     RECT  2.16 30.375 69.12 30.645 ;
     RECT  2.16 30.915 69.12 31.185 ;
     RECT  2.16 31.455 69.12 31.725 ;
     RECT  2.16 31.995 69.12 32.265 ;
     RECT  2.16 32.535 69.12 32.805 ;
     RECT  2.16 33.075 69.12 33.345 ;
     RECT  2.16 33.615 69.12 33.885 ;
     RECT  2.16 34.155 69.12 34.425 ;
    LAYER M1 ;
     RECT  2.16 2.151 69.12 34.569 ;
    LAYER M2 ;
     RECT  2.16 2.151 3.703 34.569 ;
     RECT  3.703 2.106 4.171 34.569 ;
     RECT  4.171 2.106 4.999 34.794 ;
     RECT  4.999 1.728 5.135 34.794 ;
     RECT  5.359 0.144 5.531 0.162 ;
     RECT  6.079 35.901 6.539 35.919 ;
     RECT  6.691 0.144 8.159 0.162 ;
     RECT  8.995 0.144 9.095 0.162 ;
     RECT  9.967 36.558 10.003 36.576 ;
     RECT  10.003 36.558 10.103 36.648 ;
     RECT  5.135 2.151 10.363 34.569 ;
     RECT  10.363 1.53 10.715 34.569 ;
     RECT  11.839 0.144 11.939 0.162 ;
     RECT  11.695 35.901 12.119 35.919 ;
     RECT  10.715 2.151 12.415 34.569 ;
     RECT  12.415 1.728 12.523 34.569 ;
     RECT  12.523 1.152 12.623 34.569 ;
     RECT  12.623 1.152 12.911 1.17 ;
     RECT  13.135 36.558 13.171 36.576 ;
     RECT  13.171 36.558 13.271 36.648 ;
     RECT  12.623 2.151 13.387 34.569 ;
     RECT  13.387 2.151 13.631 34.794 ;
     RECT  13.639 35.901 13.955 35.919 ;
     RECT  13.171 0.144 14.495 0.162 ;
     RECT  13.631 2.151 14.863 34.758 ;
     RECT  14.863 1.152 14.963 1.17 ;
     RECT  15.223 36.558 15.323 36.648 ;
     RECT  15.259 0.144 15.359 0.162 ;
     RECT  15.323 36.558 15.359 36.576 ;
     RECT  14.863 2.151 15.395 34.794 ;
     RECT  15.395 2.151 16.555 34.758 ;
     RECT  16.555 2.151 17.051 34.794 ;
     RECT  17.051 2.151 17.059 34.569 ;
     RECT  17.059 35.901 17.411 35.919 ;
     RECT  17.059 1.728 17.663 34.569 ;
     RECT  17.663 2.151 17.779 34.569 ;
     RECT  17.779 2.151 18.499 34.794 ;
     RECT  18.499 1.728 18.571 34.794 ;
     RECT  18.571 1.728 18.779 34.884 ;
     RECT  18.779 1.728 19.103 34.758 ;
     RECT  19.103 1.728 19.499 34.569 ;
     RECT  19.471 0.144 20.075 0.162 ;
     RECT  21.415 36.558 21.451 36.576 ;
     RECT  21.451 36.558 21.551 36.648 ;
     RECT  21.415 0.144 21.659 0.162 ;
     RECT  19.499 2.151 21.667 34.569 ;
     RECT  21.667 2.151 23.143 34.794 ;
     RECT  23.143 2.151 23.315 34.884 ;
     RECT  24.115 36.558 24.151 36.576 ;
     RECT  24.151 36.558 24.251 36.648 ;
     RECT  23.791 0.144 24.359 0.162 ;
     RECT  23.315 2.151 25.087 34.569 ;
     RECT  25.087 2.151 25.475 34.794 ;
     RECT  25.987 0.144 26.087 0.162 ;
     RECT  25.475 2.151 26.779 34.569 ;
     RECT  26.779 2.151 27.643 34.794 ;
     RECT  27.643 2.151 27.779 34.839 ;
     RECT  26.779 0.576 27.959 0.594 ;
     RECT  27.779 2.151 28.723 34.569 ;
     RECT  28.723 2.151 28.975 34.794 ;
     RECT  28.975 2.151 29.075 34.884 ;
     RECT  29.479 35.901 29.939 35.919 ;
     RECT  29.075 2.151 30.451 34.569 ;
     RECT  30.451 2.151 30.623 34.794 ;
     RECT  29.371 0.144 30.731 0.162 ;
     RECT  30.623 2.151 31.171 34.569 ;
     RECT  31.171 1.728 31.927 34.569 ;
     RECT  31.927 1.728 32.071 34.758 ;
     RECT  32.071 1.728 32.423 34.839 ;
     RECT  32.423 1.728 32.927 34.794 ;
     RECT  31.675 0.144 32.999 0.162 ;
     RECT  32.927 2.151 33.367 34.794 ;
     RECT  33.367 2.151 33.575 34.839 ;
     RECT  33.575 2.151 34.771 34.569 ;
     RECT  34.591 0.144 34.871 0.162 ;
     RECT  34.771 2.151 35.095 34.839 ;
     RECT  35.095 1.728 35.123 34.839 ;
     RECT  35.123 1.728 35.231 34.794 ;
     RECT  35.231 1.728 35.375 34.569 ;
     RECT  35.375 1.8 35.627 34.569 ;
     RECT  35.627 2.151 36.067 34.569 ;
     RECT  36.067 2.151 36.491 34.794 ;
     RECT  36.491 2.151 37.327 34.569 ;
     RECT  37.327 2.151 37.507 34.65 ;
     RECT  37.507 1.728 37.535 34.65 ;
     RECT  37.535 1.728 37.679 34.569 ;
     RECT  37.759 0.144 37.895 0.162 ;
     RECT  37.679 2.106 39.299 34.569 ;
     RECT  39.703 0.144 39.839 0.162 ;
     RECT  39.299 2.151 40.099 34.569 ;
     RECT  40.099 2.151 40.207 34.65 ;
     RECT  40.207 1.728 40.235 34.65 ;
     RECT  40.235 1.728 40.675 34.569 ;
     RECT  40.675 1.152 40.775 34.569 ;
     RECT  40.675 35.982 40.883 36 ;
     RECT  40.775 1.728 41.243 34.569 ;
     RECT  42.871 1.152 43.079 1.17 ;
     RECT  41.243 2.151 43.123 34.569 ;
     RECT  43.123 1.728 43.403 34.569 ;
     RECT  43.375 0.144 43.799 0.162 ;
     RECT  44.815 35.901 45.167 35.919 ;
     RECT  43.403 2.151 45.571 34.569 ;
     RECT  45.571 1.728 45.779 34.569 ;
     RECT  45.787 0.144 46.175 0.162 ;
     RECT  45.779 2.106 46.895 34.569 ;
     RECT  47.659 0.144 48.659 0.162 ;
     RECT  46.895 2.151 49.963 34.569 ;
     RECT  49.963 2.151 50.431 34.794 ;
     RECT  50.431 2.151 50.603 34.839 ;
     RECT  50.603 2.151 50.963 34.794 ;
     RECT  50.963 2.151 51.907 34.569 ;
     RECT  51.907 2.151 52.123 34.794 ;
     RECT  52.123 2.151 52.403 34.839 ;
     RECT  52.627 0.144 52.727 0.162 ;
     RECT  52.375 35.901 52.727 35.919 ;
     RECT  52.403 2.151 53.519 34.758 ;
     RECT  53.519 2.151 54.823 34.569 ;
     RECT  54.823 2.151 55.543 34.794 ;
     RECT  55.543 2.151 55.679 34.884 ;
     RECT  56.515 36.558 56.551 36.576 ;
     RECT  55.679 2.151 56.767 34.569 ;
     RECT  56.767 1.728 57.047 34.569 ;
     RECT  56.551 36.558 57.155 36.648 ;
     RECT  57.019 0.144 57.515 0.162 ;
     RECT  57.047 2.151 57.739 34.569 ;
     RECT  57.739 2.151 58.091 34.794 ;
     RECT  58.091 2.151 58.927 34.758 ;
     RECT  59.071 0.144 59.243 0.162 ;
     RECT  58.927 2.151 59.243 34.839 ;
     RECT  59.683 36.558 59.719 36.576 ;
     RECT  59.719 36.558 59.819 36.648 ;
     RECT  60.187 0.144 60.287 0.162 ;
     RECT  59.243 2.151 60.791 34.794 ;
     RECT  60.791 2.151 60.907 34.569 ;
     RECT  60.907 1.728 61.367 34.569 ;
     RECT  61.367 2.151 61.627 34.569 ;
     RECT  61.879 0.144 61.979 0.162 ;
     RECT  61.627 2.151 62.383 34.794 ;
     RECT  62.383 2.151 62.519 34.839 ;
     RECT  62.519 2.151 62.635 34.794 ;
     RECT  62.635 1.728 63.167 34.794 ;
     RECT  63.167 2.151 63.563 34.794 ;
     RECT  63.563 2.151 63.635 34.758 ;
     RECT  63.607 35.901 64.031 35.919 ;
     RECT  63.635 2.151 64.579 34.569 ;
     RECT  64.579 0.306 64.831 0.324 ;
     RECT  64.831 0.144 64.859 0.324 ;
     RECT  64.859 0.144 64.967 0.162 ;
     RECT  64.579 2.151 65.399 34.794 ;
     RECT  64.831 35.901 66.407 35.919 ;
     RECT  65.399 2.151 66.775 34.569 ;
     RECT  66.775 2.106 67.127 34.794 ;
     RECT  67.127 2.106 68.027 34.569 ;
     RECT  68.027 2.151 69.12 34.569 ;
    LAYER M3 ;
     RECT  4.374 0.108 4.608 0.144 ;
     RECT  4.626 0.108 4.86 0.144 ;
     RECT  4.878 0.108 5.112 0.144 ;
     RECT  5.13 0.108 5.364 0.144 ;
     RECT  5.382 0.108 5.58 0.144 ;
     RECT  5.598 0.108 5.832 0.144 ;
     RECT  5.85 0.108 6.084 0.144 ;
     RECT  6.102 0.108 6.336 0.144 ;
     RECT  6.354 0.108 6.552 0.144 ;
     RECT  6.57 0.108 6.804 0.144 ;
     RECT  6.822 0.108 7.056 0.144 ;
     RECT  7.074 0.108 7.308 0.144 ;
     RECT  7.326 0.108 7.524 0.144 ;
     RECT  7.542 0.108 7.776 0.144 ;
     RECT  7.794 0.108 8.028 0.144 ;
     RECT  8.046 0.108 8.28 0.144 ;
     RECT  8.298 0.108 8.532 0.144 ;
     RECT  8.55 0.108 8.748 0.144 ;
     RECT  8.766 0.108 9 0.144 ;
     RECT  9.018 0.108 9.252 0.144 ;
     RECT  9.27 0.108 9.504 0.144 ;
     RECT  9.522 0.108 9.72 0.144 ;
     RECT  9.738 0.108 9.972 0.144 ;
     RECT  9.99 0.108 10.224 0.144 ;
     RECT  10.242 0.108 10.476 0.144 ;
     RECT  10.494 0.108 10.692 0.144 ;
     RECT  10.71 0.108 10.944 0.144 ;
     RECT  10.962 0.108 11.196 0.144 ;
     RECT  11.214 0.108 11.448 0.144 ;
     RECT  11.466 0.108 11.7 0.144 ;
     RECT  11.718 0.108 11.916 0.144 ;
     RECT  11.934 0.108 12.168 0.144 ;
     RECT  12.186 0.108 12.42 0.144 ;
     RECT  12.438 0.108 12.672 0.144 ;
     RECT  12.69 0.108 12.888 0.144 ;
     RECT  12.906 0.108 13.14 0.144 ;
     RECT  13.158 0.108 13.392 0.144 ;
     RECT  13.41 0.108 13.644 0.144 ;
     RECT  13.662 0.108 13.86 0.144 ;
     RECT  13.878 0.108 14.112 0.144 ;
     RECT  14.13 0.108 14.364 0.144 ;
     RECT  14.382 0.108 14.616 0.144 ;
     RECT  14.634 0.108 14.868 0.144 ;
     RECT  14.886 0.108 15.084 0.144 ;
     RECT  15.102 0.108 15.336 0.144 ;
     RECT  15.354 0.108 15.588 0.144 ;
     RECT  15.606 0.108 15.84 0.144 ;
     RECT  15.858 0.108 16.056 0.144 ;
     RECT  16.074 0.108 16.308 0.144 ;
     RECT  16.326 0.108 16.56 0.144 ;
     RECT  16.578 0.108 16.812 0.144 ;
     RECT  16.83 0.108 17.064 0.144 ;
     RECT  17.082 0.108 17.28 0.144 ;
     RECT  17.298 0.108 17.532 0.144 ;
     RECT  17.55 0.108 17.784 0.144 ;
     RECT  17.802 0.108 18.036 0.144 ;
     RECT  18.054 0.108 18.252 0.144 ;
     RECT  18.27 0.108 18.504 0.144 ;
     RECT  18.522 0.108 18.756 0.144 ;
     RECT  18.774 0.108 19.008 0.144 ;
     RECT  19.026 0.108 19.224 0.144 ;
     RECT  19.242 0.108 19.476 0.144 ;
     RECT  19.494 0.108 19.728 0.144 ;
     RECT  19.746 0.108 19.98 0.144 ;
     RECT  19.998 0.108 20.232 0.144 ;
     RECT  20.25 0.108 20.448 0.144 ;
     RECT  20.466 0.108 20.7 0.144 ;
     RECT  20.718 0.108 20.952 0.144 ;
     RECT  20.97 0.108 21.204 0.144 ;
     RECT  21.222 0.108 21.42 0.144 ;
     RECT  21.438 0.108 21.672 0.144 ;
     RECT  21.69 0.108 21.924 0.144 ;
     RECT  21.942 0.108 22.176 0.144 ;
     RECT  22.194 0.108 22.392 0.144 ;
     RECT  22.41 0.108 22.644 0.144 ;
     RECT  22.662 0.108 22.896 0.144 ;
     RECT  22.914 0.108 23.148 0.144 ;
     RECT  23.166 0.108 23.4 0.144 ;
     RECT  23.418 0.108 23.616 0.144 ;
     RECT  23.634 0.108 23.868 0.144 ;
     RECT  23.886 0.108 24.12 0.144 ;
     RECT  24.138 0.108 24.372 0.144 ;
     RECT  24.39 0.108 24.588 0.144 ;
     RECT  24.606 0.108 24.84 0.144 ;
     RECT  24.858 0.108 25.092 0.144 ;
     RECT  25.11 0.108 25.344 0.144 ;
     RECT  25.362 0.108 25.56 0.144 ;
     RECT  25.578 0.108 25.812 0.144 ;
     RECT  25.83 0.108 26.064 0.144 ;
     RECT  26.082 0.108 26.316 0.144 ;
     RECT  26.334 0.108 26.568 0.144 ;
     RECT  26.586 0.108 26.784 0.144 ;
     RECT  26.802 0.108 27.036 0.144 ;
     RECT  27.054 0.108 27.288 0.144 ;
     RECT  27.306 0.108 27.54 0.144 ;
     RECT  27.558 0.108 27.756 0.144 ;
     RECT  27.774 0.108 28.008 0.144 ;
     RECT  28.026 0.108 28.26 0.144 ;
     RECT  28.278 0.108 28.512 0.144 ;
     RECT  28.53 0.108 28.728 0.144 ;
     RECT  28.746 0.108 28.98 0.144 ;
     RECT  28.998 0.108 29.232 0.144 ;
     RECT  29.25 0.108 29.484 0.144 ;
     RECT  29.502 0.108 29.736 0.144 ;
     RECT  29.754 0.108 29.952 0.144 ;
     RECT  29.97 0.108 30.204 0.144 ;
     RECT  30.222 0.108 30.456 0.144 ;
     RECT  30.474 0.108 30.708 0.144 ;
     RECT  30.726 0.108 30.924 0.144 ;
     RECT  30.942 0.108 31.176 0.144 ;
     RECT  31.194 0.108 31.428 0.144 ;
     RECT  31.446 0.108 31.68 0.144 ;
     RECT  31.698 0.108 31.932 0.144 ;
     RECT  31.95 0.108 32.148 0.144 ;
     RECT  32.166 0.108 32.4 0.144 ;
     RECT  32.418 0.108 32.652 0.144 ;
     RECT  32.67 0.108 32.904 0.144 ;
     RECT  32.922 0.108 33.12 0.144 ;
     RECT  33.138 0.108 33.372 0.144 ;
     RECT  33.39 0.108 33.624 0.144 ;
     RECT  33.642 0.108 33.876 0.144 ;
     RECT  33.894 0.108 34.092 0.144 ;
     RECT  34.11 0.108 34.344 0.144 ;
     RECT  34.362 0.108 34.596 0.144 ;
     RECT  34.614 0.108 34.848 0.144 ;
     RECT  34.866 0.108 35.1 0.144 ;
     RECT  35.118 0.108 35.316 0.144 ;
     RECT  35.334 0.108 35.568 0.144 ;
     RECT  35.586 0.108 35.82 0.144 ;
     RECT  35.838 0.108 36.072 0.144 ;
     RECT  36.09 0.108 36.288 0.144 ;
     RECT  36.306 0.108 36.54 0.144 ;
     RECT  36.558 0.108 36.792 0.144 ;
     RECT  36.81 0.108 37.044 0.144 ;
     RECT  37.062 0.108 37.26 0.144 ;
     RECT  37.278 0.108 37.512 0.144 ;
     RECT  37.53 0.108 37.764 0.144 ;
     RECT  37.782 0.108 38.016 0.144 ;
     RECT  38.034 0.108 38.268 0.144 ;
     RECT  38.286 0.108 38.484 0.144 ;
     RECT  38.502 0.108 38.736 0.144 ;
     RECT  38.754 0.108 38.988 0.144 ;
     RECT  39.006 0.108 39.24 0.144 ;
     RECT  39.258 0.108 39.456 0.144 ;
     RECT  39.474 0.108 39.708 0.144 ;
     RECT  39.726 0.108 39.96 0.144 ;
     RECT  39.978 0.108 40.212 0.144 ;
     RECT  40.23 0.108 40.428 0.144 ;
     RECT  40.446 0.108 40.68 0.144 ;
     RECT  40.698 0.108 40.932 0.144 ;
     RECT  40.95 0.108 41.184 0.144 ;
     RECT  41.202 0.108 41.436 0.144 ;
     RECT  41.454 0.108 41.652 0.144 ;
     RECT  41.67 0.108 41.904 0.144 ;
     RECT  41.922 0.108 42.156 0.144 ;
     RECT  42.174 0.108 42.408 0.144 ;
     RECT  42.426 0.108 42.624 0.144 ;
     RECT  42.642 0.108 42.876 0.144 ;
     RECT  42.894 0.108 43.128 0.144 ;
     RECT  43.146 0.108 43.38 0.144 ;
     RECT  43.398 0.108 43.596 0.144 ;
     RECT  43.614 0.108 43.848 0.144 ;
     RECT  43.866 0.108 44.1 0.144 ;
     RECT  44.118 0.108 44.352 0.144 ;
     RECT  44.37 0.108 44.604 0.144 ;
     RECT  44.622 0.108 44.82 0.144 ;
     RECT  44.838 0.108 45.072 0.144 ;
     RECT  45.09 0.108 45.324 0.144 ;
     RECT  45.342 0.108 45.576 0.144 ;
     RECT  45.594 0.108 45.792 0.144 ;
     RECT  45.81 0.108 46.044 0.144 ;
     RECT  46.062 0.108 46.296 0.144 ;
     RECT  46.314 0.108 46.548 0.144 ;
     RECT  46.566 0.108 46.764 0.144 ;
     RECT  46.782 0.108 47.016 0.144 ;
     RECT  47.034 0.108 47.268 0.144 ;
     RECT  47.286 0.108 47.52 0.144 ;
     RECT  47.538 0.108 47.772 0.144 ;
     RECT  47.79 0.108 47.988 0.144 ;
     RECT  48.006 0.108 48.24 0.144 ;
     RECT  48.258 0.108 48.492 0.144 ;
     RECT  48.51 0.108 48.744 0.144 ;
     RECT  48.762 0.108 48.96 0.144 ;
     RECT  48.978 0.108 49.212 0.144 ;
     RECT  49.23 0.108 49.464 0.144 ;
     RECT  49.482 0.108 49.716 0.144 ;
     RECT  49.734 0.108 49.968 0.144 ;
     RECT  49.986 0.108 50.184 0.144 ;
     RECT  50.202 0.108 50.436 0.144 ;
     RECT  50.454 0.108 50.688 0.144 ;
     RECT  50.706 0.108 50.94 0.144 ;
     RECT  50.958 0.108 51.156 0.144 ;
     RECT  51.174 0.108 51.408 0.144 ;
     RECT  51.426 0.108 51.66 0.144 ;
     RECT  51.678 0.108 51.912 0.144 ;
     RECT  51.93 0.108 52.128 0.144 ;
     RECT  52.146 0.108 52.38 0.144 ;
     RECT  52.398 0.108 52.632 0.144 ;
     RECT  52.65 0.108 52.884 0.144 ;
     RECT  52.902 0.108 53.136 0.144 ;
     RECT  53.154 0.108 53.352 0.144 ;
     RECT  53.37 0.108 53.604 0.144 ;
     RECT  53.622 0.108 53.856 0.144 ;
     RECT  53.874 0.108 54.108 0.144 ;
     RECT  54.126 0.108 54.324 0.144 ;
     RECT  54.342 0.108 54.576 0.144 ;
     RECT  54.594 0.108 54.828 0.144 ;
     RECT  54.846 0.108 55.08 0.144 ;
     RECT  55.098 0.108 55.296 0.144 ;
     RECT  55.314 0.108 55.548 0.144 ;
     RECT  55.566 0.108 55.8 0.144 ;
     RECT  55.818 0.108 56.052 0.144 ;
     RECT  56.07 0.108 56.304 0.144 ;
     RECT  56.322 0.108 56.52 0.144 ;
     RECT  56.538 0.108 56.772 0.144 ;
     RECT  56.79 0.108 57.024 0.144 ;
     RECT  57.042 0.108 57.276 0.144 ;
     RECT  57.294 0.108 57.492 0.144 ;
     RECT  57.51 0.108 57.744 0.144 ;
     RECT  57.762 0.108 57.996 0.144 ;
     RECT  58.014 0.108 58.248 0.144 ;
     RECT  58.266 0.108 58.464 0.144 ;
     RECT  58.482 0.108 58.716 0.144 ;
     RECT  58.734 0.108 58.968 0.144 ;
     RECT  58.986 0.108 59.22 0.144 ;
     RECT  59.238 0.108 59.472 0.144 ;
     RECT  59.49 0.108 59.688 0.144 ;
     RECT  59.706 0.108 59.94 0.144 ;
     RECT  59.958 0.108 60.192 0.144 ;
     RECT  60.21 0.108 60.444 0.144 ;
     RECT  60.462 0.108 60.66 0.144 ;
     RECT  60.678 0.108 60.912 0.144 ;
     RECT  60.93 0.108 61.164 0.144 ;
     RECT  61.182 0.108 61.416 0.144 ;
     RECT  61.434 0.108 61.632 0.144 ;
     RECT  61.65 0.108 61.884 0.144 ;
     RECT  61.902 0.108 62.136 0.144 ;
     RECT  62.154 0.108 62.388 0.144 ;
     RECT  62.406 0.108 62.64 0.144 ;
     RECT  62.658 0.108 62.856 0.144 ;
     RECT  62.874 0.108 63.108 0.144 ;
     RECT  63.126 0.108 63.36 0.144 ;
     RECT  63.378 0.108 63.612 0.144 ;
     RECT  63.63 0.108 63.828 0.144 ;
     RECT  63.846 0.108 64.08 0.144 ;
     RECT  64.098 0.108 64.332 0.144 ;
     RECT  64.35 0.108 64.584 0.144 ;
     RECT  64.602 0.108 64.836 0.144 ;
     RECT  64.854 0.108 65.052 0.144 ;
     RECT  65.07 0.108 65.304 0.144 ;
     RECT  65.322 0.108 65.556 0.144 ;
     RECT  65.574 0.108 65.808 0.144 ;
     RECT  65.826 0.108 66.024 0.144 ;
     RECT  66.042 0.108 66.276 0.144 ;
     RECT  66.294 0.108 66.528 0.144 ;
     RECT  66.546 0.108 66.78 0.144 ;
     RECT  4.356 0.144 66.798 0.173 ;
     RECT  4.356 0.173 59.49 0.317 ;
     RECT  4.356 0.317 59.094 0.557 ;
     RECT  4.356 0.557 20.07 1.723 ;
     RECT  20.952 0.557 59.094 1.723 ;
     RECT  60.264 0.173 66.798 1.723 ;
     RECT  4.14 1.723 20.07 2.101 ;
     RECT  60.192 1.723 66.942 2.143 ;
     RECT  68.004 2.101 68.022 2.143 ;
     RECT  20.952 1.723 59.454 2.191 ;
     RECT  60.192 2.143 68.022 2.191 ;
     RECT  3.708 2.101 20.07 2.227 ;
     RECT  3.708 2.227 20.106 2.263 ;
     RECT  20.952 2.191 68.022 2.263 ;
     RECT  3.708 2.263 68.022 2.371 ;
     RECT  2.415 2.143 2.505 2.413 ;
     RECT  3.708 2.371 68.238 2.641 ;
     RECT  3.708 2.641 68.418 2.911 ;
     RECT  3.708 2.911 68.706 3.181 ;
     RECT  3.564 3.181 68.706 3.371 ;
     RECT  3.564 3.371 3.582 3.437 ;
     RECT  4.5 3.371 68.706 3.721 ;
     RECT  4.5 3.721 68.886 4.648 ;
     RECT  4.14 4.648 68.886 4.685 ;
     RECT  4.5 4.685 68.886 5.341 ;
     RECT  4.5 5.341 69.03 7.961 ;
     RECT  4.5 7.961 68.994 9.085 ;
     RECT  4.356 9.085 68.994 10.625 ;
     RECT  4.356 10.625 68.778 14.639 ;
     RECT  4.716 14.639 68.778 15.521 ;
     RECT  4.716 15.521 68.598 15.629 ;
     RECT  4.716 15.629 68.454 19.265 ;
     RECT  3.924 14.791 3.942 19.535 ;
     RECT  4.86 19.265 68.454 19.607 ;
     RECT  4.86 19.607 68.382 20.345 ;
     RECT  4.86 20.345 67.986 23.855 ;
     RECT  4.896 23.855 67.986 24.161 ;
     RECT  3.672 19.651 3.69 24.233 ;
     RECT  4.896 24.161 67.914 24.233 ;
     RECT  4.896 24.233 67.806 24.503 ;
     RECT  4.896 24.503 67.77 30.451 ;
     RECT  3.492 24.241 3.51 30.605 ;
     RECT  4.86 30.451 67.77 30.605 ;
     RECT  4.86 30.605 67.59 30.721 ;
     RECT  2.415 2.413 2.697 34.307 ;
     RECT  2.415 34.307 2.505 34.577 ;
     RECT  4.176 30.721 67.59 34.799 ;
     RECT  67.572 34.799 67.59 35.933 ;
     RECT  4.356 34.799 66.798 36.576 ;
     RECT  4.374 36.576 4.608 36.588 ;
     RECT  4.626 36.576 4.86 36.588 ;
     RECT  4.878 36.576 5.112 36.588 ;
     RECT  5.13 36.576 5.364 36.588 ;
     RECT  5.382 36.576 5.58 36.588 ;
     RECT  5.598 36.576 5.832 36.588 ;
     RECT  5.85 36.576 6.084 36.588 ;
     RECT  6.102 36.576 6.336 36.588 ;
     RECT  6.354 36.576 6.552 36.588 ;
     RECT  6.57 36.576 6.804 36.588 ;
     RECT  6.822 36.576 7.056 36.588 ;
     RECT  7.074 36.576 7.308 36.588 ;
     RECT  7.326 36.576 7.524 36.588 ;
     RECT  7.542 36.576 7.776 36.588 ;
     RECT  7.794 36.576 8.028 36.588 ;
     RECT  8.046 36.576 8.28 36.588 ;
     RECT  8.298 36.576 8.532 36.588 ;
     RECT  8.55 36.576 8.748 36.588 ;
     RECT  8.766 36.576 9 36.588 ;
     RECT  9.018 36.576 9.252 36.588 ;
     RECT  9.27 36.576 9.504 36.588 ;
     RECT  9.522 36.576 9.72 36.588 ;
     RECT  9.738 36.576 9.972 36.588 ;
     RECT  9.99 36.576 10.224 36.588 ;
     RECT  10.242 36.576 10.476 36.588 ;
     RECT  10.494 36.576 10.692 36.588 ;
     RECT  10.71 36.576 10.944 36.588 ;
     RECT  10.962 36.576 11.196 36.588 ;
     RECT  11.214 36.576 11.448 36.588 ;
     RECT  11.466 36.576 11.7 36.588 ;
     RECT  11.718 36.576 11.916 36.588 ;
     RECT  11.934 36.576 12.168 36.588 ;
     RECT  12.186 36.576 12.42 36.588 ;
     RECT  12.438 36.576 12.672 36.588 ;
     RECT  12.69 36.576 12.888 36.588 ;
     RECT  12.906 36.576 13.14 36.588 ;
     RECT  13.158 36.576 13.392 36.588 ;
     RECT  13.41 36.576 13.644 36.588 ;
     RECT  13.662 36.576 13.86 36.588 ;
     RECT  13.878 36.576 14.112 36.588 ;
     RECT  14.13 36.576 14.364 36.588 ;
     RECT  14.382 36.576 14.616 36.588 ;
     RECT  14.634 36.576 14.868 36.588 ;
     RECT  14.886 36.576 15.084 36.588 ;
     RECT  15.102 36.576 15.336 36.588 ;
     RECT  15.354 36.576 15.588 36.588 ;
     RECT  15.606 36.576 15.84 36.588 ;
     RECT  15.858 36.576 16.056 36.588 ;
     RECT  16.074 36.576 16.308 36.588 ;
     RECT  16.326 36.576 16.56 36.588 ;
     RECT  16.578 36.576 16.812 36.588 ;
     RECT  16.83 36.576 17.064 36.588 ;
     RECT  17.082 36.576 17.28 36.588 ;
     RECT  17.298 36.576 17.532 36.588 ;
     RECT  17.55 36.576 17.784 36.588 ;
     RECT  17.802 36.576 18.036 36.588 ;
     RECT  18.054 36.576 18.252 36.588 ;
     RECT  18.27 36.576 18.504 36.588 ;
     RECT  18.522 36.576 18.756 36.588 ;
     RECT  18.774 36.576 19.008 36.588 ;
     RECT  19.026 36.576 19.224 36.588 ;
     RECT  19.242 36.576 19.476 36.588 ;
     RECT  19.494 36.576 19.728 36.588 ;
     RECT  19.746 36.576 19.98 36.588 ;
     RECT  19.998 36.576 20.232 36.588 ;
     RECT  20.25 36.576 20.448 36.588 ;
     RECT  20.466 36.576 20.7 36.588 ;
     RECT  20.718 36.576 20.952 36.588 ;
     RECT  20.97 36.576 21.204 36.588 ;
     RECT  21.222 36.576 21.42 36.588 ;
     RECT  21.438 36.576 21.672 36.588 ;
     RECT  21.69 36.576 21.924 36.588 ;
     RECT  21.942 36.576 22.176 36.588 ;
     RECT  22.194 36.576 22.392 36.588 ;
     RECT  22.41 36.576 22.644 36.588 ;
     RECT  22.662 36.576 22.896 36.588 ;
     RECT  22.914 36.576 23.148 36.588 ;
     RECT  23.166 36.576 23.4 36.588 ;
     RECT  23.418 36.576 23.616 36.588 ;
     RECT  23.634 36.576 23.868 36.588 ;
     RECT  23.886 36.576 24.12 36.588 ;
     RECT  24.138 36.576 24.372 36.588 ;
     RECT  24.39 36.576 24.588 36.588 ;
     RECT  24.606 36.576 24.84 36.588 ;
     RECT  24.858 36.576 25.092 36.588 ;
     RECT  25.11 36.576 25.344 36.588 ;
     RECT  25.362 36.576 25.56 36.588 ;
     RECT  25.578 36.576 25.812 36.588 ;
     RECT  25.83 36.576 26.064 36.588 ;
     RECT  26.082 36.576 26.316 36.588 ;
     RECT  26.334 36.576 26.568 36.588 ;
     RECT  26.586 36.576 26.784 36.588 ;
     RECT  26.802 36.576 27.036 36.588 ;
     RECT  27.054 36.576 27.288 36.588 ;
     RECT  27.306 36.576 27.54 36.588 ;
     RECT  27.558 36.576 27.756 36.588 ;
     RECT  27.774 36.576 28.008 36.588 ;
     RECT  28.026 36.576 28.26 36.588 ;
     RECT  28.278 36.576 28.512 36.588 ;
     RECT  28.53 36.576 28.728 36.588 ;
     RECT  28.746 36.576 28.98 36.588 ;
     RECT  28.998 36.576 29.232 36.588 ;
     RECT  29.25 36.576 29.484 36.588 ;
     RECT  29.502 36.576 29.736 36.588 ;
     RECT  29.754 36.576 29.952 36.588 ;
     RECT  29.97 36.576 30.204 36.588 ;
     RECT  30.222 36.576 30.456 36.588 ;
     RECT  30.474 36.576 30.708 36.588 ;
     RECT  30.726 36.576 30.924 36.588 ;
     RECT  30.942 36.576 31.176 36.588 ;
     RECT  31.194 36.576 31.428 36.588 ;
     RECT  31.446 36.576 31.68 36.588 ;
     RECT  31.698 36.576 31.932 36.588 ;
     RECT  31.95 36.576 32.148 36.588 ;
     RECT  32.166 36.576 32.4 36.588 ;
     RECT  32.418 36.576 32.652 36.588 ;
     RECT  32.67 36.576 32.904 36.588 ;
     RECT  32.922 36.576 33.12 36.588 ;
     RECT  33.138 36.576 33.372 36.588 ;
     RECT  33.39 36.576 33.624 36.588 ;
     RECT  33.642 36.576 33.876 36.588 ;
     RECT  33.894 36.576 34.092 36.588 ;
     RECT  34.11 36.576 34.344 36.588 ;
     RECT  34.362 36.576 34.596 36.588 ;
     RECT  34.614 36.576 34.848 36.588 ;
     RECT  34.866 36.576 35.1 36.588 ;
     RECT  35.118 36.576 35.316 36.588 ;
     RECT  35.334 36.576 35.568 36.588 ;
     RECT  35.586 36.576 35.82 36.588 ;
     RECT  35.838 36.576 36.072 36.588 ;
     RECT  36.09 36.576 36.288 36.588 ;
     RECT  36.306 36.576 36.54 36.588 ;
     RECT  36.558 36.576 36.792 36.588 ;
     RECT  36.81 36.576 37.044 36.588 ;
     RECT  37.062 36.576 37.26 36.588 ;
     RECT  37.278 36.576 37.512 36.588 ;
     RECT  37.53 36.576 37.764 36.588 ;
     RECT  37.782 36.576 38.016 36.588 ;
     RECT  38.034 36.576 38.268 36.588 ;
     RECT  38.286 36.576 38.484 36.588 ;
     RECT  38.502 36.576 38.736 36.588 ;
     RECT  38.754 36.576 38.988 36.588 ;
     RECT  39.006 36.576 39.24 36.588 ;
     RECT  39.258 36.576 39.456 36.588 ;
     RECT  39.474 36.576 39.708 36.588 ;
     RECT  39.726 36.576 39.96 36.588 ;
     RECT  39.978 36.576 40.212 36.588 ;
     RECT  40.23 36.576 40.428 36.588 ;
     RECT  40.446 36.576 40.68 36.588 ;
     RECT  40.698 36.576 40.932 36.588 ;
     RECT  40.95 36.576 41.184 36.588 ;
     RECT  41.202 36.576 41.436 36.588 ;
     RECT  41.454 36.576 41.652 36.588 ;
     RECT  41.67 36.576 41.904 36.588 ;
     RECT  41.922 36.576 42.156 36.588 ;
     RECT  42.174 36.576 42.408 36.588 ;
     RECT  42.426 36.576 42.624 36.588 ;
     RECT  42.642 36.576 42.876 36.588 ;
     RECT  42.894 36.576 43.128 36.588 ;
     RECT  43.146 36.576 43.38 36.588 ;
     RECT  43.398 36.576 43.596 36.588 ;
     RECT  43.614 36.576 43.848 36.588 ;
     RECT  43.866 36.576 44.1 36.588 ;
     RECT  44.118 36.576 44.352 36.588 ;
     RECT  44.37 36.576 44.604 36.588 ;
     RECT  44.622 36.576 44.82 36.588 ;
     RECT  44.838 36.576 45.072 36.588 ;
     RECT  45.09 36.576 45.324 36.588 ;
     RECT  45.342 36.576 45.576 36.588 ;
     RECT  45.594 36.576 45.792 36.588 ;
     RECT  45.81 36.576 46.044 36.588 ;
     RECT  46.062 36.576 46.296 36.588 ;
     RECT  46.314 36.576 46.548 36.588 ;
     RECT  46.566 36.576 46.764 36.588 ;
     RECT  46.782 36.576 47.016 36.588 ;
     RECT  47.034 36.576 47.268 36.588 ;
     RECT  47.286 36.576 47.52 36.588 ;
     RECT  47.538 36.576 47.772 36.588 ;
     RECT  47.79 36.576 47.988 36.588 ;
     RECT  48.006 36.576 48.24 36.588 ;
     RECT  48.258 36.576 48.492 36.588 ;
     RECT  48.51 36.576 48.744 36.588 ;
     RECT  48.762 36.576 48.96 36.588 ;
     RECT  48.978 36.576 49.212 36.588 ;
     RECT  49.23 36.576 49.464 36.588 ;
     RECT  49.482 36.576 49.716 36.588 ;
     RECT  49.734 36.576 49.968 36.588 ;
     RECT  49.986 36.576 50.184 36.588 ;
     RECT  50.202 36.576 50.436 36.588 ;
     RECT  50.454 36.576 50.688 36.588 ;
     RECT  50.706 36.576 50.94 36.588 ;
     RECT  50.958 36.576 51.156 36.588 ;
     RECT  51.174 36.576 51.408 36.588 ;
     RECT  51.426 36.576 51.66 36.588 ;
     RECT  51.678 36.576 51.912 36.588 ;
     RECT  51.93 36.576 52.128 36.588 ;
     RECT  52.146 36.576 52.38 36.588 ;
     RECT  52.398 36.576 52.632 36.588 ;
     RECT  52.65 36.576 52.884 36.588 ;
     RECT  52.902 36.576 53.136 36.588 ;
     RECT  53.154 36.576 53.352 36.588 ;
     RECT  53.37 36.576 53.604 36.588 ;
     RECT  53.622 36.576 53.856 36.588 ;
     RECT  53.874 36.576 54.108 36.588 ;
     RECT  54.126 36.576 54.324 36.588 ;
     RECT  54.342 36.576 54.576 36.588 ;
     RECT  54.594 36.576 54.828 36.588 ;
     RECT  54.846 36.576 55.08 36.588 ;
     RECT  55.098 36.576 55.296 36.588 ;
     RECT  55.314 36.576 55.548 36.588 ;
     RECT  55.566 36.576 55.8 36.588 ;
     RECT  55.818 36.576 56.052 36.588 ;
     RECT  56.07 36.576 56.304 36.588 ;
     RECT  56.322 36.576 56.52 36.588 ;
     RECT  56.538 36.576 56.772 36.588 ;
     RECT  56.79 36.576 57.024 36.588 ;
     RECT  57.042 36.576 57.276 36.588 ;
     RECT  57.294 36.576 57.492 36.588 ;
     RECT  57.51 36.576 57.744 36.588 ;
     RECT  57.762 36.576 57.996 36.588 ;
     RECT  58.014 36.576 58.248 36.588 ;
     RECT  58.266 36.576 58.464 36.588 ;
     RECT  58.482 36.576 58.716 36.588 ;
     RECT  58.734 36.576 58.968 36.588 ;
     RECT  58.986 36.576 59.22 36.588 ;
     RECT  59.238 36.576 59.472 36.588 ;
     RECT  59.49 36.576 59.688 36.588 ;
     RECT  59.706 36.576 59.94 36.588 ;
     RECT  59.958 36.576 60.192 36.588 ;
     RECT  60.21 36.576 60.444 36.588 ;
     RECT  60.462 36.576 60.66 36.588 ;
     RECT  60.678 36.576 60.912 36.588 ;
     RECT  60.93 36.576 61.164 36.588 ;
     RECT  61.182 36.576 61.416 36.588 ;
     RECT  61.434 36.576 61.632 36.588 ;
     RECT  61.65 36.576 61.884 36.588 ;
     RECT  61.902 36.576 62.136 36.588 ;
     RECT  62.154 36.576 62.388 36.588 ;
     RECT  62.406 36.576 62.64 36.588 ;
     RECT  62.658 36.576 62.856 36.588 ;
     RECT  62.874 36.576 63.108 36.588 ;
     RECT  63.126 36.576 63.36 36.588 ;
     RECT  63.378 36.576 63.612 36.588 ;
     RECT  63.63 36.576 63.828 36.588 ;
     RECT  63.846 36.576 64.08 36.588 ;
     RECT  64.098 36.576 64.332 36.588 ;
     RECT  64.35 36.576 64.584 36.588 ;
     RECT  64.602 36.576 64.836 36.588 ;
     RECT  64.854 36.576 65.052 36.588 ;
     RECT  65.07 36.576 65.304 36.588 ;
     RECT  65.322 36.576 65.556 36.588 ;
     RECT  65.574 36.576 65.808 36.588 ;
     RECT  65.826 36.576 66.024 36.588 ;
     RECT  66.042 36.576 66.276 36.588 ;
     RECT  66.294 36.576 66.528 36.588 ;
     RECT  66.546 36.576 66.78 36.588 ;
     RECT  10.008 36.588 10.098 36.653 ;
     RECT  13.176 36.588 13.266 36.653 ;
     RECT  15.228 36.588 15.318 36.653 ;
     RECT  21.456 36.588 21.546 36.653 ;
     RECT  24.156 36.588 24.246 36.653 ;
     RECT  56.556 36.588 56.772 36.653 ;
     RECT  56.79 36.588 57.024 36.653 ;
     RECT  57.042 36.588 57.15 36.653 ;
     RECT  59.724 36.588 59.814 36.653 ;
    LAYER M4 ;
     RECT  0.229 6.096 2.408 6.12 ;
     RECT  2.408 2.148 2.512 34.572 ;
     RECT  2.512 2.418 2.704 34.302 ;
     RECT  2.704 3.408 4.693 3.432 ;
     RECT  4.129 4.656 4.693 4.68 ;
     RECT  4.481 34.752 4.741 34.776 ;
     RECT  4.525 0.192 4.787 0.216 ;
     RECT  2.704 6.096 4.981 6.12 ;
     RECT  4.129 1.728 5.108 1.752 ;
     RECT  4.693 3.408 5.108 4.68 ;
     RECT  4.981 5.76 5.108 6.12 ;
     RECT  4.981 30.672 5.108 30.696 ;
     RECT  4.741 34.176 5.108 34.776 ;
     RECT  5.108 1.728 5.404 34.776 ;
     RECT  5.404 34.224 5.461 34.776 ;
     RECT  5.404 1.728 5.669 3.432 ;
     RECT  5.461 34.224 5.717 34.824 ;
     RECT  5.669 1.152 5.753 3.432 ;
     RECT  5.753 1.728 6.149 3.432 ;
     RECT  6.149 1.728 6.227 2.904 ;
     RECT  5.717 34.224 6.268 34.296 ;
     RECT  6.268 34.224 6.653 34.248 ;
     RECT  5.404 30.192 6.661 30.744 ;
     RECT  6.227 1.728 7.333 1.8 ;
     RECT  6.227 2.88 7.333 2.904 ;
     RECT  5.404 4.656 7.405 6.12 ;
     RECT  7.333 1.728 7.525 2.904 ;
     RECT  7.525 1.728 7.621 2.952 ;
     RECT  7.621 34.704 7.669 34.728 ;
     RECT  7.621 1.728 7.808 3.528 ;
     RECT  7.405 4.656 7.808 6.312 ;
     RECT  6.661 30.192 7.808 30.792 ;
     RECT  6.901 33.648 7.808 33.672 ;
     RECT  7.669 34.704 7.808 34.824 ;
     RECT  7.621 0.288 7.955 0.312 ;
     RECT  7.808 1.728 7.985 34.824 ;
     RECT  7.985 1.728 8.104 34.68 ;
     RECT  8.104 34.56 8.237 34.68 ;
     RECT  8.237 34.56 8.281 34.584 ;
     RECT  8.104 1.728 8.915 2.28 ;
     RECT  8.104 30.48 9.109 31.32 ;
     RECT  9.349 34.224 9.829 34.248 ;
     RECT  8.915 1.728 9.889 1.752 ;
     RECT  9.889 1.728 10.069 2.28 ;
     RECT  8.104 3.408 10.069 6.6 ;
     RECT  9.829 34.224 10.109 34.824 ;
     RECT  10.069 1.728 10.124 6.6 ;
     RECT  9.853 20.064 10.321 20.088 ;
     RECT  10.124 1.728 10.508 6.792 ;
     RECT  10.321 19.776 10.508 20.088 ;
     RECT  9.109 30.192 10.508 31.32 ;
     RECT  10.109 34.224 10.508 34.68 ;
     RECT  10.508 1.728 10.804 34.68 ;
     RECT  8.389 35.904 11.117 35.928 ;
     RECT  10.804 1.728 11.297 1.8 ;
     RECT  10.804 34.224 11.405 34.68 ;
     RECT  10.804 30.192 11.797 30.216 ;
     RECT  11.797 30.192 11.801 30.504 ;
     RECT  11.405 34.224 11.981 34.248 ;
     RECT  11.801 30.48 12.017 30.504 ;
     RECT  10.804 4.512 12.14 6.312 ;
     RECT  12.14 3.936 12.181 6.312 ;
     RECT  12.181 3.936 12.733 6.84 ;
     RECT  11.297 1.728 12.737 1.752 ;
     RECT  11.797 2.88 12.997 2.904 ;
     RECT  12.733 3.936 12.997 7.128 ;
     RECT  12.037 30.672 12.997 30.84 ;
     RECT  12.997 2.88 13.208 7.128 ;
     RECT  12.805 15.072 13.208 15.096 ;
     RECT  12.997 30.672 13.208 31.128 ;
     RECT  12.517 34.8 13.208 34.824 ;
     RECT  13.208 2.148 13.477 34.824 ;
     RECT  13.477 2.148 13.504 34.872 ;
     RECT  13.093 0.192 13.619 0.216 ;
     RECT  13.504 34.752 13.619 34.872 ;
     RECT  13.504 2.148 13.667 3.384 ;
     RECT  13.667 2.88 13.817 3 ;
     RECT  13.504 30.192 13.961 31.128 ;
     RECT  13.619 34.752 14.069 34.776 ;
     RECT  13.504 4.752 14.569 7.128 ;
     RECT  14.005 35.904 14.681 35.928 ;
     RECT  14.677 15.408 14.861 15.432 ;
     RECT  13.961 30.192 14.861 30.792 ;
     RECT  14.861 30.192 14.933 30.216 ;
     RECT  14.485 34.224 15.173 34.248 ;
     RECT  13.817 2.88 15.289 2.904 ;
     RECT  15.289 2.784 15.325 2.904 ;
     RECT  14.569 4.368 15.325 7.128 ;
     RECT  14.005 1.728 15.397 1.752 ;
     RECT  15.397 1.104 15.517 1.752 ;
     RECT  15.517 1.104 15.548 1.128 ;
     RECT  15.325 2.784 15.589 7.128 ;
     RECT  15.548 0.144 15.635 1.128 ;
     RECT  15.173 34.224 15.637 34.776 ;
     RECT  15.635 0.192 15.731 1.128 ;
     RECT  15.589 2.148 15.908 7.128 ;
     RECT  15.685 31.2 15.908 31.224 ;
     RECT  15.637 34.224 15.908 34.824 ;
     RECT  15.908 2.148 16.204 34.824 ;
     RECT  16.204 34.224 16.265 34.824 ;
     RECT  16.204 9.696 16.355 9.72 ;
     RECT  15.731 0.192 16.451 0.408 ;
     RECT  16.265 34.224 16.517 34.776 ;
     RECT  16.451 0.192 16.547 0.216 ;
     RECT  16.204 14.832 16.553 14.856 ;
     RECT  16.204 31.008 16.589 31.224 ;
     RECT  16.204 2.148 16.613 6.888 ;
     RECT  16.796 0.144 16.883 0.168 ;
     RECT  16.517 34.752 17.021 34.776 ;
     RECT  16.613 1.728 17.027 6.888 ;
     RECT  17.027 3.312 17.089 6.888 ;
     RECT  17.089 3.36 17.129 6.888 ;
     RECT  16.589 31.008 17.173 31.032 ;
     RECT  16.204 20.496 17.237 20.52 ;
     RECT  17.027 1.728 17.459 2.28 ;
     RECT  17.413 34.8 17.653 34.824 ;
     RECT  17.173 30.816 17.893 31.032 ;
     RECT  17.129 3.456 17.917 6.888 ;
     RECT  17.459 1.728 17.921 1.752 ;
     RECT  17.917 3.456 18.133 7.464 ;
     RECT  18.133 2.88 18.421 7.464 ;
     RECT  18.421 2.016 18.608 7.464 ;
     RECT  17.893 30.432 18.608 31.032 ;
     RECT  17.653 34.8 18.608 34.872 ;
     RECT  18.608 2.016 18.659 34.872 ;
     RECT  18.659 2.148 18.712 34.872 ;
     RECT  18.529 0.528 18.853 0.552 ;
     RECT  18.712 2.418 18.904 34.872 ;
     RECT  18.853 0.192 19.043 0.552 ;
     RECT  18.904 34.224 19.043 34.872 ;
     RECT  19.043 34.224 19.073 34.776 ;
     RECT  19.043 0.528 19.379 0.552 ;
     RECT  18.904 30.432 19.649 30.744 ;
     RECT  19.073 34.224 19.937 34.248 ;
     RECT  19.649 30.672 20.101 30.744 ;
     RECT  20.204 0.144 20.483 0.168 ;
     RECT  18.904 2.736 20.485 6.12 ;
     RECT  20.645 0.528 20.729 0.552 ;
     RECT  20.101 30.672 20.821 30.84 ;
     RECT  20.485 2.496 21.061 6.12 ;
     RECT  21.061 2.304 21.109 6.12 ;
     RECT  21.109 2.304 21.149 6.216 ;
     RECT  21.109 34.368 21.157 34.824 ;
     RECT  21.149 2.304 21.301 6.888 ;
     RECT  21.301 1.728 21.308 6.888 ;
     RECT  20.821 30.48 21.308 30.84 ;
     RECT  21.157 34.368 21.308 34.92 ;
     RECT  21.308 1.728 21.587 34.92 ;
     RECT  21.587 1.728 21.604 34.392 ;
     RECT  21.604 34.224 21.665 34.392 ;
     RECT  21.665 34.224 22.241 34.248 ;
     RECT  21.604 9.696 22.451 9.72 ;
     RECT  21.604 1.728 22.637 6.888 ;
     RECT  21.604 30.192 22.693 30.696 ;
     RECT  22.693 30.192 23.269 30.792 ;
     RECT  22.637 1.728 23.321 6.84 ;
     RECT  23.321 1.824 23.357 6.84 ;
     RECT  23.357 2.016 24.008 6.84 ;
     RECT  23.269 30.192 24.008 30.84 ;
     RECT  22.981 34.8 24.008 34.824 ;
     RECT  24.008 2.016 24.035 34.824 ;
     RECT  24.035 2.148 24.112 34.824 ;
     RECT  23.893 0.528 24.229 0.552 ;
     RECT  24.112 2.16 24.229 34.824 ;
     RECT  24.229 2.16 24.304 34.872 ;
     RECT  24.229 0.192 24.419 0.552 ;
     RECT  24.304 9.696 24.419 9.816 ;
     RECT  24.304 34.224 24.419 34.872 ;
     RECT  24.304 2.16 24.467 6.84 ;
     RECT  24.304 30.576 24.473 30.696 ;
     RECT  24.419 34.224 24.515 34.776 ;
     RECT  24.473 30.576 24.653 30.6 ;
     RECT  24.419 0.528 25.121 0.552 ;
     RECT  24.419 9.696 25.165 9.72 ;
     RECT  24.467 2.16 25.189 6.648 ;
     RECT  24.709 35.904 25.265 35.928 ;
     RECT  25.189 1.728 25.523 6.648 ;
     RECT  24.515 34.752 25.669 34.776 ;
     RECT  25.523 3.744 25.729 6.648 ;
     RECT  25.429 30.48 26.149 30.504 ;
     RECT  25.523 1.728 26.549 2.712 ;
     RECT  25.729 3.744 26.549 6.696 ;
     RECT  26.549 1.728 26.708 6.696 ;
     RECT  26.149 30.48 26.708 30.744 ;
     RECT  25.669 34.752 26.708 34.824 ;
     RECT  26.581 0.192 26.723 0.216 ;
     RECT  26.708 1.728 27.004 34.824 ;
     RECT  27.004 2.832 27.155 3.96 ;
     RECT  27.004 34.224 27.155 34.824 ;
     RECT  27.155 2.88 27.317 3.96 ;
     RECT  27.155 34.224 27.353 34.776 ;
     RECT  27.004 5.04 27.395 6.744 ;
     RECT  27.98 0.144 28.067 0.168 ;
     RECT  27.317 3.936 28.117 3.96 ;
     RECT  27.004 30.192 28.217 30.84 ;
     RECT  27.004 1.728 28.349 1.752 ;
     RECT  28.117 3.936 28.361 4.056 ;
     RECT  27.395 5.712 28.393 6.744 ;
     RECT  28.349 1.728 28.421 1.8 ;
     RECT  27.317 2.88 28.421 2.952 ;
     RECT  28.393 5.04 28.501 6.744 ;
     RECT  27.353 34.752 28.753 34.776 ;
     RECT  28.357 35.904 28.937 35.928 ;
     RECT  28.421 1.728 29.141 2.952 ;
     RECT  28.361 3.936 29.141 4.008 ;
     RECT  28.753 34.224 29.221 34.776 ;
     RECT  28.217 30.816 29.269 30.84 ;
     RECT  29.221 34.224 29.269 34.824 ;
     RECT  29.221 0.192 29.363 0.216 ;
     RECT  29.141 1.728 29.408 4.008 ;
     RECT  28.501 5.04 29.408 6.888 ;
     RECT  29.269 30.816 29.408 31.128 ;
     RECT  29.269 34.224 29.408 34.92 ;
     RECT  29.408 1.728 29.651 34.92 ;
     RECT  29.651 1.728 29.704 34.392 ;
     RECT  29.704 1.728 29.843 6.12 ;
     RECT  29.843 1.728 29.981 2.904 ;
     RECT  29.704 30.72 30.305 31.128 ;
     RECT  30.305 30.816 30.485 31.128 ;
     RECT  29.981 1.728 30.737 1.8 ;
     RECT  29.981 2.88 30.773 2.904 ;
     RECT  29.843 3.936 30.805 6.12 ;
     RECT  29.704 34.272 30.805 34.392 ;
     RECT  30.805 34.224 31.013 34.392 ;
     RECT  30.805 3.408 31.237 6.12 ;
     RECT  31.237 3.408 31.765 6.6 ;
     RECT  30.485 30.816 31.765 30.84 ;
     RECT  31.013 34.224 31.909 34.776 ;
     RECT  31.909 34.224 31.957 34.872 ;
     RECT  31.909 0.192 32.051 0.216 ;
     RECT  30.737 1.728 32.108 1.752 ;
     RECT  31.765 3.312 32.108 6.6 ;
     RECT  31.765 30.72 32.108 30.84 ;
     RECT  31.957 34.224 32.108 34.968 ;
     RECT  32.108 1.728 32.291 34.968 ;
     RECT  32.291 1.728 32.404 34.776 ;
     RECT  32.404 1.728 32.465 6.6 ;
     RECT  32.404 34.368 32.501 34.776 ;
     RECT  32.465 2.88 33.049 6.6 ;
     RECT  32.501 34.752 33.077 34.776 ;
     RECT  32.404 30.72 33.493 30.84 ;
     RECT  33.049 4.128 33.589 6.6 ;
     RECT  32.465 1.728 33.649 1.752 ;
     RECT  33.049 2.88 33.649 2.904 ;
     RECT  33.013 35.904 33.689 35.928 ;
     RECT  33.649 1.728 33.779 2.904 ;
     RECT  33.493 30.72 33.973 31.032 ;
     RECT  33.973 30.72 34.213 31.224 ;
     RECT  33.733 34.176 34.685 34.2 ;
     RECT  33.589 4.128 34.693 6.888 ;
     RECT  33.779 1.728 34.808 1.8 ;
     RECT  34.693 3.024 34.808 6.888 ;
     RECT  34.213 30.144 34.808 31.224 ;
     RECT  34.685 34.176 34.808 34.248 ;
     RECT  34.808 1.728 34.933 34.572 ;
     RECT  34.933 1.728 35.104 34.824 ;
     RECT  34.933 0.288 35.173 0.312 ;
     RECT  35.173 0.192 35.219 0.312 ;
     RECT  35.104 30.672 35.273 30.84 ;
     RECT  35.219 0.192 35.315 0.216 ;
     RECT  35.104 34.224 35.345 34.824 ;
     RECT  35.104 1.728 35.489 7.272 ;
     RECT  35.104 14.832 35.633 14.856 ;
     RECT  35.104 9.696 35.891 9.72 ;
     RECT  35.345 34.8 35.921 34.824 ;
     RECT  36.236 0.144 36.323 0.168 ;
     RECT  35.273 30.72 36.421 30.84 ;
     RECT  35.489 1.728 36.493 4.392 ;
     RECT  35.489 5.472 36.493 7.272 ;
     RECT  36.421 30.72 36.661 31.32 ;
     RECT  36.493 1.728 36.893 7.272 ;
     RECT  36.661 30.576 37.141 31.32 ;
     RECT  36.745 0.576 37.289 0.6 ;
     RECT  36.893 1.776 37.508 7.272 ;
     RECT  37.141 30.144 37.508 31.32 ;
     RECT  37.381 34.224 37.508 34.248 ;
     RECT  37.508 1.776 37.621 34.572 ;
     RECT  37.621 1.776 37.804 34.728 ;
     RECT  37.804 34.224 38.189 34.728 ;
     RECT  37.804 30.48 38.225 30.84 ;
     RECT  37.861 1.728 38.729 1.752 ;
     RECT  37.804 3.408 38.933 6.888 ;
     RECT  38.933 3.36 39.017 6.888 ;
     RECT  38.225 30.72 39.109 30.84 ;
     RECT  38.189 34.224 39.589 34.248 ;
     RECT  39.589 34.224 39.829 34.296 ;
     RECT  39.973 0.528 40.021 0.552 ;
     RECT  39.085 2.688 40.021 3 ;
     RECT  39.017 3.984 40.021 6.888 ;
     RECT  40.021 2.688 40.208 6.888 ;
     RECT  39.109 30.72 40.208 31.032 ;
     RECT  39.829 34.224 40.208 34.344 ;
     RECT  40.208 2.148 40.309 34.572 ;
     RECT  40.309 2.148 40.312 34.824 ;
     RECT  40.312 2.256 40.396 34.824 ;
     RECT  40.396 2.256 40.504 34.68 ;
     RECT  40.021 0.288 40.549 0.552 ;
     RECT  40.504 34.224 40.637 34.68 ;
     RECT  40.637 34.224 40.681 34.584 ;
     RECT  40.549 0.192 40.691 0.552 ;
     RECT  40.069 35.904 40.709 35.928 ;
     RECT  40.504 9.12 40.717 9.144 ;
     RECT  40.691 0.528 41.075 0.552 ;
     RECT  40.504 30.432 41.249 30.84 ;
     RECT  40.504 2.256 41.509 6.552 ;
     RECT  40.681 34.224 41.596 34.344 ;
     RECT  41.249 30.72 41.753 30.84 ;
     RECT  41.753 30.816 42.037 30.84 ;
     RECT  42.101 0.528 42.185 0.552 ;
     RECT  42.38 0.144 42.467 0.312 ;
     RECT  41.596 34.224 42.517 34.248 ;
     RECT  42.517 33.648 42.757 34.248 ;
     RECT  41.509 1.728 42.908 6.552 ;
     RECT  42.577 9.696 42.908 9.72 ;
     RECT  42.037 30.816 42.908 31.32 ;
     RECT  42.757 33.648 42.908 34.392 ;
     RECT  42.908 1.728 42.997 34.572 ;
     RECT  42.997 1.728 43.204 34.728 ;
     RECT  43.204 3.36 43.262 6.12 ;
     RECT  42.467 0.288 43.331 0.312 ;
     RECT  43.204 34.224 43.337 34.728 ;
     RECT  43.262 3.408 43.345 6.12 ;
     RECT  43.345 3.504 43.373 6.12 ;
     RECT  43.373 4.128 44.437 6.12 ;
     RECT  43.337 34.224 44.437 34.248 ;
     RECT  43.204 1.728 44.483 2.28 ;
     RECT  44.437 4.08 44.593 6.12 ;
     RECT  43.204 30.72 44.677 30.84 ;
     RECT  44.593 3.936 44.909 6.12 ;
     RECT  44.677 30.48 44.917 30.84 ;
     RECT  44.437 34.224 44.993 34.824 ;
     RECT  44.909 3.408 45.445 6.12 ;
     RECT  45.445 3.312 45.493 6.12 ;
     RECT  44.483 1.728 45.608 1.8 ;
     RECT  45.493 3.312 45.608 6.408 ;
     RECT  44.917 30.48 45.608 31.224 ;
     RECT  44.993 34.224 45.608 34.728 ;
     RECT  45.608 1.728 45.904 34.728 ;
     RECT  45.904 34.224 46.109 34.728 ;
     RECT  45.904 3.936 46.253 6.408 ;
     RECT  45.904 1.728 46.451 2.76 ;
     RECT  46.253 3.936 46.739 6.312 ;
     RECT  46.739 3.936 46.793 6.12 ;
     RECT  45.904 30.192 47.081 30.84 ;
     RECT  46.451 2.736 47.125 2.76 ;
     RECT  47.125 2.736 47.225 2.904 ;
     RECT  47.081 30.192 47.261 30.696 ;
     RECT  47.324 0.528 47.411 0.552 ;
     RECT  46.793 3.936 47.833 4.152 ;
     RECT  46.793 5.184 47.833 6.12 ;
     RECT  46.451 1.728 47.905 1.752 ;
     RECT  47.261 30.48 48.085 30.696 ;
     RECT  47.225 2.88 48.181 2.904 ;
     RECT  47.833 3.936 48.181 6.12 ;
     RECT  46.109 34.224 48.181 34.248 ;
     RECT  47.905 1.728 48.308 1.8 ;
     RECT  48.181 2.88 48.308 6.408 ;
     RECT  48.085 30.48 48.308 31.128 ;
     RECT  48.181 34.224 48.308 34.728 ;
     RECT  48.181 0.192 48.419 0.216 ;
     RECT  48.308 1.728 48.604 34.728 ;
     RECT  48.604 30.576 48.845 31.32 ;
     RECT  48.604 33.648 48.953 33.672 ;
     RECT  48.604 34.656 49.093 34.728 ;
     RECT  48.604 1.728 49.177 1.752 ;
     RECT  48.604 2.832 49.334 6.408 ;
     RECT  49.093 34.656 49.457 34.824 ;
     RECT  49.334 2.88 49.529 6.408 ;
     RECT  48.853 35.904 49.637 35.928 ;
     RECT  48.604 7.44 49.745 7.464 ;
     RECT  49.529 5.088 49.777 6.408 ;
     RECT  49.777 5.088 49.781 6.84 ;
     RECT  48.845 31.104 49.813 31.32 ;
     RECT  49.813 30.816 50.293 31.32 ;
     RECT  49.529 2.88 50.605 4.104 ;
     RECT  50.605 2.832 50.722 4.104 ;
     RECT  50.722 2.784 50.773 4.104 ;
     RECT  49.573 34.224 50.773 34.344 ;
     RECT  50.773 34.224 50.821 34.776 ;
     RECT  50.821 0.528 50.869 0.552 ;
     RECT  50.533 1.728 51.008 1.752 ;
     RECT  50.773 2.784 51.008 4.152 ;
     RECT  49.781 5.136 51.008 6.84 ;
     RECT  50.293 30.192 51.008 31.32 ;
     RECT  50.821 34.224 51.008 34.92 ;
     RECT  50.869 0.192 51.185 0.552 ;
     RECT  51.008 1.728 51.299 34.92 ;
     RECT  51.299 1.728 51.304 34.776 ;
     RECT  51.304 30.576 51.437 30.84 ;
     RECT  51.356 0.144 51.443 0.168 ;
     RECT  51.437 30.672 51.689 30.84 ;
     RECT  51.304 1.728 51.875 6.84 ;
     RECT  51.304 34.656 52.261 34.776 ;
     RECT  52.261 34.656 52.445 35.352 ;
     RECT  52.445 34.656 52.741 34.776 ;
     RECT  51.875 1.728 52.909 2.664 ;
     RECT  52.909 1.728 52.933 2.76 ;
     RECT  51.875 3.744 52.933 6.84 ;
     RECT  53.161 9.696 53.221 9.72 ;
     RECT  52.741 34.224 53.557 34.776 ;
     RECT  53.549 0.528 53.701 0.552 ;
     RECT  52.933 1.728 53.708 6.84 ;
     RECT  53.221 9.696 53.708 10.344 ;
     RECT  51.689 30.816 53.708 30.84 ;
     RECT  53.557 34.224 53.708 34.824 ;
     RECT  53.708 1.728 54.004 34.824 ;
     RECT  53.701 0.192 54.131 0.552 ;
     RECT  54.004 34.368 54.131 34.824 ;
     RECT  54.131 0.288 54.137 0.552 ;
     RECT  54.131 34.368 54.137 34.776 ;
     RECT  54.004 1.728 54.281 7.464 ;
     RECT  54.137 0.288 54.467 0.312 ;
     RECT  54.281 3.312 54.515 7.464 ;
     RECT  54.137 34.752 54.569 34.776 ;
     RECT  54.515 3.36 55.283 7.464 ;
     RECT  54.004 30.192 55.361 31.32 ;
     RECT  54.281 1.728 55.621 2.232 ;
     RECT  55.283 3.36 55.621 6.84 ;
     RECT  55.669 0.192 55.772 0.216 ;
     RECT  55.909 34.8 56.149 34.824 ;
     RECT  56.149 34.224 56.26 34.824 ;
     RECT  55.621 1.728 56.408 6.84 ;
     RECT  56.005 9.696 56.408 9.72 ;
     RECT  55.361 30.192 56.408 30.84 ;
     RECT  56.26 34.224 56.408 34.872 ;
     RECT  56.408 1.728 56.435 34.872 ;
     RECT  55.772 0.192 56.509 0.312 ;
     RECT  56.435 1.728 56.704 34.824 ;
     RECT  56.704 34.224 56.819 34.824 ;
     RECT  56.509 0.144 56.867 0.312 ;
     RECT  56.819 34.224 57.017 34.776 ;
     RECT  56.867 0.144 57.779 0.168 ;
     RECT  57.733 9.696 57.827 9.72 ;
     RECT  56.704 30.192 57.877 30.6 ;
     RECT  57.877 30.192 58.025 30.84 ;
     RECT  57.017 34.752 58.117 34.776 ;
     RECT  56.704 1.728 58.645 7.992 ;
     RECT  58.117 34.224 58.837 34.776 ;
     RECT  58.837 34.176 58.981 34.776 ;
     RECT  58.645 1.728 59.108 8.568 ;
     RECT  58.489 24.336 59.108 24.36 ;
     RECT  58.025 30.48 59.108 30.84 ;
     RECT  58.981 34.176 59.108 34.872 ;
     RECT  59.108 1.728 59.404 34.872 ;
     RECT  58.981 0.192 59.461 0.216 ;
     RECT  59.461 0.192 59.555 0.312 ;
     RECT  59.404 34.752 59.555 34.872 ;
     RECT  59.555 34.752 59.573 34.776 ;
     RECT  59.66 0.144 59.987 0.168 ;
     RECT  59.404 1.728 60.541 7.32 ;
     RECT  60.517 34.8 60.805 34.824 ;
     RECT  59.404 30.48 61.525 30.84 ;
     RECT  60.805 34.752 61.621 34.824 ;
     RECT  61.621 0.288 61.669 0.312 ;
     RECT  60.541 1.728 61.808 7.992 ;
     RECT  61.513 10.032 61.808 10.056 ;
     RECT  61.525 30.48 61.808 31.128 ;
     RECT  61.621 34.752 61.808 34.92 ;
     RECT  61.669 0.192 62.051 0.312 ;
     RECT  61.808 1.728 62.051 34.92 ;
     RECT  62.051 1.728 62.104 34.776 ;
     RECT  62.104 30.576 62.345 31.128 ;
     RECT  62.348 0.144 62.435 0.168 ;
     RECT  62.345 30.576 62.489 30.792 ;
     RECT  62.489 30.672 62.689 30.792 ;
     RECT  62.689 30.72 62.741 30.792 ;
     RECT  62.104 1.728 62.965 6.936 ;
     RECT  62.965 1.152 63.107 6.936 ;
     RECT  63.107 1.728 63.173 6.936 ;
     RECT  63.133 9.696 63.217 9.72 ;
     RECT  62.725 35.904 63.353 35.928 ;
     RECT  63.173 1.728 63.491 6.888 ;
     RECT  63.491 3.888 63.497 6.888 ;
     RECT  62.741 30.72 63.685 30.744 ;
     RECT  63.685 30.192 63.973 30.744 ;
     RECT  62.104 34.752 64.453 34.776 ;
     RECT  63.491 1.728 64.508 2.76 ;
     RECT  63.497 3.888 64.508 6.84 ;
     RECT  63.889 9.12 64.508 9.144 ;
     RECT  63.973 30.192 64.508 30.84 ;
     RECT  64.453 34.752 64.508 34.824 ;
     RECT  64.508 1.728 64.693 34.824 ;
     RECT  64.693 1.728 64.804 34.872 ;
     RECT  64.804 1.728 64.931 7.464 ;
     RECT  64.804 34.224 64.931 34.872 ;
     RECT  64.931 7.44 64.979 7.464 ;
     RECT  64.931 34.224 64.979 34.824 ;
     RECT  64.931 1.728 65.219 6.312 ;
     RECT  65.219 2.736 65.297 6.312 ;
     RECT  64.804 9.696 65.411 9.72 ;
     RECT  64.933 0.288 66.085 0.312 ;
     RECT  66.085 0.288 66.179 0.552 ;
     RECT  66.179 0.288 66.227 0.312 ;
     RECT  65.219 1.728 66.293 1.752 ;
     RECT  65.297 2.736 66.293 5.88 ;
     RECT  64.979 34.8 66.373 34.824 ;
     RECT  66.373 34.224 66.521 34.824 ;
     RECT  65.893 30.672 66.613 30.696 ;
     RECT  66.613 30.192 66.661 30.696 ;
     RECT  66.293 1.728 66.953 5.88 ;
     RECT  66.953 2.148 67.208 5.88 ;
     RECT  66.661 30.192 67.208 30.792 ;
     RECT  66.521 34.224 67.208 34.572 ;
     RECT  67.208 2.148 67.312 34.572 ;
     RECT  67.312 2.418 67.504 34.302 ;
     RECT  65.413 35.904 67.601 35.928 ;
     RECT  67.504 2.88 67.673 5.496 ;
     RECT  67.673 2.88 67.811 4.68 ;
     RECT  67.811 2.88 67.889 3.96 ;
     RECT  67.889 2.88 68.105 2.904 ;
    LAYER M5 ;
     RECT  15.6 0.133 15.624 0.144 ;
     RECT  16.848 0.133 16.872 0.144 ;
     RECT  28.032 0.133 28.056 0.144 ;
     RECT  36.288 0.133 36.312 0.144 ;
     RECT  42.432 0.133 42.456 0.144 ;
     RECT  51.408 0.133 51.432 0.144 ;
     RECT  56.784 0.133 56.88 0.144 ;
     RECT  56.904 0.133 57.12 0.144 ;
     RECT  57.144 0.133 57.36 0.144 ;
     RECT  57.384 0.133 57.648 0.144 ;
     RECT  57.672 0.133 57.768 0.144 ;
     RECT  62.4 0.133 62.424 0.144 ;
     RECT  4.536 0.144 4.752 0.192 ;
     RECT  4.776 0.144 4.992 0.192 ;
     RECT  5.016 0.144 5.232 0.192 ;
     RECT  5.256 0.144 5.472 0.192 ;
     RECT  5.496 0.144 5.712 0.192 ;
     RECT  5.736 0.144 5.952 0.192 ;
     RECT  5.976 0.144 6.192 0.192 ;
     RECT  6.216 0.144 6.432 0.192 ;
     RECT  6.456 0.144 6.672 0.192 ;
     RECT  6.696 0.144 6.912 0.192 ;
     RECT  6.936 0.144 7.152 0.192 ;
     RECT  7.176 0.144 7.392 0.192 ;
     RECT  7.416 0.144 7.68 0.192 ;
     RECT  7.704 0.144 7.92 0.192 ;
     RECT  7.944 0.144 8.16 0.192 ;
     RECT  8.184 0.144 8.4 0.192 ;
     RECT  8.424 0.144 8.64 0.192 ;
     RECT  8.664 0.144 8.88 0.192 ;
     RECT  8.904 0.144 9.12 0.192 ;
     RECT  9.144 0.144 9.36 0.192 ;
     RECT  9.384 0.144 9.6 0.192 ;
     RECT  9.624 0.144 9.84 0.192 ;
     RECT  9.864 0.144 10.08 0.192 ;
     RECT  10.104 0.144 10.32 0.192 ;
     RECT  10.344 0.144 10.608 0.192 ;
     RECT  10.632 0.144 10.848 0.192 ;
     RECT  10.872 0.144 11.088 0.192 ;
     RECT  11.112 0.144 11.328 0.192 ;
     RECT  11.352 0.144 11.568 0.192 ;
     RECT  11.592 0.144 11.808 0.192 ;
     RECT  11.832 0.144 12.048 0.192 ;
     RECT  12.072 0.144 12.288 0.192 ;
     RECT  12.312 0.144 12.528 0.192 ;
     RECT  12.552 0.144 12.768 0.192 ;
     RECT  12.792 0.144 13.008 0.192 ;
     RECT  13.032 0.144 13.248 0.192 ;
     RECT  13.272 0.144 13.488 0.192 ;
     RECT  13.512 0.144 13.776 0.192 ;
     RECT  13.8 0.144 14.016 0.192 ;
     RECT  14.04 0.144 14.256 0.192 ;
     RECT  14.28 0.144 14.496 0.192 ;
     RECT  14.52 0.144 14.736 0.192 ;
     RECT  14.76 0.144 14.976 0.192 ;
     RECT  15 0.144 15.216 0.192 ;
     RECT  15.24 0.144 15.456 0.192 ;
     RECT  15.48 0.144 15.696 0.192 ;
     RECT  15.72 0.144 15.936 0.192 ;
     RECT  15.96 0.144 16.176 0.192 ;
     RECT  16.2 0.144 16.416 0.192 ;
     RECT  16.44 0.144 16.656 0.192 ;
     RECT  16.68 0.144 16.944 0.192 ;
     RECT  16.968 0.144 17.184 0.192 ;
     RECT  17.208 0.144 17.424 0.192 ;
     RECT  17.448 0.144 17.664 0.192 ;
     RECT  17.688 0.144 17.904 0.192 ;
     RECT  17.928 0.144 18.144 0.192 ;
     RECT  18.168 0.144 18.384 0.192 ;
     RECT  18.408 0.144 18.624 0.192 ;
     RECT  18.648 0.144 18.864 0.192 ;
     RECT  18.888 0.144 19.104 0.192 ;
     RECT  19.128 0.144 19.344 0.192 ;
     RECT  19.368 0.144 19.584 0.192 ;
     RECT  19.608 0.144 19.824 0.192 ;
     RECT  19.848 0.144 20.112 0.192 ;
     RECT  20.136 0.144 20.352 0.192 ;
     RECT  20.376 0.144 20.592 0.192 ;
     RECT  20.616 0.144 20.832 0.192 ;
     RECT  20.856 0.144 21.072 0.192 ;
     RECT  21.096 0.144 21.312 0.192 ;
     RECT  21.336 0.144 21.552 0.192 ;
     RECT  21.576 0.144 21.792 0.192 ;
     RECT  21.816 0.144 22.032 0.192 ;
     RECT  22.056 0.144 22.272 0.192 ;
     RECT  22.296 0.144 22.512 0.192 ;
     RECT  22.536 0.144 22.752 0.192 ;
     RECT  22.776 0.144 22.992 0.192 ;
     RECT  23.016 0.144 23.28 0.192 ;
     RECT  23.304 0.144 23.52 0.192 ;
     RECT  23.544 0.144 23.76 0.192 ;
     RECT  23.784 0.144 24 0.192 ;
     RECT  24.024 0.144 24.24 0.192 ;
     RECT  24.264 0.144 24.48 0.192 ;
     RECT  24.504 0.144 24.72 0.192 ;
     RECT  24.744 0.144 24.96 0.192 ;
     RECT  24.984 0.144 25.2 0.192 ;
     RECT  25.224 0.144 25.44 0.192 ;
     RECT  25.464 0.144 25.68 0.192 ;
     RECT  25.704 0.144 25.92 0.192 ;
     RECT  25.944 0.144 26.16 0.192 ;
     RECT  26.184 0.144 26.448 0.192 ;
     RECT  26.472 0.144 26.688 0.192 ;
     RECT  26.712 0.144 26.928 0.192 ;
     RECT  26.952 0.144 27.168 0.192 ;
     RECT  27.192 0.144 27.408 0.192 ;
     RECT  27.432 0.144 27.648 0.192 ;
     RECT  27.672 0.144 27.888 0.192 ;
     RECT  27.912 0.144 28.128 0.192 ;
     RECT  28.152 0.144 28.368 0.192 ;
     RECT  28.392 0.144 28.608 0.192 ;
     RECT  28.632 0.144 28.848 0.192 ;
     RECT  28.872 0.144 29.088 0.192 ;
     RECT  29.112 0.144 29.328 0.192 ;
     RECT  29.352 0.144 29.616 0.192 ;
     RECT  29.64 0.144 29.856 0.192 ;
     RECT  29.88 0.144 30.096 0.192 ;
     RECT  30.12 0.144 30.336 0.192 ;
     RECT  30.36 0.144 30.576 0.192 ;
     RECT  30.6 0.144 30.816 0.192 ;
     RECT  30.84 0.144 31.056 0.192 ;
     RECT  31.08 0.144 31.296 0.192 ;
     RECT  31.32 0.144 31.536 0.192 ;
     RECT  31.56 0.144 31.776 0.192 ;
     RECT  31.8 0.144 32.016 0.192 ;
     RECT  32.04 0.144 32.256 0.192 ;
     RECT  32.28 0.144 32.544 0.192 ;
     RECT  32.568 0.144 32.784 0.192 ;
     RECT  32.808 0.144 33.024 0.192 ;
     RECT  33.048 0.144 33.264 0.192 ;
     RECT  33.288 0.144 33.504 0.192 ;
     RECT  33.528 0.144 33.744 0.192 ;
     RECT  33.768 0.144 33.984 0.192 ;
     RECT  34.008 0.144 34.224 0.192 ;
     RECT  34.248 0.144 34.464 0.192 ;
     RECT  34.488 0.144 34.704 0.192 ;
     RECT  34.728 0.144 34.944 0.192 ;
     RECT  34.968 0.144 35.184 0.192 ;
     RECT  35.208 0.144 35.424 0.192 ;
     RECT  35.448 0.144 35.712 0.192 ;
     RECT  35.736 0.144 35.952 0.192 ;
     RECT  35.976 0.144 36.192 0.192 ;
     RECT  36.216 0.144 36.432 0.192 ;
     RECT  36.456 0.144 36.672 0.192 ;
     RECT  36.696 0.144 36.912 0.192 ;
     RECT  36.936 0.144 37.152 0.192 ;
     RECT  37.176 0.144 37.392 0.192 ;
     RECT  37.416 0.144 37.632 0.192 ;
     RECT  37.656 0.144 37.872 0.192 ;
     RECT  37.896 0.144 38.112 0.192 ;
     RECT  38.136 0.144 38.352 0.192 ;
     RECT  38.376 0.144 38.592 0.192 ;
     RECT  38.616 0.144 38.88 0.192 ;
     RECT  38.904 0.144 39.12 0.192 ;
     RECT  39.144 0.144 39.36 0.192 ;
     RECT  39.384 0.144 39.6 0.192 ;
     RECT  39.624 0.144 39.84 0.192 ;
     RECT  39.864 0.144 40.08 0.192 ;
     RECT  40.104 0.144 40.32 0.192 ;
     RECT  40.344 0.144 40.56 0.192 ;
     RECT  40.584 0.144 40.8 0.192 ;
     RECT  40.824 0.144 41.04 0.192 ;
     RECT  41.064 0.144 41.28 0.192 ;
     RECT  41.304 0.144 41.52 0.192 ;
     RECT  41.544 0.144 41.76 0.192 ;
     RECT  41.784 0.144 42.048 0.192 ;
     RECT  42.072 0.144 42.288 0.192 ;
     RECT  42.312 0.144 42.528 0.192 ;
     RECT  42.552 0.144 42.768 0.192 ;
     RECT  42.792 0.144 43.008 0.192 ;
     RECT  43.032 0.144 43.248 0.192 ;
     RECT  43.272 0.144 43.488 0.192 ;
     RECT  43.512 0.144 43.728 0.192 ;
     RECT  43.752 0.144 43.968 0.192 ;
     RECT  43.992 0.144 44.208 0.192 ;
     RECT  44.232 0.144 44.448 0.192 ;
     RECT  44.472 0.144 44.688 0.192 ;
     RECT  44.712 0.144 44.928 0.192 ;
     RECT  44.952 0.144 45.216 0.192 ;
     RECT  45.24 0.144 45.456 0.192 ;
     RECT  45.48 0.144 45.696 0.192 ;
     RECT  45.72 0.144 45.936 0.192 ;
     RECT  45.96 0.144 46.176 0.192 ;
     RECT  46.2 0.144 46.416 0.192 ;
     RECT  46.44 0.144 46.656 0.192 ;
     RECT  46.68 0.144 46.896 0.192 ;
     RECT  46.92 0.144 47.136 0.192 ;
     RECT  47.16 0.144 47.376 0.192 ;
     RECT  47.4 0.144 47.616 0.192 ;
     RECT  47.64 0.144 47.856 0.192 ;
     RECT  47.88 0.144 48.096 0.192 ;
     RECT  48.12 0.144 48.384 0.192 ;
     RECT  48.408 0.144 48.624 0.192 ;
     RECT  48.648 0.144 48.864 0.192 ;
     RECT  48.888 0.144 49.104 0.192 ;
     RECT  49.128 0.144 49.344 0.192 ;
     RECT  49.368 0.144 49.584 0.192 ;
     RECT  49.608 0.144 49.824 0.192 ;
     RECT  49.848 0.144 50.064 0.192 ;
     RECT  50.088 0.144 50.304 0.192 ;
     RECT  50.328 0.144 50.544 0.192 ;
     RECT  50.568 0.144 50.784 0.192 ;
     RECT  50.808 0.144 51.024 0.192 ;
     RECT  51.048 0.144 51.264 0.192 ;
     RECT  51.288 0.144 51.552 0.192 ;
     RECT  51.576 0.144 51.792 0.192 ;
     RECT  51.816 0.144 52.032 0.192 ;
     RECT  52.056 0.144 52.272 0.192 ;
     RECT  52.296 0.144 52.512 0.192 ;
     RECT  52.536 0.144 52.752 0.192 ;
     RECT  52.776 0.144 52.992 0.192 ;
     RECT  53.016 0.144 53.232 0.192 ;
     RECT  53.256 0.144 53.472 0.192 ;
     RECT  53.496 0.144 53.712 0.192 ;
     RECT  53.736 0.144 53.952 0.192 ;
     RECT  53.976 0.144 54.192 0.192 ;
     RECT  54.216 0.144 54.48 0.192 ;
     RECT  54.504 0.144 54.72 0.192 ;
     RECT  54.744 0.144 54.96 0.192 ;
     RECT  54.984 0.144 55.2 0.192 ;
     RECT  55.224 0.144 55.44 0.192 ;
     RECT  55.464 0.144 55.68 0.192 ;
     RECT  55.704 0.144 55.92 0.192 ;
     RECT  55.944 0.144 56.16 0.192 ;
     RECT  56.184 0.144 56.4 0.192 ;
     RECT  56.424 0.144 56.64 0.192 ;
     RECT  56.664 0.144 56.88 0.192 ;
     RECT  56.904 0.144 57.12 0.192 ;
     RECT  57.144 0.144 57.36 0.192 ;
     RECT  57.384 0.144 57.648 0.192 ;
     RECT  57.672 0.144 57.888 0.192 ;
     RECT  57.912 0.144 58.128 0.192 ;
     RECT  58.152 0.144 58.368 0.192 ;
     RECT  58.392 0.144 58.608 0.192 ;
     RECT  58.632 0.144 58.848 0.192 ;
     RECT  58.872 0.144 59.088 0.192 ;
     RECT  59.112 0.144 59.328 0.192 ;
     RECT  59.352 0.144 59.568 0.192 ;
     RECT  59.592 0.144 59.808 0.192 ;
     RECT  59.832 0.144 60.048 0.192 ;
     RECT  60.072 0.144 60.288 0.192 ;
     RECT  60.312 0.144 60.528 0.192 ;
     RECT  60.552 0.144 60.816 0.192 ;
     RECT  60.84 0.144 61.056 0.192 ;
     RECT  61.08 0.144 61.296 0.192 ;
     RECT  61.32 0.144 61.536 0.192 ;
     RECT  61.56 0.144 61.776 0.192 ;
     RECT  61.8 0.144 62.016 0.192 ;
     RECT  62.04 0.144 62.256 0.192 ;
     RECT  62.28 0.144 62.496 0.192 ;
     RECT  62.52 0.144 62.736 0.192 ;
     RECT  62.76 0.144 62.976 0.192 ;
     RECT  63 0.144 63.216 0.192 ;
     RECT  63.24 0.144 63.456 0.192 ;
     RECT  63.48 0.144 63.696 0.192 ;
     RECT  63.72 0.144 63.984 0.192 ;
     RECT  64.008 0.144 64.224 0.192 ;
     RECT  64.248 0.144 64.464 0.192 ;
     RECT  64.488 0.144 64.704 0.192 ;
     RECT  64.728 0.144 64.944 0.192 ;
     RECT  64.968 0.144 65.184 0.192 ;
     RECT  65.208 0.144 65.424 0.192 ;
     RECT  65.448 0.144 65.664 0.192 ;
     RECT  65.688 0.144 65.904 0.192 ;
     RECT  65.928 0.144 66.144 0.192 ;
     RECT  66.168 0.144 66.384 0.192 ;
     RECT  66.408 0.144 66.624 0.192 ;
     RECT  66.648 0.144 66.864 0.192 ;
     RECT  4.512 0.192 66.888 1.763 ;
     RECT  5.1 1.763 14.28 1.811 ;
     RECT  15.6 1.763 65.208 1.811 ;
     RECT  15.6 1.811 47.16 1.859 ;
     RECT  66.192 1.763 66.888 2.137 ;
     RECT  2.4 2.137 2.52 2.151 ;
     RECT  66.192 2.137 67.32 2.151 ;
     RECT  5.1 1.811 6.216 2.291 ;
     RECT  7.392 1.811 10.812 2.291 ;
     RECT  15.6 1.859 43.32 2.291 ;
     RECT  15.6 2.291 33.528 2.339 ;
     RECT  48.192 1.811 65.208 2.339 ;
     RECT  52.944 2.339 65.208 2.725 ;
     RECT  66.192 2.151 67.512 2.725 ;
     RECT  5.1 2.291 5.976 2.915 ;
     RECT  11.808 1.811 14.28 2.915 ;
     RECT  15.744 2.339 33.528 2.915 ;
     RECT  44.448 1.859 47.16 2.915 ;
     RECT  7.536 2.291 10.812 2.963 ;
     RECT  12.048 2.915 13.8 3.011 ;
     RECT  48.192 2.339 51.816 3.059 ;
     RECT  12.048 3.011 13.656 3.347 ;
     RECT  13.2 3.347 13.656 3.395 ;
     RECT  5.1 2.915 5.412 3.397 ;
     RECT  15.744 2.915 29.832 3.397 ;
     RECT  48.3 3.059 51.816 3.397 ;
     RECT  7.632 2.963 10.812 3.443 ;
     RECT  30.816 2.915 33 3.443 ;
     RECT  34.704 2.291 43.32 3.443 ;
     RECT  44.448 2.915 46.44 3.443 ;
     RECT  48.3 3.397 51.864 3.443 ;
     RECT  7.632 3.443 9 3.539 ;
     RECT  15.36 3.397 29.832 3.683 ;
     RECT  50.688 3.443 51.864 3.733 ;
     RECT  52.944 2.725 67.512 3.733 ;
     RECT  50.688 3.733 67.512 3.925 ;
     RECT  15.36 3.683 29.712 4.067 ;
     RECT  4.704 3.397 5.412 4.115 ;
     RECT  44.448 3.443 44.472 4.115 ;
     RECT  31.536 3.443 33 4.117 ;
     RECT  34.704 3.443 35.208 4.117 ;
     RECT  36.72 3.443 43.32 4.261 ;
     RECT  15.36 4.067 27.384 4.403 ;
     RECT  12.048 3.347 12.216 4.501 ;
     RECT  13.2 3.395 13.512 4.501 ;
     RECT  12.048 4.501 13.512 4.595 ;
     RECT  15.9 4.403 27.384 4.595 ;
     RECT  31.536 4.117 35.208 4.595 ;
     RECT  50.688 3.925 67.8 4.595 ;
     RECT  20.16 4.595 27.384 4.643 ;
     RECT  34.704 4.595 35.208 4.643 ;
     RECT  7.8 3.539 9 4.645 ;
     RECT  66.624 4.595 67.8 4.691 ;
     RECT  20.496 4.643 27.384 4.739 ;
     RECT  7.68 4.645 9 5.029 ;
     RECT  45.6 3.443 46.44 5.077 ;
     RECT  15.9 4.595 19.176 5.171 ;
     RECT  31.536 4.595 33.624 5.171 ;
     RECT  36.72 4.261 43.896 5.171 ;
     RECT  50.688 4.595 65.448 5.171 ;
     RECT  48.3 3.443 49.272 5.173 ;
     RECT  38.976 5.171 43.896 5.219 ;
     RECT  31.824 5.171 33.624 5.267 ;
     RECT  48.192 5.173 49.272 5.365 ;
     RECT  38.976 5.219 41.592 5.459 ;
     RECT  7.68 5.029 9.048 5.461 ;
     RECT  10.176 3.443 10.812 5.461 ;
     RECT  7.68 5.461 10.812 5.747 ;
     RECT  21.12 4.739 27.384 5.747 ;
     RECT  50.832 5.171 65.448 5.747 ;
     RECT  66.624 4.691 67.512 5.747 ;
     RECT  4.992 4.115 5.412 5.795 ;
     RECT  7.8 5.747 10.812 5.795 ;
     RECT  50.832 5.747 51.312 5.795 ;
     RECT  52.416 5.747 65.448 5.795 ;
     RECT  9.6 5.795 10.812 5.845 ;
     RECT  12.192 4.595 13.512 5.845 ;
     RECT  21.12 5.747 27.144 5.939 ;
     RECT  45.6 5.077 46.776 5.987 ;
     RECT  21.12 5.939 27.012 6.227 ;
     RECT  9.6 5.845 13.512 6.275 ;
     RECT  10.176 6.275 13.512 6.323 ;
     RECT  21.168 6.227 27.012 6.323 ;
     RECT  28.464 4.067 29.712 6.323 ;
     RECT  31.968 5.267 33.624 6.323 ;
     RECT  36.72 5.171 37.812 6.323 ;
     RECT  39.312 5.459 41.592 6.323 ;
     RECT  45.6 5.987 46.728 6.323 ;
     RECT  52.416 5.795 65.4 6.323 ;
     RECT  21.168 6.323 25.128 6.371 ;
     RECT  55.248 6.323 65.4 6.371 ;
     RECT  48.192 5.365 49.416 6.419 ;
     RECT  63.12 6.371 65.4 6.467 ;
     RECT  32.1 6.323 33.624 6.515 ;
     RECT  39.312 6.323 41.4 6.563 ;
     RECT  21.168 6.371 22.824 6.659 ;
     RECT  10.176 6.323 10.812 6.803 ;
     RECT  63.12 6.467 63.192 6.803 ;
     RECT  12.192 6.323 13.512 6.851 ;
     RECT  15.9 5.171 18.912 6.899 ;
     RECT  21.168 6.659 22.44 6.899 ;
     RECT  28.512 6.323 29.712 6.899 ;
     RECT  33.6 6.515 33.624 6.899 ;
     RECT  37.104 6.323 37.812 6.899 ;
     RECT  39.312 6.563 40.68 6.899 ;
     RECT  55.248 6.371 62.112 6.995 ;
     RECT  34.8 4.643 35.208 7.237 ;
     RECT  60.432 6.995 62.112 7.331 ;
     RECT  17.952 6.899 18.912 7.475 ;
     RECT  48.3 6.419 49.416 7.475 ;
     RECT  55.248 6.995 59.412 7.475 ;
     RECT  56.016 7.475 59.412 8.003 ;
     RECT  60.96 7.331 62.112 8.003 ;
     RECT  57.792 8.003 59.412 8.579 ;
     RECT  40.2 6.899 40.68 9.155 ;
     RECT  64.272 6.467 65.4 9.155 ;
     RECT  15.9 6.899 16.344 9.731 ;
     RECT  21.3 6.899 22.44 9.731 ;
     RECT  24 6.371 25.128 9.731 ;
     RECT  34.8 7.237 35.88 9.731 ;
     RECT  42.624 5.219 43.212 9.731 ;
     RECT  56.016 8.003 56.712 9.731 ;
     RECT  57.792 8.579 57.816 9.731 ;
     RECT  63.168 6.803 63.192 9.731 ;
     RECT  64.5 9.155 65.4 9.731 ;
     RECT  24 9.731 24.408 9.827 ;
     RECT  53.232 6.323 54.012 10.355 ;
     RECT  0.24 6.085 0.264 18.419 ;
     RECT  34.8 9.731 35.112 30.133 ;
     RECT  37.5 6.899 37.812 30.133 ;
     RECT  5.1 5.795 5.412 30.181 ;
     RECT  10.5 6.803 10.812 30.181 ;
     RECT  13.2 6.851 13.512 30.181 ;
     RECT  21.3 9.731 21.612 30.181 ;
     RECT  26.7 6.323 27.012 30.181 ;
     RECT  45.6 6.323 45.912 30.181 ;
     RECT  51 5.795 51.312 30.181 ;
     RECT  53.7 10.355 54.012 30.181 ;
     RECT  56.4 9.731 56.712 30.181 ;
     RECT  64.5 9.731 64.812 30.181 ;
     RECT  67.2 5.747 67.512 30.181 ;
     RECT  18.6 7.475 18.912 30.421 ;
     RECT  40.2 9.155 40.512 30.421 ;
     RECT  7.8 5.795 8.112 30.469 ;
     RECT  9.12 30.181 9.144 30.469 ;
     RECT  10.5 30.181 11.112 30.469 ;
     RECT  21.3 30.181 22.536 30.469 ;
     RECT  37.152 30.133 37.812 30.469 ;
     RECT  45.6 30.181 46.44 30.469 ;
     RECT  53.7 30.181 54.984 30.469 ;
     RECT  56.4 30.181 57.384 30.469 ;
     RECT  59.1 8.579 59.412 30.469 ;
     RECT  61.8 8.003 62.112 30.469 ;
     RECT  24 9.827 24.312 30.565 ;
     RECT  26.7 30.181 27.672 30.565 ;
     RECT  37.152 30.469 37.944 30.565 ;
     RECT  48.3 7.475 48.612 30.565 ;
     RECT  7.8 30.469 9.144 30.613 ;
     RECT  5.1 30.181 5.976 30.661 ;
     RECT  7.632 30.613 9.144 30.661 ;
     RECT  10.5 30.469 11.832 30.661 ;
     RECT  13.2 30.181 14.28 30.661 ;
     RECT  17.904 30.421 19.128 30.661 ;
     RECT  20.832 30.469 22.776 30.661 ;
     RECT  23.76 30.565 24.312 30.661 ;
     RECT  44.688 30.469 47.16 30.661 ;
     RECT  48.192 30.565 48.612 30.661 ;
     RECT  58.368 30.469 62.112 30.661 ;
     RECT  66.624 30.181 67.512 30.661 ;
     RECT  7.392 30.661 9.144 30.709 ;
     RECT  10.5 30.661 14.28 30.709 ;
     RECT  17.904 30.661 19.608 30.709 ;
     RECT  20.592 30.661 24.312 30.709 ;
     RECT  25.44 30.469 25.464 30.709 ;
     RECT  26.592 30.565 27.672 30.709 ;
     RECT  29.4 6.899 29.712 30.709 ;
     RECT  32.1 6.515 32.412 30.709 ;
     RECT  34.224 30.133 35.112 30.709 ;
     RECT  36.672 30.565 37.944 30.709 ;
     RECT  40.2 30.421 40.824 30.709 ;
     RECT  42.9 9.731 43.212 30.709 ;
     RECT  58.368 30.661 62.664 30.709 ;
     RECT  63.696 30.181 64.812 30.709 ;
     RECT  4.992 30.661 5.976 30.757 ;
     RECT  7.152 30.709 14.28 30.757 ;
     RECT  17.904 30.709 24.312 30.805 ;
     RECT  25.44 30.709 27.672 30.805 ;
     RECT  31.776 30.709 38.616 30.805 ;
     RECT  40.2 30.709 41.064 30.805 ;
     RECT  42.9 30.709 43.512 30.805 ;
     RECT  44.688 30.661 48.612 30.805 ;
     RECT  50.304 30.181 51.312 30.805 ;
     RECT  53.7 30.469 57.384 30.805 ;
     RECT  58.368 30.709 64.812 30.805 ;
     RECT  15.9 9.731 16.212 30.997 ;
     RECT  17.184 30.805 24.312 30.997 ;
     RECT  31.296 30.805 38.616 30.997 ;
     RECT  29.4 30.709 30.12 31.093 ;
     RECT  4.992 30.757 14.76 31.189 ;
     RECT  15.9 30.997 24.312 31.189 ;
     RECT  40.2 30.805 41.784 31.285 ;
     RECT  42.9 30.805 48.612 31.285 ;
     RECT  49.824 30.805 64.812 31.285 ;
     RECT  4.992 31.189 24.312 34.165 ;
     RECT  4.752 34.165 24.312 34.213 ;
     RECT  25.44 30.805 28.152 34.213 ;
     RECT  29.28 31.093 30.12 34.213 ;
     RECT  31.296 30.997 39.144 34.213 ;
     RECT  40.2 31.285 64.812 34.213 ;
     RECT  65.904 30.661 67.512 34.213 ;
     RECT  2.4 2.151 2.712 34.569 ;
     RECT  4.752 34.213 67.512 34.569 ;
     RECT  2.4 34.569 2.52 34.583 ;
     RECT  4.752 34.569 67.32 34.583 ;
     RECT  4.752 34.583 66.648 34.741 ;
     RECT  4.512 34.741 66.648 35.893 ;
     RECT  4.512 35.893 66.888 36.528 ;
     RECT  4.536 36.528 4.752 36.56 ;
     RECT  4.776 36.528 4.992 36.56 ;
     RECT  5.016 36.528 5.232 36.56 ;
     RECT  5.256 36.528 5.472 36.56 ;
     RECT  5.496 36.528 5.712 36.56 ;
     RECT  5.736 36.528 5.952 36.56 ;
     RECT  5.976 36.528 6.192 36.56 ;
     RECT  6.216 36.528 6.432 36.56 ;
     RECT  6.456 36.528 6.672 36.56 ;
     RECT  6.696 36.528 6.912 36.56 ;
     RECT  6.936 36.528 7.152 36.56 ;
     RECT  7.176 36.528 7.392 36.56 ;
     RECT  7.416 36.528 7.68 36.56 ;
     RECT  7.704 36.528 7.92 36.56 ;
     RECT  7.944 36.528 8.16 36.56 ;
     RECT  8.184 36.528 8.4 36.56 ;
     RECT  8.424 36.528 8.64 36.56 ;
     RECT  8.664 36.528 8.88 36.56 ;
     RECT  8.904 36.528 9.12 36.56 ;
     RECT  9.144 36.528 9.36 36.56 ;
     RECT  9.384 36.528 9.6 36.56 ;
     RECT  9.624 36.528 9.84 36.56 ;
     RECT  9.864 36.528 10.08 36.56 ;
     RECT  10.104 36.528 10.32 36.56 ;
     RECT  10.344 36.528 10.608 36.56 ;
     RECT  10.632 36.528 10.848 36.56 ;
     RECT  10.872 36.528 11.088 36.56 ;
     RECT  11.112 36.528 11.328 36.56 ;
     RECT  11.352 36.528 11.568 36.56 ;
     RECT  11.592 36.528 11.808 36.56 ;
     RECT  11.832 36.528 12.048 36.56 ;
     RECT  12.072 36.528 12.288 36.56 ;
     RECT  12.312 36.528 12.528 36.56 ;
     RECT  12.552 36.528 12.768 36.56 ;
     RECT  12.792 36.528 13.008 36.56 ;
     RECT  13.032 36.528 13.248 36.56 ;
     RECT  13.272 36.528 13.488 36.56 ;
     RECT  13.512 36.528 13.776 36.56 ;
     RECT  13.8 36.528 14.016 36.56 ;
     RECT  14.04 36.528 14.256 36.56 ;
     RECT  14.28 36.528 14.496 36.56 ;
     RECT  14.52 36.528 14.736 36.56 ;
     RECT  14.76 36.528 14.976 36.56 ;
     RECT  15 36.528 15.216 36.56 ;
     RECT  15.24 36.528 15.456 36.56 ;
     RECT  15.48 36.528 15.696 36.56 ;
     RECT  15.72 36.528 15.936 36.56 ;
     RECT  15.96 36.528 16.176 36.56 ;
     RECT  16.2 36.528 16.416 36.56 ;
     RECT  16.44 36.528 16.656 36.56 ;
     RECT  16.68 36.528 16.944 36.56 ;
     RECT  16.968 36.528 17.184 36.56 ;
     RECT  17.208 36.528 17.424 36.56 ;
     RECT  17.448 36.528 17.664 36.56 ;
     RECT  17.688 36.528 17.904 36.56 ;
     RECT  17.928 36.528 18.144 36.56 ;
     RECT  18.168 36.528 18.384 36.56 ;
     RECT  18.408 36.528 18.624 36.56 ;
     RECT  18.648 36.528 18.864 36.56 ;
     RECT  18.888 36.528 19.104 36.56 ;
     RECT  19.128 36.528 19.344 36.56 ;
     RECT  19.368 36.528 19.584 36.56 ;
     RECT  19.608 36.528 19.824 36.56 ;
     RECT  19.848 36.528 20.112 36.56 ;
     RECT  20.136 36.528 20.352 36.56 ;
     RECT  20.376 36.528 20.592 36.56 ;
     RECT  20.616 36.528 20.832 36.56 ;
     RECT  20.856 36.528 21.072 36.56 ;
     RECT  21.096 36.528 21.312 36.56 ;
     RECT  21.336 36.528 21.552 36.56 ;
     RECT  21.576 36.528 21.792 36.56 ;
     RECT  21.816 36.528 22.032 36.56 ;
     RECT  22.056 36.528 22.272 36.56 ;
     RECT  22.296 36.528 22.512 36.56 ;
     RECT  22.536 36.528 22.752 36.56 ;
     RECT  22.776 36.528 22.992 36.56 ;
     RECT  23.016 36.528 23.28 36.56 ;
     RECT  23.304 36.528 23.52 36.56 ;
     RECT  23.544 36.528 23.76 36.56 ;
     RECT  23.784 36.528 24 36.56 ;
     RECT  24.024 36.528 24.24 36.56 ;
     RECT  24.264 36.528 24.48 36.56 ;
     RECT  24.504 36.528 24.72 36.56 ;
     RECT  24.744 36.528 24.96 36.56 ;
     RECT  24.984 36.528 25.2 36.56 ;
     RECT  25.224 36.528 25.44 36.56 ;
     RECT  25.464 36.528 25.68 36.56 ;
     RECT  25.704 36.528 25.92 36.56 ;
     RECT  25.944 36.528 26.16 36.56 ;
     RECT  26.184 36.528 26.448 36.56 ;
     RECT  26.472 36.528 26.688 36.56 ;
     RECT  26.712 36.528 26.928 36.56 ;
     RECT  26.952 36.528 27.168 36.56 ;
     RECT  27.192 36.528 27.408 36.56 ;
     RECT  27.432 36.528 27.648 36.56 ;
     RECT  27.672 36.528 27.888 36.56 ;
     RECT  27.912 36.528 28.128 36.56 ;
     RECT  28.152 36.528 28.368 36.56 ;
     RECT  28.392 36.528 28.608 36.56 ;
     RECT  28.632 36.528 28.848 36.56 ;
     RECT  28.872 36.528 29.088 36.56 ;
     RECT  29.112 36.528 29.328 36.56 ;
     RECT  29.352 36.528 29.616 36.56 ;
     RECT  29.64 36.528 29.856 36.56 ;
     RECT  29.88 36.528 30.096 36.56 ;
     RECT  30.12 36.528 30.336 36.56 ;
     RECT  30.36 36.528 30.576 36.56 ;
     RECT  30.6 36.528 30.816 36.56 ;
     RECT  30.84 36.528 31.056 36.56 ;
     RECT  31.08 36.528 31.296 36.56 ;
     RECT  31.32 36.528 31.536 36.56 ;
     RECT  31.56 36.528 31.776 36.56 ;
     RECT  31.8 36.528 32.016 36.56 ;
     RECT  32.04 36.528 32.256 36.56 ;
     RECT  32.28 36.528 32.544 36.56 ;
     RECT  32.568 36.528 32.784 36.56 ;
     RECT  32.808 36.528 33.024 36.56 ;
     RECT  33.048 36.528 33.264 36.56 ;
     RECT  33.288 36.528 33.504 36.56 ;
     RECT  33.528 36.528 33.744 36.56 ;
     RECT  33.768 36.528 33.984 36.56 ;
     RECT  34.008 36.528 34.224 36.56 ;
     RECT  34.248 36.528 34.464 36.56 ;
     RECT  34.488 36.528 34.704 36.56 ;
     RECT  34.728 36.528 34.944 36.56 ;
     RECT  34.968 36.528 35.184 36.56 ;
     RECT  35.208 36.528 35.424 36.56 ;
     RECT  35.448 36.528 35.712 36.56 ;
     RECT  35.736 36.528 35.952 36.56 ;
     RECT  35.976 36.528 36.192 36.56 ;
     RECT  36.216 36.528 36.432 36.56 ;
     RECT  36.456 36.528 36.672 36.56 ;
     RECT  36.696 36.528 36.912 36.56 ;
     RECT  36.936 36.528 37.152 36.56 ;
     RECT  37.176 36.528 37.392 36.56 ;
     RECT  37.416 36.528 37.632 36.56 ;
     RECT  37.656 36.528 37.872 36.56 ;
     RECT  37.896 36.528 38.112 36.56 ;
     RECT  38.136 36.528 38.352 36.56 ;
     RECT  38.376 36.528 38.592 36.56 ;
     RECT  38.616 36.528 38.88 36.56 ;
     RECT  38.904 36.528 39.12 36.56 ;
     RECT  39.144 36.528 39.36 36.56 ;
     RECT  39.384 36.528 39.6 36.56 ;
     RECT  39.624 36.528 39.84 36.56 ;
     RECT  39.864 36.528 40.08 36.56 ;
     RECT  40.104 36.528 40.32 36.56 ;
     RECT  40.344 36.528 40.56 36.56 ;
     RECT  40.584 36.528 40.8 36.56 ;
     RECT  40.824 36.528 41.04 36.56 ;
     RECT  41.064 36.528 41.28 36.56 ;
     RECT  41.304 36.528 41.52 36.56 ;
     RECT  41.544 36.528 41.76 36.56 ;
     RECT  41.784 36.528 42.048 36.56 ;
     RECT  42.072 36.528 42.288 36.56 ;
     RECT  42.312 36.528 42.528 36.56 ;
     RECT  42.552 36.528 42.768 36.56 ;
     RECT  42.792 36.528 43.008 36.56 ;
     RECT  43.032 36.528 43.248 36.56 ;
     RECT  43.272 36.528 43.488 36.56 ;
     RECT  43.512 36.528 43.728 36.56 ;
     RECT  43.752 36.528 43.968 36.56 ;
     RECT  43.992 36.528 44.208 36.56 ;
     RECT  44.232 36.528 44.448 36.56 ;
     RECT  44.472 36.528 44.688 36.56 ;
     RECT  44.712 36.528 44.928 36.56 ;
     RECT  44.952 36.528 45.216 36.56 ;
     RECT  45.24 36.528 45.456 36.56 ;
     RECT  45.48 36.528 45.696 36.56 ;
     RECT  45.72 36.528 45.936 36.56 ;
     RECT  45.96 36.528 46.176 36.56 ;
     RECT  46.2 36.528 46.416 36.56 ;
     RECT  46.44 36.528 46.656 36.56 ;
     RECT  46.68 36.528 46.896 36.56 ;
     RECT  46.92 36.528 47.136 36.56 ;
     RECT  47.16 36.528 47.376 36.56 ;
     RECT  47.4 36.528 47.616 36.56 ;
     RECT  47.64 36.528 47.856 36.56 ;
     RECT  47.88 36.528 48.096 36.56 ;
     RECT  48.12 36.528 48.384 36.56 ;
     RECT  48.408 36.528 48.624 36.56 ;
     RECT  48.648 36.528 48.864 36.56 ;
     RECT  48.888 36.528 49.104 36.56 ;
     RECT  49.128 36.528 49.344 36.56 ;
     RECT  49.368 36.528 49.584 36.56 ;
     RECT  49.608 36.528 49.824 36.56 ;
     RECT  49.848 36.528 50.064 36.56 ;
     RECT  50.088 36.528 50.304 36.56 ;
     RECT  50.328 36.528 50.544 36.56 ;
     RECT  50.568 36.528 50.784 36.56 ;
     RECT  50.808 36.528 51.024 36.56 ;
     RECT  51.048 36.528 51.264 36.56 ;
     RECT  51.288 36.528 51.552 36.56 ;
     RECT  51.576 36.528 51.792 36.56 ;
     RECT  51.816 36.528 52.032 36.56 ;
     RECT  52.056 36.528 52.272 36.56 ;
     RECT  52.296 36.528 52.512 36.56 ;
     RECT  52.536 36.528 52.752 36.56 ;
     RECT  52.776 36.528 52.992 36.56 ;
     RECT  53.016 36.528 53.232 36.56 ;
     RECT  53.256 36.528 53.472 36.56 ;
     RECT  53.496 36.528 53.712 36.56 ;
     RECT  53.736 36.528 53.952 36.56 ;
     RECT  53.976 36.528 54.192 36.56 ;
     RECT  54.216 36.528 54.48 36.56 ;
     RECT  54.504 36.528 54.72 36.56 ;
     RECT  54.744 36.528 54.96 36.56 ;
     RECT  54.984 36.528 55.2 36.56 ;
     RECT  55.224 36.528 55.44 36.56 ;
     RECT  55.464 36.528 55.68 36.56 ;
     RECT  55.704 36.528 55.92 36.56 ;
     RECT  55.944 36.528 56.16 36.56 ;
     RECT  56.184 36.528 56.4 36.56 ;
     RECT  56.424 36.528 56.64 36.56 ;
     RECT  56.664 36.528 56.88 36.56 ;
     RECT  56.904 36.528 57.12 36.56 ;
     RECT  57.144 36.528 57.36 36.56 ;
     RECT  57.384 36.528 57.648 36.56 ;
     RECT  57.672 36.528 57.888 36.56 ;
     RECT  57.912 36.528 58.128 36.56 ;
     RECT  58.152 36.528 58.368 36.56 ;
     RECT  58.392 36.528 58.608 36.56 ;
     RECT  58.632 36.528 58.848 36.56 ;
     RECT  58.872 36.528 59.088 36.56 ;
     RECT  59.112 36.528 59.328 36.56 ;
     RECT  59.352 36.528 59.568 36.56 ;
     RECT  59.592 36.528 59.808 36.56 ;
     RECT  59.832 36.528 60.048 36.56 ;
     RECT  60.072 36.528 60.288 36.56 ;
     RECT  60.312 36.528 60.528 36.56 ;
     RECT  60.552 36.528 60.816 36.56 ;
     RECT  60.84 36.528 61.056 36.56 ;
     RECT  61.08 36.528 61.296 36.56 ;
     RECT  61.32 36.528 61.536 36.56 ;
     RECT  61.56 36.528 61.776 36.56 ;
     RECT  61.8 36.528 62.016 36.56 ;
     RECT  62.04 36.528 62.256 36.56 ;
     RECT  62.28 36.528 62.496 36.56 ;
     RECT  62.52 36.528 62.736 36.56 ;
     RECT  62.76 36.528 62.976 36.56 ;
     RECT  63 36.528 63.216 36.56 ;
     RECT  63.24 36.528 63.456 36.56 ;
     RECT  63.48 36.528 63.696 36.56 ;
     RECT  63.72 36.528 63.984 36.56 ;
     RECT  64.008 36.528 64.224 36.56 ;
     RECT  64.248 36.528 64.464 36.56 ;
     RECT  64.488 36.528 64.704 36.56 ;
     RECT  64.728 36.528 64.944 36.56 ;
     RECT  64.968 36.528 65.184 36.56 ;
     RECT  65.208 36.528 65.424 36.56 ;
     RECT  65.448 36.528 65.664 36.56 ;
     RECT  65.688 36.528 65.904 36.56 ;
     RECT  65.928 36.528 66.144 36.56 ;
     RECT  66.168 36.528 66.384 36.56 ;
     RECT  66.408 36.528 66.624 36.56 ;
     RECT  66.648 36.528 66.864 36.56 ;
     RECT  15.624 0.133 15.648 0.144 ;
     RECT  15.768 0.133 15.888 0.144 ;
     RECT  16.008 0.133 16.128 0.144 ;
     RECT  16.248 0.133 16.368 0.144 ;
     RECT  16.488 0.133 16.608 0.144 ;
     RECT  16.728 0.133 16.848 0.144 ;
     RECT  14.28 1.763 15.6 2.339 ;
     RECT  65.208 1.763 66.192 2.725 ;
     RECT  6.216 1.811 7.392 2.291 ;
     RECT  10.812 1.811 11.808 2.915 ;
     RECT  47.16 1.811 48.192 2.915 ;
     RECT  43.32 1.859 44.448 4.115 ;
     RECT  33.528 2.291 34.704 2.915 ;
     RECT  14.28 2.339 15.744 2.915 ;
     RECT  51.816 2.339 52.944 3.397 ;
     RECT  10.812 2.915 12.048 4.595 ;
     RECT  15.36 2.915 15.744 3.397 ;
     RECT  29.832 2.915 30.816 3.443 ;
     RECT  33 2.915 34.704 4.117 ;
     RECT  12.216 3.347 13.2 4.501 ;
     RECT  51.864 3.397 52.944 3.733 ;
     RECT  9 3.443 10.176 5.029 ;
     RECT  35.208 3.443 36.72 6.323 ;
     RECT  44.472 3.443 45.6 4.115 ;
     RECT  49.272 3.443 50.688 5.171 ;
     RECT  7.68 3.539 7.8 4.645 ;
     RECT  27.384 4.067 28.464 5.747 ;
     RECT  43.32 4.115 43.896 4.261 ;
     RECT  10.812 4.595 12.192 5.845 ;
     RECT  19.176 4.595 20.16 4.643 ;
     RECT  33.624 4.595 34.704 4.643 ;
     RECT  65.448 4.595 66.624 5.747 ;
     RECT  19.176 4.643 20.496 4.739 ;
     RECT  33.624 4.643 34.8 6.899 ;
     RECT  9.048 5.029 10.176 5.461 ;
     RECT  46.776 5.077 48.3 5.173 ;
     RECT  37.812 5.171 38.976 5.459 ;
     RECT  49.272 5.171 50.832 5.365 ;
     RECT  46.776 5.173 48.192 5.987 ;
     RECT  41.592 5.219 42.624 6.323 ;
     RECT  49.416 5.365 50.832 5.795 ;
     RECT  37.812 5.459 39.312 6.899 ;
     RECT  27.144 5.747 28.464 5.939 ;
     RECT  51.312 5.747 52.416 6.323 ;
     RECT  8.112 5.795 9.6 6.275 ;
     RECT  27.012 5.939 28.464 6.323 ;
     RECT  46.728 5.987 48.192 6.323 ;
     RECT  10.812 6.323 12.192 6.851 ;
     RECT  27.012 6.323 28.512 6.899 ;
     RECT  35.208 6.323 37.104 6.899 ;
     RECT  41.4 6.323 42.624 6.563 ;
     RECT  54.012 6.323 55.248 7.475 ;
     RECT  22.824 6.371 24 6.659 ;
     RECT  62.112 6.371 63.12 6.803 ;
     RECT  63.192 6.467 64.272 9.155 ;
     RECT  32.412 6.515 33.6 6.899 ;
     RECT  62.112 6.803 63.168 9.731 ;
     RECT  35.208 6.899 35.88 7.237 ;
     RECT  59.412 6.995 60.432 7.331 ;
     RECT  56.712 8.003 57.792 9.731 ;
     RECT  57.816 8.579 59.1 9.731 ;
     RECT  63.192 9.155 64.5 9.731 ;
     RECT  8.112 30.181 9.12 30.469 ;
     RECT  9.144 30.181 10.5 30.709 ;
     RECT  22.536 30.181 24 30.469 ;
     RECT  54.984 30.181 56.4 30.469 ;
     RECT  11.832 30.469 13.2 30.661 ;
     RECT  22.776 30.469 24 30.565 ;
     RECT  24.312 30.469 25.44 34.213 ;
     RECT  25.464 30.469 26.7 30.565 ;
     RECT  43.212 30.469 44.688 30.709 ;
     RECT  47.16 30.469 48.3 30.565 ;
     RECT  57.384 30.469 58.368 30.805 ;
     RECT  22.776 30.565 23.76 30.661 ;
     RECT  25.464 30.565 26.592 30.709 ;
     RECT  47.16 30.565 48.192 30.661 ;
     RECT  5.976 30.661 7.392 30.709 ;
     RECT  19.608 30.661 20.592 30.709 ;
     RECT  62.664 30.661 63.696 30.709 ;
     RECT  64.812 30.661 65.904 34.213 ;
     RECT  5.976 30.709 7.152 30.757 ;
     RECT  43.512 30.709 44.688 30.805 ;
     RECT  14.76 30.757 15.9 31.189 ;
     RECT  16.212 30.805 17.184 30.997 ;
     RECT  28.152 30.805 29.4 31.093 ;
     RECT  30.12 30.805 31.296 34.213 ;
     RECT  41.784 30.805 42.9 31.285 ;
     RECT  48.612 30.805 49.824 31.285 ;
     RECT  39.144 30.997 40.2 34.213 ;
     RECT  28.152 31.093 29.28 34.213 ;
     RECT  66.648 34.583 66.888 35.893 ;
  END
END dsfd_hstnv_514
END LIBRARY
